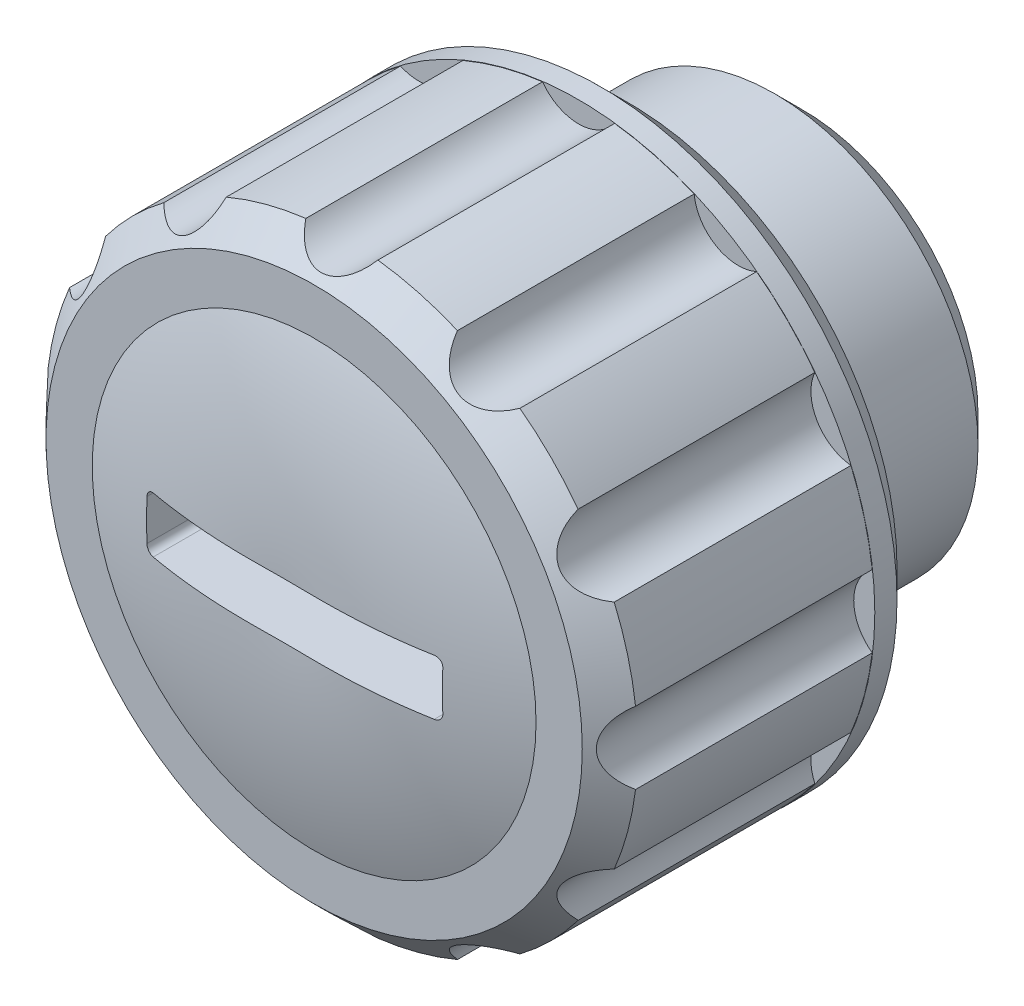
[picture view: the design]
ISO-10303-21;
HEADER;
FILE_DESCRIPTION(('STEP AP214'),'2;1');
FILE_NAME('part.step','',(''),(''),'','','');
FILE_SCHEMA(('AUTOMOTIVE_DESIGN { 1 0 10303 214 1 1 1 1 }'));
ENDSEC;
DATA;
#1=APPLICATION_CONTEXT('core data for automotive mechanical design processes');
#2=APPLICATION_PROTOCOL_DEFINITION('international standard','automotive_design',2000,#1);
#3=PRODUCT_CONTEXT('',#1,'mechanical');
#4=PRODUCT('Part','Part','',(#3));
#5=PRODUCT_RELATED_PRODUCT_CATEGORY('part','',(#4));
#6=PRODUCT_DEFINITION_FORMATION('','',#4);
#7=PRODUCT_DEFINITION_CONTEXT('part definition',#1,'design');
#8=PRODUCT_DEFINITION('design','',#6,#7);
#9=PRODUCT_DEFINITION_SHAPE('','',#8);
#10=(LENGTH_UNIT() NAMED_UNIT(*) SI_UNIT(.MILLI.,.METRE.));
#11=(NAMED_UNIT(*) PLANE_ANGLE_UNIT() SI_UNIT($,.RADIAN.));
#12=(NAMED_UNIT(*) SI_UNIT($,.STERADIAN.) SOLID_ANGLE_UNIT());
#13=UNCERTAINTY_MEASURE_WITH_UNIT(LENGTH_MEASURE(1.E-05),#10,'distance_accuracy_value','');
#14=(GEOMETRIC_REPRESENTATION_CONTEXT(3) GLOBAL_UNCERTAINTY_ASSIGNED_CONTEXT((#13)) GLOBAL_UNIT_ASSIGNED_CONTEXT((#10,
#11,#12)) REPRESENTATION_CONTEXT('',''));
#15=CARTESIAN_POINT('',(0.,0.,0.));
#16=DIRECTION('',(0.,0.,1.));
#17=DIRECTION('',(1.,0.,0.));
#18=AXIS2_PLACEMENT_3D('',#15,#16,#17);
#19=CARTESIAN_POINT('',(0.,0.,-0.703698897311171));
#20=DIRECTION('',(0.,0.,1.));
#21=DIRECTION('',(1.,0.,0.));
#22=AXIS2_PLACEMENT_3D('',#19,#20,#21);
#23=DEGENERATE_TOROIDAL_SURFACE('',#22,1.1776626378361,15.,.T.);
#24=CARTESIAN_POINT('',(0.,0.,13.5));
#25=DIRECTION('',(0.,0.,1.));
#26=DIRECTION('',(1.,0.,0.));
#27=AXIS2_PLACEMENT_3D('',#24,#25,#26);
#28=CIRCLE('',#27,6.);
#29=CARTESIAN_POINT('',(6.,0.,13.5));
#30=VERTEX_POINT('',#29);
#31=EDGE_CURVE('E425',#30,#30,#28,.T.);
#32=ORIENTED_EDGE('',*,*,#31,.T.);
#33=EDGE_LOOP('',(#32));
#34=FACE_BOUND('',#33,.T.);
#35=CARTESIAN_POINT('',(-3.7998,-0.749999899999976,14.0521326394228));
#36=CARTESIAN_POINT('',(-3.81114880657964,-0.750020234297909,14.0500982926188));
#37=CARTESIAN_POINT('',(-3.82250108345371,-0.749057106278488,14.0480843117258));
#38=CARTESIAN_POINT('',(-3.84489426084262,-0.745224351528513,14.0441543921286));
#39=CARTESIAN_POINT('',(-3.85593522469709,-0.742355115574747,14.0422384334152));
#40=CARTESIAN_POINT('',(-3.87740011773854,-0.734767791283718,14.0385596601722));
#41=CARTESIAN_POINT('',(-3.88782359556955,-0.730048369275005,14.0367969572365));
#42=CARTESIAN_POINT('',(-3.90773653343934,-0.718887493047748,14.0334807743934));
#43=CARTESIAN_POINT('',(-3.91722631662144,-0.712446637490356,14.0319272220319));
#44=CARTESIAN_POINT('',(-3.93490505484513,-0.698084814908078,14.0290917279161));
#45=CARTESIAN_POINT('',(-3.9431055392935,-0.690178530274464,14.027807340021));
#46=CARTESIAN_POINT('',(-3.95806529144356,-0.673063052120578,14.025533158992));
#47=CARTESIAN_POINT('',(-3.96482436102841,-0.663853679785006,14.0245434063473));
#48=CARTESIAN_POINT('',(-3.97659283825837,-0.644555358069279,14.0229052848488));
#49=CARTESIAN_POINT('',(-3.98162854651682,-0.634482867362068,14.0222516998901));
#50=CARTESIAN_POINT('',(-3.98994131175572,-0.613624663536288,14.0212843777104));
#51=CARTESIAN_POINT('',(-3.99321964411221,-0.602839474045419,14.0209703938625));
#52=CARTESIAN_POINT('',(-3.99704991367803,-0.584948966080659,14.0207435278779));
#53=CARTESIAN_POINT('',(-3.99816189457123,-0.577959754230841,14.0207251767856));
#54=CARTESIAN_POINT('',(-3.99964030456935,-0.563913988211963,14.0208265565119));
#55=CARTESIAN_POINT('',(-4.00000779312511,-0.556857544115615,14.0209460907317));
#56=CARTESIAN_POINT('',(-3.9999999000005,-0.549800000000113,14.0211342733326));
#57=B_SPLINE_CURVE_WITH_KNOTS('',3,(#35,#36,#37,#38,#39,#40,#41,#42,#43,#44,#45,#46,#47,#48,#49,
#50,#51,#52,#53,#54,#55,#56),.UNSPECIFIED.,.F.,.F.,(4,2,2,2,2,2,2,2,2,2,4),(0.,
0.0345466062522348,0.0690861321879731,0.103650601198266,0.138203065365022,0.172426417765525,
0.206654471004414,0.240334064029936,0.273989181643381,0.295182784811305,0.316346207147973),.UNSPECIFIED.);
#58=CARTESIAN_POINT('',(-3.8,-0.75,14.0520967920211));
#59=VERTEX_POINT('',#58);
#60=CARTESIAN_POINT('',(-4.,-0.55,14.02112896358));
#61=VERTEX_POINT('',#60);
#62=EDGE_CURVE('E27',#59,#61,#57,.T.);
#63=ORIENTED_EDGE('',*,*,#62,.T.);
#64=CARTESIAN_POINT('',(-4.,0.,14.028388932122));
#65=CARTESIAN_POINT('',(-4.,0.339153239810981,14.0283961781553));
#66=CARTESIAN_POINT('',(-4.,0.678323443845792,14.0201840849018));
#67=CARTESIAN_POINT('',(-4.,1.35574448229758,13.9866878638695));
#68=CARTESIAN_POINT('',(-4.,1.69399552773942,13.9614080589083));
#69=CARTESIAN_POINT('',(-4.,2.36814839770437,13.8923714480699));
#70=CARTESIAN_POINT('',(-4.,2.7040529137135,13.8486414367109));
#71=CARTESIAN_POINT('',(-4.,3.37274568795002,13.7413643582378));
#72=CARTESIAN_POINT('',(-4.,3.70553346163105,13.6778142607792));
#73=CARTESIAN_POINT('',(-4.,4.45788889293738,13.5095576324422));
#74=CARTESIAN_POINT('',(-4.,4.87602372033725,13.3983308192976));
#75=CARTESIAN_POINT('',(-4.,5.70161656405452,13.1413580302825));
#76=CARTESIAN_POINT('',(-4.,6.10907328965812,12.9956079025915));
#77=CARTESIAN_POINT('',(-4.,6.91043852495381,12.6696375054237));
#78=CARTESIAN_POINT('',(-4.,7.30433371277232,12.4893844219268));
#79=CARTESIAN_POINT('',(-4.,8.07498519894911,12.0953512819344));
#80=CARTESIAN_POINT('',(-4.,8.45174183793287,11.8815718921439));
#81=CARTESIAN_POINT('',(-4.,9.18281763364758,11.4232419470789));
#82=CARTESIAN_POINT('',(-4.,9.53726091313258,11.1788894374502));
#83=CARTESIAN_POINT('',(-4.,10.2233955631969,10.6600773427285));
#84=CARTESIAN_POINT('',(-4.,10.5550867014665,10.3856174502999));
#85=CARTESIAN_POINT('',(-4.,11.1930381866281,9.8086212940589));
#86=CARTESIAN_POINT('',(-4.,11.4993002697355,9.50608695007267));
#87=CARTESIAN_POINT('',(-4.,12.0839658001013,8.87520844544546));
#88=CARTESIAN_POINT('',(-4.,12.3623701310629,8.54686510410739));
#89=CARTESIAN_POINT('',(-4.,12.8784698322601,7.8806109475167));
#90=CARTESIAN_POINT('',(-4.,13.1173543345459,7.54362037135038));
#91=CARTESIAN_POINT('',(-4.,13.5656684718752,6.85059247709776));
#92=CARTESIAN_POINT('',(-4.,13.7750989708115,6.49455571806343));
#93=CARTESIAN_POINT('',(-4.,14.1629376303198,5.76604322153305));
#94=CARTESIAN_POINT('',(-4.,14.3413507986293,5.39357014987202));
#95=CARTESIAN_POINT('',(-4.,14.6658865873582,4.63480988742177));
#96=CARTESIAN_POINT('',(-4.,14.8120091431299,4.24852266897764));
#97=CARTESIAN_POINT('',(-4.,15.0699099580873,3.46788913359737));
#98=CARTESIAN_POINT('',(-4.,15.1819394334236,3.07362578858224));
#99=CARTESIAN_POINT('',(-4.,15.3723250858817,2.2770527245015));
#100=CARTESIAN_POINT('',(-4.,15.4506814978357,1.87474306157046));
#101=CARTESIAN_POINT('',(-4.,15.5731575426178,1.06492658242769));
#102=CARTESIAN_POINT('',(-4.,15.617275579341,0.657419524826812));
#103=CARTESIAN_POINT('',(-4.,15.6709496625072,-0.159864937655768));
#104=CARTESIAN_POINT('',(-4.,15.6805056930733,-0.569642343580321));
#105=CARTESIAN_POINT('',(-4.,15.665001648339,-1.38774900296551));
#106=CARTESIAN_POINT('',(-4.,15.6400084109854,-1.7960795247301));
#107=CARTESIAN_POINT('',(-4.,15.5557048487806,-2.60918184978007));
#108=CARTESIAN_POINT('',(-4.,15.4963945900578,-3.01395365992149));
#109=CARTESIAN_POINT('',(-4.,15.3438918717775,-3.8170229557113));
#110=CARTESIAN_POINT('',(-4.,15.2507026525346,-4.21532105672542));
#111=CARTESIAN_POINT('',(-4.,15.0311128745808,-5.00265431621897));
#112=CARTESIAN_POINT('',(-4.,14.9047123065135,-5.39168947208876));
#113=CARTESIAN_POINT('',(-4.,14.619619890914,-6.15771427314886));
#114=CARTESIAN_POINT('',(-4.,14.4609300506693,-6.53470466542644));
#115=CARTESIAN_POINT('',(-4.,14.112398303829,-7.27399825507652));
#116=CARTESIAN_POINT('',(-4.,13.9225564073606,-7.63630145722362));
#117=CARTESIAN_POINT('',(-4.,13.5130367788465,-8.34375702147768));
#118=CARTESIAN_POINT('',(-4.,13.2933514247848,-8.68890497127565));
#119=CARTESIAN_POINT('',(-4.,12.825767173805,-9.35952806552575));
#120=CARTESIAN_POINT('',(-4.,12.5778682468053,-9.68500318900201));
#121=CARTESIAN_POINT('',(-4.,12.0550681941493,-10.3147088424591));
#122=CARTESIAN_POINT('',(-4.,11.7801085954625,-10.6188908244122));
#123=CARTESIAN_POINT('',(-4.,11.2056412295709,-11.2031141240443));
#124=CARTESIAN_POINT('',(-4.,10.9061334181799,-11.4831553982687));
#125=CARTESIAN_POINT('',(-4.,10.2849635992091,-12.0170071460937));
#126=CARTESIAN_POINT('',(-4.,9.96331753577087,-12.2708361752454));
#127=CARTESIAN_POINT('',(-4.,9.30001359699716,-12.7508263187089));
#128=CARTESIAN_POINT('',(-4.,8.95835585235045,-12.9769876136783));
#129=CARTESIAN_POINT('',(-4.,8.25506085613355,-13.4017235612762));
#130=CARTESIAN_POINT('',(-4.,7.89330122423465,-13.6000955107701));
#131=CARTESIAN_POINT('',(-4.,7.1546361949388,-13.9662854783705));
#132=CARTESIAN_POINT('',(-4.,6.77773047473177,-14.1341028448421));
#133=CARTESIAN_POINT('',(-4.,6.01113338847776,-14.4386630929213));
#134=CARTESIAN_POINT('',(-4.,5.62142902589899,-14.5753731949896));
#135=CARTESIAN_POINT('',(-4.,4.83241304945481,-14.817363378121));
#136=CARTESIAN_POINT('',(-4.,4.4331021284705,-14.9226457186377));
#137=CARTESIAN_POINT('',(-4.,3.77164652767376,-15.0703302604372));
#138=CARTESIAN_POINT('',(-4.,3.51147362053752,-15.1217585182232));
#139=CARTESIAN_POINT('',(-4.,2.98899804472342,-15.2123395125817));
#140=CARTESIAN_POINT('',(-4.,2.7266952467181,-15.2514914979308));
#141=CARTESIAN_POINT('',(-4.,1.93724201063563,-15.3514509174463));
#142=CARTESIAN_POINT('',(-4.,1.40777675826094,-15.3947116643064));
#143=CARTESIAN_POINT('',(-4.,0.612198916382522,-15.4285188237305));
#144=CARTESIAN_POINT('',(-4.,0.346571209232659,-15.4345998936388));
#145=CARTESIAN_POINT('',(-4.,-0.184756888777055,-15.4366600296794));
#146=CARTESIAN_POINT('',(-4.,-0.450457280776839,-15.4326389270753));
#147=CARTESIAN_POINT('',(-4.,-0.981374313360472,-15.4142959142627));
#148=CARTESIAN_POINT('',(-4.,-1.24659112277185,-15.3999788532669));
#149=CARTESIAN_POINT('',(-4.,-1.7762314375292,-15.3604541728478));
#150=CARTESIAN_POINT('',(-4.,-2.04065492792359,-15.3352463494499));
#151=CARTESIAN_POINT('',(-4.,-2.52470132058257,-15.2783376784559));
#152=CARTESIAN_POINT('',(-4.,-2.74453002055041,-15.248390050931));
#153=CARTESIAN_POINT('',(-4.,-3.18285214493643,-15.1800456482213));
#154=CARTESIAN_POINT('',(-4.,-3.40134562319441,-15.1416492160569));
#155=CARTESIAN_POINT('',(-4.,-4.05419633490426,-15.0133381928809));
#156=CARTESIAN_POINT('',(-4.,-4.48606739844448,-14.9102854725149));
#157=CARTESIAN_POINT('',(-4.,-5.33835432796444,-14.6682914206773));
#158=CARTESIAN_POINT('',(-4.,-5.75879820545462,-14.5294486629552));
#159=CARTESIAN_POINT('',(-4.,-6.58609234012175,-14.2156839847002));
#160=CARTESIAN_POINT('',(-4.,-6.99294114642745,-14.0407582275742));
#161=CARTESIAN_POINT('',(-4.,-7.79138450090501,-13.6547019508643));
#162=CARTESIAN_POINT('',(-4.,-8.18290123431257,-13.4434103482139));
#163=CARTESIAN_POINT('',(-4.,-8.94537896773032,-12.9865110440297));
#164=CARTESIAN_POINT('',(-4.,-9.31634014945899,-12.7409036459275));
#165=CARTESIAN_POINT('',(-4.,-10.0350527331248,-12.2167860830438));
#166=CARTESIAN_POINT('',(-4.,-10.3827705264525,-11.9382298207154));
#167=CARTESIAN_POINT('',(-4.,-11.0514362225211,-11.350662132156));
#168=CARTESIAN_POINT('',(-4.,-11.3723853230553,-11.0416520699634));
#169=CARTESIAN_POINT('',(-4.,-11.9642331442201,-10.4173353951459));
#170=CARTESIAN_POINT('',(-4.,-12.2370447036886,-10.1038391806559));
#171=CARTESIAN_POINT('',(-4.,-12.7549508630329,-9.4547474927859));
#172=CARTESIAN_POINT('',(-4.,-13.0000469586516,-9.11915321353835));
#173=CARTESIAN_POINT('',(-4.,-13.4605522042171,-8.42850547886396));
#174=CARTESIAN_POINT('',(-4.,-13.67598107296,-8.07346517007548));
#175=CARTESIAN_POINT('',(-4.,-14.0757477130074,-7.34628666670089));
#176=CARTESIAN_POINT('',(-4.,-14.2600853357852,-6.97414839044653));
#177=CARTESIAN_POINT('',(-4.,-14.5943069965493,-6.21997693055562));
#178=CARTESIAN_POINT('',(-4.,-14.7445728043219,-5.83811287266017));
#179=CARTESIAN_POINT('',(-4.,-15.0123145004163,-5.06306047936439));
#180=CARTESIAN_POINT('',(-4.,-15.1297907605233,-4.669872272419));
#181=CARTESIAN_POINT('',(-4.,-15.3311166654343,-3.87492033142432));
#182=CARTESIAN_POINT('',(-4.,-15.4149615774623,-3.47315539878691));
#183=CARTESIAN_POINT('',(-4.,-15.5483930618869,-2.66397544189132));
#184=CARTESIAN_POINT('',(-4.,-15.5979796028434,-2.25656041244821));
#185=CARTESIAN_POINT('',(-4.,-15.6624394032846,-1.44020146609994));
#186=CARTESIAN_POINT('',(-4.,-15.6774144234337,-1.03126558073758));
#187=CARTESIAN_POINT('',(-4.,-15.6728420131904,-0.213587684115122));
#188=CARTESIAN_POINT('',(-4.,-15.653294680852,0.19515432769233));
#189=CARTESIAN_POINT('',(-4.,-15.5798200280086,1.00952109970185));
#190=CARTESIAN_POINT('',(-4.,-15.5258939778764,1.41514597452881));
#191=CARTESIAN_POINT('',(-4.,-15.3840519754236,2.22040863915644));
#192=CARTESIAN_POINT('',(-4.,-15.2961360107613,2.62004642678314));
#193=CARTESIAN_POINT('',(-4.,-15.0869932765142,3.41032437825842));
#194=CARTESIAN_POINT('',(-4.,-14.9657808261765,3.8009683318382));
#195=CARTESIAN_POINT('',(-4.,-14.6909025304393,4.57066557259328));
#196=CARTESIAN_POINT('',(-4.,-14.5372367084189,4.94971886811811));
#197=CARTESIAN_POINT('',(-4.,-14.198563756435,5.6935427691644));
#198=CARTESIAN_POINT('',(-4.,-14.0135574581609,6.05831375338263));
#199=CARTESIAN_POINT('',(-4.,-13.6135344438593,6.77101064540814));
#200=CARTESIAN_POINT('',(-4.,-13.3985177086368,7.11893654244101));
#201=CARTESIAN_POINT('',(-4.,-12.9397392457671,7.79592064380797));
#202=CARTESIAN_POINT('',(-4.,-12.695942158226,8.12495488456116));
#203=CARTESIAN_POINT('',(-4.,-12.1815798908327,8.76138756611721));
#204=CARTESIAN_POINT('',(-4.,-11.91101469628,9.068785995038));
#205=CARTESIAN_POINT('',(-4.,-11.3450384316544,9.65985804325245));
#206=CARTESIAN_POINT('',(-4.,-11.049624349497,9.94352877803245));
#207=CARTESIAN_POINT('',(-4.,-10.4361166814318,10.4851767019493));
#208=CARTESIAN_POINT('',(-4.,-10.1180230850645,10.7431538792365));
#209=CARTESIAN_POINT('',(-4.,-9.45975657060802,11.2329803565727));
#210=CARTESIAN_POINT('',(-4.,-9.11947790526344,11.4646875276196));
#211=CARTESIAN_POINT('',(-4.,-8.42081797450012,11.8989645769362));
#212=CARTESIAN_POINT('',(-4.,-8.06243669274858,12.1015344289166));
#213=CARTESIAN_POINT('',(-4.,-7.33043234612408,12.476268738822));
#214=CARTESIAN_POINT('',(-4.,-6.95681985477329,12.6484538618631));
#215=CARTESIAN_POINT('',(-4.,-6.19684574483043,12.961845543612));
#216=CARTESIAN_POINT('',(-4.,-5.81048403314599,13.1030518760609));
#217=CARTESIAN_POINT('',(-4.,-4.98307663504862,13.3686004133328));
#218=CARTESIAN_POINT('',(-4.,-4.54082134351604,13.4891802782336));
#219=CARTESIAN_POINT('',(-4.,-3.64769934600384,13.6923551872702));
#220=CARTESIAN_POINT('',(-4.,-3.19683149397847,13.774945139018));
#221=CARTESIAN_POINT('',(-4.,-2.28933102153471,13.9045907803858));
#222=CARTESIAN_POINT('',(-4.,-1.83269032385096,13.9515893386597));
#223=CARTESIAN_POINT('',(-4.,-1.14623014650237,13.9979727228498));
#224=CARTESIAN_POINT('',(-4.,-0.917138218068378,14.0094147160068));
#225=CARTESIAN_POINT('',(-4.,-0.458700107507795,14.0246202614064));
#226=CARTESIAN_POINT('',(-4.,-0.229353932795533,14.0283840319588));
#227=CARTESIAN_POINT('',(-4.,0.,14.028388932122));
#228=B_SPLINE_CURVE_WITH_KNOTS('',3,(#64,#65,#66,#67,#68,#69,#70,#71,#72,#73,#74,#75,#76,#77,
#78,#79,#80,#81,#82,#83,#84,#85,#86,#87,#88,#89,#90,#91,#92,#93,#94,#95,#96,#97,#98,#99,#100,
#101,#102,#103,#104,#105,#106,#107,#108,#109,#110,#111,#112,#113,#114,#115,#116,#117,#118,#119,
#120,#121,#122,#123,#124,#125,#126,#127,#128,#129,#130,#131,#132,#133,#134,#135,#136,#137,#138,
#139,#140,#141,#142,#143,#144,#145,#146,#147,#148,#149,#150,#151,#152,#153,#154,#155,#156,#157,
#158,#159,#160,#161,#162,#163,#164,#165,#166,#167,#168,#169,#170,#171,#172,#173,#174,#175,#176,
#177,#178,#179,#180,#181,#182,#183,#184,#185,#186,#187,#188,#189,#190,#191,#192,#193,#194,#195,
#196,#197,#198,#199,#200,#201,#202,#203,#204,#205,#206,#207,#208,#209,#210,#211,#212,#213,#214,
#215,#216,#217,#218,#219,#220,#221,#222,#223,#224,#225,#226,#227),.UNSPECIFIED.,.T.,.F.,(4,2,2,
2,2,2,2,2,2,2,2,2,2,2,2,2,2,2,2,2,2,2,2,2,2,2,2,2,2,2,2,2,2,2,2,2,2,2,2,2,2,2,2,2,2,2,2,2,2,2,2,
2,2,2,2,2,2,2,2,2,2,2,2,2,2,2,2,2,2,2,2,2,2,2,2,2,2,2,2,2,2,4),(0.,1.01738294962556,
2.03450831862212,3.05016161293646,4.06597026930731,5.36249424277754,6.6591742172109,
7.95709358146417,9.25498713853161,10.5448707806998,11.8347675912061,13.1245762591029,
14.4143439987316,15.6520836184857,16.8897869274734,18.1272902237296,19.3647959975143,
20.5929491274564,21.8210936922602,23.0492955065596,24.2774978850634,25.5033275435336,
26.7291548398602,27.9548649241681,29.1805753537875,30.4062096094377,31.6318434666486,
32.8577909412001,34.0837397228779,35.3123982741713,36.5410590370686,37.7688439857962,
38.9966209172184,40.2329329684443,41.4692713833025,42.7069066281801,43.9444528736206,
44.7397910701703,45.5351779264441,47.1266553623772,47.9236225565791,48.7206030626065,
49.5172084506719,50.3138287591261,50.9792441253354,51.6446324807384,52.9749769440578,
54.301695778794,55.6285557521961,56.9614518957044,58.2943362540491,59.6291079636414,
60.9638199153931,62.2090674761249,63.4542478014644,64.6985964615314,65.9429510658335,
67.1725857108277,68.4022064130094,69.6320000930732,70.8617949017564,72.0879693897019,
73.3141403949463,74.5402660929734,75.7663922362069,76.9919919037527,78.2175906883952,
79.4431569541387,80.6687240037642,81.8958127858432,83.1229022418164,84.3501406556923,
85.5773796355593,86.8109699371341,88.0445613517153,89.2773105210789,90.510068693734,
91.8834796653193,93.2570746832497,94.632869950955,95.3208993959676,96.0089092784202),.UNSPECIFIED.);
#229=CARTESIAN_POINT('',(-4.,0.55,14.02112896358));
#230=VERTEX_POINT('',#229);
#231=EDGE_CURVE('E9',#61,#230,#228,.T.);
#232=ORIENTED_EDGE('',*,*,#231,.T.);
#233=CARTESIAN_POINT('',(-3.99999989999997,0.5498,14.0211342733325));
#234=CARTESIAN_POINT('',(-4.00002120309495,0.560882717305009,14.0208370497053));
#235=CARTESIAN_POINT('',(-3.99910147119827,0.571967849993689,14.0207119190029));
#236=CARTESIAN_POINT('',(-3.99545102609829,0.59382219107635,14.0208010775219));
#237=CARTESIAN_POINT('',(-3.99272233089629,0.604591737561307,14.021014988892));
#238=CARTESIAN_POINT('',(-3.98552323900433,0.625524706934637,14.0217769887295));
#239=CARTESIAN_POINT('',(-3.98105209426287,0.635687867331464,14.0223252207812));
#240=CARTESIAN_POINT('',(-3.97050578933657,0.655118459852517,14.0237373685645));
#241=CARTESIAN_POINT('',(-3.96443078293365,0.664385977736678,14.0246012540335));
#242=CARTESIAN_POINT('',(-3.95082544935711,0.681812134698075,14.0266217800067));
#243=CARTESIAN_POINT('',(-3.94328885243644,0.689965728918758,14.0277796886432));
#244=CARTESIAN_POINT('',(-3.92699598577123,0.704900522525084,14.030350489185));
#245=CARTESIAN_POINT('',(-3.91823946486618,0.711681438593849,14.0317634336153));
#246=CARTESIAN_POINT('',(-3.89962640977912,0.723780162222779,14.0348229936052));
#247=CARTESIAN_POINT('',(-3.88975612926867,0.729076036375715,14.0364726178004));
#248=CARTESIAN_POINT('',(-3.86929754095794,0.737941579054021,14.0399411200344));
#249=CARTESIAN_POINT('',(-3.858709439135,0.741511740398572,14.0417599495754));
#250=CARTESIAN_POINT('',(-3.84003688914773,0.746119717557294,14.0450054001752));
#251=CARTESIAN_POINT('',(-3.83204943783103,0.747581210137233,14.046405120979));
#252=CARTESIAN_POINT('',(-3.8159747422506,0.749525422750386,14.0492439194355));
#253=CARTESIAN_POINT('',(-3.80788765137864,0.750009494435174,14.0506829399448));
#254=CARTESIAN_POINT('',(-3.79980000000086,0.749999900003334,14.052132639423));
#255=B_SPLINE_CURVE_WITH_KNOTS('',3,(#233,#234,#235,#236,#237,#238,#239,#240,#241,#242,#243,
#244,#245,#246,#247,#248,#249,#250,#251,#252,#253,#254),.UNSPECIFIED.,.F.,.F.,(4,2,2,2,2,2,2,2,
2,2,4),(0.,0.0332152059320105,0.0663934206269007,0.0995858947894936,0.132775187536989,
0.166110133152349,0.199451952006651,0.233262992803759,0.267064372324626,0.291727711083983,
0.316356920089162),.UNSPECIFIED.);
#256=CARTESIAN_POINT('',(-3.79999999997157,0.75,14.0520967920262));
#257=VERTEX_POINT('',#256);
#258=EDGE_CURVE('E488',#230,#257,#255,.T.);
#259=ORIENTED_EDGE('',*,*,#258,.T.);
#260=CARTESIAN_POINT('',(0.,0.75,14.2902033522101));
#261=CARTESIAN_POINT('',(0.062509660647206,0.75,14.2902036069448));
#262=CARTESIAN_POINT('',(0.125019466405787,0.75,14.2904360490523));
#263=CARTESIAN_POINT('',(0.250036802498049,0.75,14.291252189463));
#264=CARTESIAN_POINT('',(0.312544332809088,0.75,14.2918358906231));
#265=CARTESIAN_POINT('',(0.437565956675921,0.75,14.2930988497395));
#266=CARTESIAN_POINT('',(0.500080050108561,0.75,14.2937781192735));
#267=CARTESIAN_POINT('',(0.625113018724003,0.75,14.2949804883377));
#268=CARTESIAN_POINT('',(0.687631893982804,0.75,14.2955035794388));
#269=CARTESIAN_POINT('',(0.875766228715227,0.75,14.2965328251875));
#270=CARTESIAN_POINT('',(1.00138686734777,0.75,14.2964891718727));
#271=CARTESIAN_POINT('',(1.25260493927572,0.75,14.2940460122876));
#272=CARTESIAN_POINT('',(1.37820237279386,0.75,14.2916465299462));
#273=CARTESIAN_POINT('',(1.75485708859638,0.75,14.2803277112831));
#274=CARTESIAN_POINT('',(2.00580900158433,0.75,14.2672884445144));
#275=CARTESIAN_POINT('',(2.50689880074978,0.75,14.2291477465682));
#276=CARTESIAN_POINT('',(2.75703633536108,0.75,14.2040416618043));
#277=CARTESIAN_POINT('',(3.25583549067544,0.75,14.1415504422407));
#278=CARTESIAN_POINT('',(3.5044966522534,0.75,14.1041616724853));
#279=CARTESIAN_POINT('',(4.16871083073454,0.75,13.9873107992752));
#280=CARTESIAN_POINT('',(4.58233519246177,0.75,13.8965497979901));
#281=CARTESIAN_POINT('',(5.40052634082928,0.75,13.6805066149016));
#282=CARTESIAN_POINT('',(5.80509101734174,0.75,13.5552164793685));
#283=CARTESIAN_POINT('',(6.60293944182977,0.75,13.2706758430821));
#284=CARTESIAN_POINT('',(6.99620137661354,0.75,13.1113641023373));
#285=CARTESIAN_POINT('',(7.76780860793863,0.75,12.760031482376));
#286=CARTESIAN_POINT('',(8.14615456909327,0.75,12.5680120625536));
#287=CARTESIAN_POINT('',(8.88446706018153,0.75,12.1530468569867));
#288=CARTESIAN_POINT('',(9.2444697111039,0.75,11.9301653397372));
#289=CARTESIAN_POINT('',(9.9443450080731,0.75,11.4547620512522));
#290=CARTESIAN_POINT('',(10.2842175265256,0.75,11.2022400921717));
#291=CARTESIAN_POINT('',(10.9411846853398,0.75,10.6695279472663));
#292=CARTESIAN_POINT('',(11.2582935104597,0.75,10.3893552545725));
#293=CARTESIAN_POINT('',(11.867695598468,0.75,9.80321084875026));
#294=CARTESIAN_POINT('',(12.1599889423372,0.75,9.49723921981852));
#295=CARTESIAN_POINT('',(12.7167806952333,0.75,8.86269415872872));
#296=CARTESIAN_POINT('',(12.9813643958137,0.75,8.53419556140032));
#297=CARTESIAN_POINT('',(13.4819097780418,0.75,7.85607214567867));
#298=CARTESIAN_POINT('',(13.7178715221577,0.75,7.50644737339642));
#299=CARTESIAN_POINT('',(14.1595322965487,0.75,6.78849443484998));
#300=CARTESIAN_POINT('',(14.3652260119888,0.75,6.42016299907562));
#301=CARTESIAN_POINT('',(14.7448367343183,0.75,5.66747355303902));
#302=CARTESIAN_POINT('',(14.9187537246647,0.75,5.28311553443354));
#303=CARTESIAN_POINT('',(15.2335050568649,0.75,4.50127546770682));
#304=CARTESIAN_POINT('',(15.3743535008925,0.75,4.10379909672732));
#305=CARTESIAN_POINT('',(15.6220611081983,0.75,3.29839291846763));
#306=CARTESIAN_POINT('',(15.7289202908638,0.75,2.89046311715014));
#307=CARTESIAN_POINT('',(15.9078821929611,0.75,2.06708280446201));
#308=CARTESIAN_POINT('',(15.9799876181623,0.75,1.65163288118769));
#309=CARTESIAN_POINT('',(16.0889414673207,0.75,0.816135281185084));
#310=CARTESIAN_POINT('',(16.1257898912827,0.75,0.396087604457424));
#311=CARTESIAN_POINT('',(16.163965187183,0.75,-0.445565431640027));
#312=CARTESIAN_POINT('',(16.1652965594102,0.75,-0.867170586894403));
#313=CARTESIAN_POINT('',(16.1324397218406,0.75,-1.7089944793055));
#314=CARTESIAN_POINT('',(16.0982515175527,0.75,-2.12921321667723));
#315=CARTESIAN_POINT('',(15.994590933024,0.75,-2.96533956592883));
#316=CARTESIAN_POINT('',(15.9251132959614,0.75,-3.38124652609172));
#317=CARTESIAN_POINT('',(15.751365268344,0.75,-4.20572862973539));
#318=CARTESIAN_POINT('',(15.6470948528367,0.75,-4.61430376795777));
#319=CARTESIAN_POINT('',(15.4044819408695,0.75,-5.42128714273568));
#320=CARTESIAN_POINT('',(15.2661335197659,0.75,-5.8196935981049));
#321=CARTESIAN_POINT('',(14.9563586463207,0.75,-6.6034316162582));
#322=CARTESIAN_POINT('',(14.7849322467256,0.75,-6.9887631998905));
#323=CARTESIAN_POINT('',(14.410318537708,0.75,-7.74341593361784));
#324=CARTESIAN_POINT('',(14.2071477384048,0.75,-8.11274527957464));
#325=CARTESIAN_POINT('',(13.7704245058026,0.75,-8.83298393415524));
#326=CARTESIAN_POINT('',(13.5368719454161,0.75,-9.18389316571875));
#327=CARTESIAN_POINT('',(13.0411762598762,0.75,-9.86461934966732));
#328=CARTESIAN_POINT('',(12.7790481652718,0.75,-10.1944472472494));
#329=CARTESIAN_POINT('',(12.2279683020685,0.75,-10.8308662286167));
#330=CARTESIAN_POINT('',(11.9390170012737,0.75,-11.1374577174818));
#331=CARTESIAN_POINT('',(11.3358371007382,0.75,-11.7257264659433));
#332=CARTESIAN_POINT('',(11.0215672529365,0.75,-12.0073614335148));
#333=CARTESIAN_POINT('',(10.3703891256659,0.75,-12.5431585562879));
#334=CARTESIAN_POINT('',(10.0334794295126,0.75,-12.7973189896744));
#335=CARTESIAN_POINT('',(9.33882156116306,0.75,-13.2767706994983));
#336=CARTESIAN_POINT('',(8.98103735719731,0.75,-13.5020097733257));
#337=CARTESIAN_POINT('',(8.24780759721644,0.75,-13.9214489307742));
#338=CARTESIAN_POINT('',(7.87236542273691,0.75,-14.1156549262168));
#339=CARTESIAN_POINT('',(7.10830459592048,0.75,-14.4708441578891));
#340=CARTESIAN_POINT('',(6.71975907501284,0.75,-14.6319846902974));
#341=CARTESIAN_POINT('',(5.93032689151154,0.75,-14.9212008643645));
#342=CARTESIAN_POINT('',(5.52943355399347,0.75,-15.049258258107));
#343=CARTESIAN_POINT('',(4.71037120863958,0.75,-15.2735305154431));
#344=CARTESIAN_POINT('',(4.29201779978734,0.75,-15.3690765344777));
#345=CARTESIAN_POINT('',(3.65997311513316,0.75,-15.485449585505));
#346=CARTESIAN_POINT('',(3.44867138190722,0.75,-15.5197366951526));
#347=CARTESIAN_POINT('',(3.02478880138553,0.75,-15.5793924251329));
#348=CARTESIAN_POINT('',(2.81220789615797,0.75,-15.6047606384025));
#349=CARTESIAN_POINT('',(2.38452719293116,0.75,-15.6468286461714));
#350=CARTESIAN_POINT('',(2.16942066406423,0.75,-15.6634594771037));
#351=CARTESIAN_POINT('',(1.73875062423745,0.75,-15.6880212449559));
#352=CARTESIAN_POINT('',(1.5231871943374,0.75,-15.6959536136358));
#353=CARTESIAN_POINT('',(1.19954465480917,0.75,-15.7021388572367));
#354=CARTESIAN_POINT('',(1.09150789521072,0.75,-15.7032466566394));
#355=CARTESIAN_POINT('',(0.875426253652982,0.75,-15.7039178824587));
#356=CARTESIAN_POINT('',(0.767381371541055,0.75,-15.7034812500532));
#357=CARTESIAN_POINT('',(0.551281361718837,0.75,-15.7017790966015));
#358=CARTESIAN_POINT('',(0.443226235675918,0.75,-15.7005134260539));
#359=CARTESIAN_POINT('',(0.281143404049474,0.75,-15.6989476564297));
#360=CARTESIAN_POINT('',(0.227117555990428,0.75,-15.698481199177));
#361=CARTESIAN_POINT('',(0.119064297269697,0.75,-15.6978197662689));
#362=CARTESIAN_POINT('',(0.0650368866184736,0.75,-15.6976247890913));
#363=CARTESIAN_POINT('',(-0.05800398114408,0.75,-15.6975761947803));
#364=CARTESIAN_POINT('',(-0.127017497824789,0.75,-15.6978322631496));
#365=CARTESIAN_POINT('',(-0.265042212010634,0.75,-15.6987649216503));
#366=CARTESIAN_POINT('',(-0.334053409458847,0.75,-15.6994415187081));
#367=CARTESIAN_POINT('',(-0.47207998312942,0.75,-15.7008610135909));
#368=CARTESIAN_POINT('',(-0.541095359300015,0.75,-15.7016039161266));
#369=CARTESIAN_POINT('',(-0.679127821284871,0.75,-15.7028300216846));
#370=CARTESIAN_POINT('',(-0.748144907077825,0.75,-15.7033132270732));
#371=CARTESIAN_POINT('',(-0.955164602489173,0.75,-15.7040009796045));
#372=CARTESIAN_POINT('',(-1.0931724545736,0.75,-15.7034443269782));
#373=CARTESIAN_POINT('',(-1.36914222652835,0.75,-15.6993084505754));
#374=CARTESIAN_POINT('',(-1.50710414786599,0.75,-15.6957293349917));
#375=CARTESIAN_POINT('',(-1.78256534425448,0.75,-15.685188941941));
#376=CARTESIAN_POINT('',(-1.92006492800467,0.75,-15.6782359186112));
#377=CARTESIAN_POINT('',(-2.19483905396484,0.75,-15.6607772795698));
#378=CARTESIAN_POINT('',(-2.33211359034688,0.75,-15.6502715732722));
#379=CARTESIAN_POINT('',(-2.743559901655,0.75,-15.6132836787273));
#380=CARTESIAN_POINT('',(-3.01726339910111,0.75,-15.581334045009));
#381=CARTESIAN_POINT('',(-3.55992465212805,0.75,-15.5030144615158));
#382=CARTESIAN_POINT('',(-3.82890277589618,0.75,-15.4567848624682));
#383=CARTESIAN_POINT('',(-4.36392755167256,0.75,-15.3498484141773));
#384=CARTESIAN_POINT('',(-4.62997463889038,0.75,-15.2891437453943));
#385=CARTESIAN_POINT('',(-5.15895710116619,0.75,-15.1532282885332));
#386=CARTESIAN_POINT('',(-5.42188447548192,0.75,-15.0779863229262));
#387=CARTESIAN_POINT('',(-5.94322863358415,0.75,-14.9132881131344));
#388=CARTESIAN_POINT('',(-6.20164546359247,0.75,-14.8238320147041));
#389=CARTESIAN_POINT('',(-6.85115229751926,0.75,-14.5789290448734));
#390=CARTESIAN_POINT('',(-7.23867684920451,0.75,-14.4139021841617));
#391=CARTESIAN_POINT('',(-7.99805018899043,0.75,-14.0520702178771));
#392=CARTESIAN_POINT('',(-8.36991500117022,0.75,-13.8552986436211));
#393=CARTESIAN_POINT('',(-9.09777056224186,0.75,-13.4300705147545));
#394=CARTESIAN_POINT('',(-9.45366504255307,0.75,-13.2014490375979));
#395=CARTESIAN_POINT('',(-10.1449857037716,0.75,-12.714880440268));
#396=CARTESIAN_POINT('',(-10.4804049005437,0.75,-12.4569233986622));
#397=CARTESIAN_POINT('',(-11.1277254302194,0.75,-11.9140206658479));
#398=CARTESIAN_POINT('',(-11.4396635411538,0.75,-11.6291188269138));
#399=CARTESIAN_POINT('',(-12.0383542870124,0.75,-11.0340393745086));
#400=CARTESIAN_POINT('',(-12.3251095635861,0.75,-10.7238644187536));
#401=CARTESIAN_POINT('',(-12.870898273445,0.75,-10.0810426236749));
#402=CARTESIAN_POINT('',(-13.1299839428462,0.75,-9.74844013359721));
#403=CARTESIAN_POINT('',(-13.619228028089,0.75,-9.06258526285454));
#404=CARTESIAN_POINT('',(-13.8493856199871,0.75,-8.70933229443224));
#405=CARTESIAN_POINT('',(-14.2791137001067,0.75,-7.98471878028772));
#406=CARTESIAN_POINT('',(-14.4786861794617,0.75,-7.61335941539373));
#407=CARTESIAN_POINT('',(-14.8458413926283,0.75,-6.85515348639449));
#408=CARTESIAN_POINT('',(-15.0134243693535,0.75,-6.46830703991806));
#409=CARTESIAN_POINT('',(-15.3155070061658,0.75,-5.6816225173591));
#410=CARTESIAN_POINT('',(-15.4499855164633,0.75,-5.2817763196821));
#411=CARTESIAN_POINT('',(-15.6847633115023,0.75,-4.47217121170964));
#412=CARTESIAN_POINT('',(-15.7850625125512,0.75,-4.06241227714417));
#413=CARTESIAN_POINT('',(-15.9507352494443,0.75,-3.23605764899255));
#414=CARTESIAN_POINT('',(-16.0161221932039,0.75,-2.81946464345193));
#415=CARTESIAN_POINT('',(-16.1115638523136,0.75,-1.98225120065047));
#416=CARTESIAN_POINT('',(-16.1416186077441,0.75,-1.56163076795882));
#417=CARTESIAN_POINT('',(-16.1661796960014,0.75,-0.719438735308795));
#418=CARTESIAN_POINT('',(-16.1606932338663,0.75,-0.297867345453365));
#419=CARTESIAN_POINT('',(-16.114227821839,0.75,0.543314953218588));
#420=CARTESIAN_POINT('',(-16.0732488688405,0.75,0.962925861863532));
#421=CARTESIAN_POINT('',(-15.9560905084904,0.75,1.79720001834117));
#422=CARTESIAN_POINT('',(-15.8799114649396,0.75,2.21186331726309));
#423=CARTESIAN_POINT('',(-15.6928948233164,0.75,3.03329916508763));
#424=CARTESIAN_POINT('',(-15.582057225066,0.75,3.44007171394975));
#425=CARTESIAN_POINT('',(-15.3264932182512,0.75,4.24289288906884));
#426=CARTESIAN_POINT('',(-15.181761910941,0.75,4.63893995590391));
#427=CARTESIAN_POINT('',(-14.8594487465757,0.75,5.41743335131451));
#428=CARTESIAN_POINT('',(-14.68186687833,0.75,5.79987967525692));
#429=CARTESIAN_POINT('',(-14.2950896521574,0.75,6.54850360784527));
#430=CARTESIAN_POINT('',(-14.0858900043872,0.75,6.91467900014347));
#431=CARTESIAN_POINT('',(-13.6373836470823,0.75,7.62810226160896));
#432=CARTESIAN_POINT('',(-13.3980769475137,0.75,7.97535013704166));
#433=CARTESIAN_POINT('',(-12.8911539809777,0.75,8.64832469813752));
#434=CARTESIAN_POINT('',(-12.6235482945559,0.75,8.97405935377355));
#435=CARTESIAN_POINT('',(-12.0618570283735,0.75,9.60183607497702));
#436=CARTESIAN_POINT('',(-11.767771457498,0.75,9.9038781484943));
#437=CARTESIAN_POINT('',(-11.1552973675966,0.75,10.4820455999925));
#438=CARTESIAN_POINT('',(-10.8369156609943,0.75,10.758178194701));
#439=CARTESIAN_POINT('',(-10.1780402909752,0.75,11.2826657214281));
#440=CARTESIAN_POINT('',(-9.83754661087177,0.75,11.5310206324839));
#441=CARTESIAN_POINT('',(-9.13645925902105,0.75,11.9984683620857));
#442=CARTESIAN_POINT('',(-8.775842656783,0.75,12.2175267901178));
#443=CARTESIAN_POINT('',(-8.03744530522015,0.75,12.6244922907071));
#444=CARTESIAN_POINT('',(-7.65966465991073,0.75,12.8123995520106));
#445=CARTESIAN_POINT('',(-6.88907462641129,0.75,13.1559939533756));
#446=CARTESIAN_POINT('',(-6.49624456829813,0.75,13.3116347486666));
#447=CARTESIAN_POINT('',(-5.69887180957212,0.75,13.589295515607));
#448=CARTESIAN_POINT('',(-5.29432853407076,0.75,13.7113138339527));
#449=CARTESIAN_POINT('',(-4.47763909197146,0.75,13.9206164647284));
#450=CARTESIAN_POINT('',(-4.06552036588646,0.75,14.0080072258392));
#451=CARTESIAN_POINT('',(-3.44313498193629,0.75,14.1131515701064));
#452=CARTESIAN_POINT('',(-3.2349769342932,0.75,14.1438756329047));
#453=CARTESIAN_POINT('',(-2.81757605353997,0.75,14.1967187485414));
#454=CARTESIAN_POINT('',(-2.60833331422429,0.75,14.2188385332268));
#455=CARTESIAN_POINT('',(-2.19967651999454,0.75,14.2537079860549));
#456=CARTESIAN_POINT('',(-2.00029743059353,0.75,14.2668729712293));
#457=CARTESIAN_POINT('',(-1.60124974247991,0.75,14.2858621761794));
#458=CARTESIAN_POINT('',(-1.40158124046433,0.75,14.291688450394));
#459=CARTESIAN_POINT('',(-1.10202038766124,0.75,14.2957506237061));
#460=CARTESIAN_POINT('',(-1.00214989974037,0.75,14.2963250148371));
#461=CARTESIAN_POINT('',(-0.80240752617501,0.75,14.296275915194));
#462=CARTESIAN_POINT('',(-0.702535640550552,0.75,14.2956523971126));
#463=CARTESIAN_POINT('',(-0.502793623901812,0.75,14.2938528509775));
#464=CARTESIAN_POINT('',(-0.402923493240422,0.75,14.2926767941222));
#465=CARTESIAN_POINT('',(-0.2031790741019,0.75,14.290858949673));
#466=CARTESIAN_POINT('',(-0.103304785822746,0.75,14.2902171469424));
#467=CARTESIAN_POINT('',(-0.00228680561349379,0.75,14.2902034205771));
#468=CARTESIAN_POINT('',(-0.0011434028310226,0.75,14.2902033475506));
#469=CARTESIAN_POINT('',(0.,0.75,14.2902033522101));
#470=B_SPLINE_CURVE_WITH_KNOTS('',3,(#260,#261,#262,#263,#264,#265,#266,#267,#268,#269,#270,
#271,#272,#273,#274,#275,#276,#277,#278,#279,#280,#281,#282,#283,#284,#285,#286,#287,#288,#289,
#290,#291,#292,#293,#294,#295,#296,#297,#298,#299,#300,#301,#302,#303,#304,#305,#306,#307,#308,
#309,#310,#311,#312,#313,#314,#315,#316,#317,#318,#319,#320,#321,#322,#323,#324,#325,#326,#327,
#328,#329,#330,#331,#332,#333,#334,#335,#336,#337,#338,#339,#340,#341,#342,#343,#344,#345,#346,
#347,#348,#349,#350,#351,#352,#353,#354,#355,#356,#357,#358,#359,#360,#361,#362,#363,#364,#365,
#366,#367,#368,#369,#370,#371,#372,#373,#374,#375,#376,#377,#378,#379,#380,#381,#382,#383,#384,
#385,#386,#387,#388,#389,#390,#391,#392,#393,#394,#395,#396,#397,#398,#399,#400,#401,#402,#403,
#404,#405,#406,#407,#408,#409,#410,#411,#412,#413,#414,#415,#416,#417,#418,#419,#420,#421,#422,
#423,#424,#425,#426,#427,#428,#429,#430,#431,#432,#433,#434,#435,#436,#437,#438,#439,#440,#441,
#442,#443,#444,#445,#446,#447,#448,#449,#450,#451,#452,#453,#454,#455,#456,#457,#458,#459,#460,
#461,#462,#463,#464,#465,#466,#467,#468,#469),.UNSPECIFIED.,.T.,.F.,(4,2,2,2,2,2,2,2,2,2,2,2,2,
2,2,2,2,2,2,2,2,2,2,2,2,2,2,2,2,2,2,2,2,2,2,2,2,2,2,2,2,2,2,2,2,2,2,2,2,2,2,2,2,2,2,2,2,2,2,2,2,
2,2,2,2,2,2,2,2,2,2,2,2,2,2,2,2,2,2,2,2,2,2,2,2,2,2,2,2,2,2,2,2,2,2,2,2,2,2,2,2,2,2,2,4),(0.,
0.187528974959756,0.375059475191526,0.562612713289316,0.750176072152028,1.12702058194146,
1.50386126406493,2.25744605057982,3.0113216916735,3.76542063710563,5.034211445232,
6.30329476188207,7.57468202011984,8.84601256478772,10.1147343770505,11.3834642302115,
12.651396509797,13.9193246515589,15.1832276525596,16.4471278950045,17.7112498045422,
18.9753723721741,20.2389548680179,21.5025366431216,22.7660200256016,24.029503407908,
25.292826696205,26.556149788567,27.8196611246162,29.0831733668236,30.3469054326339,
31.6106354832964,32.873710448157,34.1367906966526,35.3992097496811,36.6616067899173,
37.9261037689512,39.1906799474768,40.4575075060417,41.7240934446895,42.9845067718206,
44.2456138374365,45.5312858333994,46.1733270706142,46.8153976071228,47.4624625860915,
48.109421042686,48.4335381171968,48.7576675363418,49.081855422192,49.2439386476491,
49.4060209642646,49.613060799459,49.8201040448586,50.0271620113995,50.2342180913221,
50.6482198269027,51.0622067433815,51.4751859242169,51.8881756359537,52.7144278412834,
53.5328045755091,54.3510581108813,55.1710864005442,55.9911062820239,57.2531212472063,
58.5138117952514,59.7812913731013,61.0492009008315,62.3150813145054,63.580828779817,
64.8441428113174,66.1074928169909,67.3707605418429,68.6340186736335,69.8980817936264,
71.1621480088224,72.425728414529,73.6893073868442,74.9526302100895,76.2159531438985,
77.4792630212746,78.7425729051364,80.0060654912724,81.2695585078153,82.5332231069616,
83.7968872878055,85.060080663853,86.3232736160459,87.5861136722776,88.8489546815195,
90.1132653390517,91.3775683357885,92.6436748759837,93.909843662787,95.1720893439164,
95.8031823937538,96.4342217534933,97.0335229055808,97.632656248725,97.932266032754,
98.2318826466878,98.5315148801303,98.831138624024,98.8345688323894),.UNSPECIFIED.);
#471=CARTESIAN_POINT('',(3.8,0.75,14.0520967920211));
#472=VERTEX_POINT('',#471);
#473=EDGE_CURVE('E498',#257,#472,#470,.T.);
#474=ORIENTED_EDGE('',*,*,#473,.T.);
#475=CARTESIAN_POINT('',(3.7998,0.749999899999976,14.0521326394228));
#476=CARTESIAN_POINT('',(3.81114880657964,0.750020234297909,14.0500982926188));
#477=CARTESIAN_POINT('',(3.82250108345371,0.749057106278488,14.0480843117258));
#478=CARTESIAN_POINT('',(3.84489426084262,0.745224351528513,14.0441543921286));
#479=CARTESIAN_POINT('',(3.85593522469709,0.742355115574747,14.0422384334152));
#480=CARTESIAN_POINT('',(3.87740011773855,0.734767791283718,14.0385596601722));
#481=CARTESIAN_POINT('',(3.88782359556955,0.730048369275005,14.0367969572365));
#482=CARTESIAN_POINT('',(3.90773653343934,0.718887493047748,14.0334807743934));
#483=CARTESIAN_POINT('',(3.91722631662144,0.712446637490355,14.0319272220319));
#484=CARTESIAN_POINT('',(3.93490505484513,0.698084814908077,14.0290917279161));
#485=CARTESIAN_POINT('',(3.9431055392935,0.690178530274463,14.027807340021));
#486=CARTESIAN_POINT('',(3.95806529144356,0.673063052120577,14.025533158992));
#487=CARTESIAN_POINT('',(3.96482436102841,0.663853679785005,14.0245434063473));
#488=CARTESIAN_POINT('',(3.97659283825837,0.644555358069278,14.0229052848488));
#489=CARTESIAN_POINT('',(3.98162854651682,0.634482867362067,14.0222516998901));
#490=CARTESIAN_POINT('',(3.98994131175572,0.613624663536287,14.0212843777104));
#491=CARTESIAN_POINT('',(3.99321964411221,0.602839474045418,14.0209703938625));
#492=CARTESIAN_POINT('',(3.99704991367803,0.584948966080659,14.0207435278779));
#493=CARTESIAN_POINT('',(3.99816189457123,0.577959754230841,14.0207251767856));
#494=CARTESIAN_POINT('',(3.99964030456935,0.563913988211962,14.0208265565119));
#495=CARTESIAN_POINT('',(4.00000779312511,0.556857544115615,14.0209460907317));
#496=CARTESIAN_POINT('',(3.9999999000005,0.549800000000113,14.0211342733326));
#497=B_SPLINE_CURVE_WITH_KNOTS('',3,(#475,#476,#477,#478,#479,#480,#481,#482,#483,#484,#485,
#486,#487,#488,#489,#490,#491,#492,#493,#494,#495,#496),.UNSPECIFIED.,.F.,.F.,(4,2,2,2,2,2,2,2,
2,2,4),(0.,0.0345466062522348,0.0690861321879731,0.103650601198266,0.138203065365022,
0.172426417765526,0.206654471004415,0.240334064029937,0.273989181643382,0.295182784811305,
0.316346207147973),.UNSPECIFIED.);
#498=CARTESIAN_POINT('',(4.,0.55,14.02112896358));
#499=VERTEX_POINT('',#498);
#500=EDGE_CURVE('E505',#472,#499,#497,.T.);
#501=ORIENTED_EDGE('',*,*,#500,.T.);
#502=CARTESIAN_POINT('',(4.,0.,14.028388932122));
#503=CARTESIAN_POINT('',(4.,-0.339153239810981,14.0283961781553));
#504=CARTESIAN_POINT('',(4.,-0.678323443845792,14.0201840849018));
#505=CARTESIAN_POINT('',(4.,-1.35574448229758,13.9866878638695));
#506=CARTESIAN_POINT('',(4.,-1.69399552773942,13.9614080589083));
#507=CARTESIAN_POINT('',(4.,-2.36814839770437,13.8923714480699));
#508=CARTESIAN_POINT('',(4.,-2.7040529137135,13.8486414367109));
#509=CARTESIAN_POINT('',(4.,-3.37274568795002,13.7413643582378));
#510=CARTESIAN_POINT('',(4.,-3.70553346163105,13.6778142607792));
#511=CARTESIAN_POINT('',(4.,-4.45788889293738,13.5095576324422));
#512=CARTESIAN_POINT('',(4.,-4.87602372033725,13.3983308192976));
#513=CARTESIAN_POINT('',(4.,-5.70161656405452,13.1413580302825));
#514=CARTESIAN_POINT('',(4.,-6.10907328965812,12.9956079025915));
#515=CARTESIAN_POINT('',(4.,-6.91043852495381,12.6696375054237));
#516=CARTESIAN_POINT('',(4.,-7.30433371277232,12.4893844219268));
#517=CARTESIAN_POINT('',(4.,-8.07498519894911,12.0953512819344));
#518=CARTESIAN_POINT('',(4.,-8.45174183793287,11.8815718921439));
#519=CARTESIAN_POINT('',(4.,-9.18281763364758,11.4232419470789));
#520=CARTESIAN_POINT('',(4.,-9.53726091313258,11.1788894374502));
#521=CARTESIAN_POINT('',(4.,-10.2233955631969,10.6600773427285));
#522=CARTESIAN_POINT('',(4.,-10.5550867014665,10.3856174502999));
#523=CARTESIAN_POINT('',(4.,-11.1930381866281,9.8086212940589));
#524=CARTESIAN_POINT('',(4.,-11.4993002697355,9.50608695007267));
#525=CARTESIAN_POINT('',(4.,-12.0839658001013,8.87520844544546));
#526=CARTESIAN_POINT('',(4.,-12.3623701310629,8.54686510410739));
#527=CARTESIAN_POINT('',(4.,-12.8784698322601,7.8806109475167));
#528=CARTESIAN_POINT('',(4.,-13.1173543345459,7.54362037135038));
#529=CARTESIAN_POINT('',(4.,-13.5656684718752,6.85059247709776));
#530=CARTESIAN_POINT('',(4.,-13.7750989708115,6.49455571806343));
#531=CARTESIAN_POINT('',(4.,-14.1629376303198,5.76604322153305));
#532=CARTESIAN_POINT('',(4.,-14.3413507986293,5.39357014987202));
#533=CARTESIAN_POINT('',(4.,-14.6658865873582,4.63480988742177));
#534=CARTESIAN_POINT('',(4.,-14.8120091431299,4.24852266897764));
#535=CARTESIAN_POINT('',(4.,-15.0699099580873,3.46788913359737));
#536=CARTESIAN_POINT('',(4.,-15.1819394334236,3.07362578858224));
#537=CARTESIAN_POINT('',(4.,-15.3723250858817,2.2770527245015));
#538=CARTESIAN_POINT('',(4.,-15.4506814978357,1.87474306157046));
#539=CARTESIAN_POINT('',(4.,-15.5731575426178,1.06492658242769));
#540=CARTESIAN_POINT('',(4.,-15.617275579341,0.657419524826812));
#541=CARTESIAN_POINT('',(4.,-15.6709496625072,-0.159864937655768));
#542=CARTESIAN_POINT('',(4.,-15.6805056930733,-0.569642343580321));
#543=CARTESIAN_POINT('',(4.,-15.665001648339,-1.38774900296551));
#544=CARTESIAN_POINT('',(4.,-15.6400084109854,-1.7960795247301));
#545=CARTESIAN_POINT('',(4.,-15.5557048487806,-2.60918184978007));
#546=CARTESIAN_POINT('',(4.,-15.4963945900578,-3.01395365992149));
#547=CARTESIAN_POINT('',(4.,-15.3438918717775,-3.8170229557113));
#548=CARTESIAN_POINT('',(4.,-15.2507026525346,-4.21532105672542));
#549=CARTESIAN_POINT('',(4.,-15.0311128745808,-5.00265431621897));
#550=CARTESIAN_POINT('',(4.,-14.9047123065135,-5.39168947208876));
#551=CARTESIAN_POINT('',(4.,-14.619619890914,-6.15771427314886));
#552=CARTESIAN_POINT('',(4.,-14.4609300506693,-6.53470466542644));
#553=CARTESIAN_POINT('',(4.,-14.112398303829,-7.27399825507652));
#554=CARTESIAN_POINT('',(4.,-13.9225564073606,-7.63630145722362));
#555=CARTESIAN_POINT('',(4.,-13.5130367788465,-8.34375702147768));
#556=CARTESIAN_POINT('',(4.,-13.2933514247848,-8.68890497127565));
#557=CARTESIAN_POINT('',(4.,-12.825767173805,-9.35952806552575));
#558=CARTESIAN_POINT('',(4.,-12.5778682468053,-9.68500318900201));
#559=CARTESIAN_POINT('',(4.,-12.0550681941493,-10.3147088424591));
#560=CARTESIAN_POINT('',(4.,-11.7801085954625,-10.6188908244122));
#561=CARTESIAN_POINT('',(4.,-11.2056412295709,-11.2031141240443));
#562=CARTESIAN_POINT('',(4.,-10.9061334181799,-11.4831553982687));
#563=CARTESIAN_POINT('',(4.,-10.2849635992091,-12.0170071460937));
#564=CARTESIAN_POINT('',(4.,-9.96331753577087,-12.2708361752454));
#565=CARTESIAN_POINT('',(4.,-9.30001359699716,-12.7508263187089));
#566=CARTESIAN_POINT('',(4.,-8.95835585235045,-12.9769876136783));
#567=CARTESIAN_POINT('',(4.,-8.25506085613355,-13.4017235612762));
#568=CARTESIAN_POINT('',(4.,-7.89330122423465,-13.6000955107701));
#569=CARTESIAN_POINT('',(4.,-7.1546361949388,-13.9662854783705));
#570=CARTESIAN_POINT('',(4.,-6.77773047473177,-14.1341028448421));
#571=CARTESIAN_POINT('',(4.,-6.01113338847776,-14.4386630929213));
#572=CARTESIAN_POINT('',(4.,-5.62142902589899,-14.5753731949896));
#573=CARTESIAN_POINT('',(4.,-4.83241304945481,-14.817363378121));
#574=CARTESIAN_POINT('',(4.,-4.4331021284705,-14.9226457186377));
#575=CARTESIAN_POINT('',(4.,-3.77164652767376,-15.0703302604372));
#576=CARTESIAN_POINT('',(4.,-3.51147362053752,-15.1217585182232));
#577=CARTESIAN_POINT('',(4.,-2.98899804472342,-15.2123395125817));
#578=CARTESIAN_POINT('',(4.,-2.7266952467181,-15.2514914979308));
#579=CARTESIAN_POINT('',(4.,-1.93724201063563,-15.3514509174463));
#580=CARTESIAN_POINT('',(4.,-1.40777675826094,-15.3947116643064));
#581=CARTESIAN_POINT('',(4.,-0.612198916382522,-15.4285188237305));
#582=CARTESIAN_POINT('',(4.,-0.346571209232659,-15.4345998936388));
#583=CARTESIAN_POINT('',(4.,0.184756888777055,-15.4366600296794));
#584=CARTESIAN_POINT('',(4.,0.450457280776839,-15.4326389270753));
#585=CARTESIAN_POINT('',(4.,0.981374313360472,-15.4142959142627));
#586=CARTESIAN_POINT('',(4.,1.24659112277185,-15.3999788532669));
#587=CARTESIAN_POINT('',(4.,1.7762314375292,-15.3604541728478));
#588=CARTESIAN_POINT('',(4.,2.04065492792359,-15.3352463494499));
#589=CARTESIAN_POINT('',(4.,2.52470132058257,-15.2783376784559));
#590=CARTESIAN_POINT('',(4.,2.74453002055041,-15.248390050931));
#591=CARTESIAN_POINT('',(4.,3.18285214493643,-15.1800456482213));
#592=CARTESIAN_POINT('',(4.,3.40134562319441,-15.1416492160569));
#593=CARTESIAN_POINT('',(4.,4.05419633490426,-15.0133381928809));
#594=CARTESIAN_POINT('',(4.,4.48606739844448,-14.9102854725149));
#595=CARTESIAN_POINT('',(4.,5.33835432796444,-14.6682914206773));
#596=CARTESIAN_POINT('',(4.,5.75879820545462,-14.5294486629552));
#597=CARTESIAN_POINT('',(4.,6.58609234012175,-14.2156839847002));
#598=CARTESIAN_POINT('',(4.,6.99294114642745,-14.0407582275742));
#599=CARTESIAN_POINT('',(4.,7.79138450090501,-13.6547019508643));
#600=CARTESIAN_POINT('',(4.,8.18290123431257,-13.4434103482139));
#601=CARTESIAN_POINT('',(4.,8.94537896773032,-12.9865110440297));
#602=CARTESIAN_POINT('',(4.,9.31634014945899,-12.7409036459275));
#603=CARTESIAN_POINT('',(4.,10.0350527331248,-12.2167860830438));
#604=CARTESIAN_POINT('',(4.,10.3827705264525,-11.9382298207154));
#605=CARTESIAN_POINT('',(4.,11.0514362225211,-11.350662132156));
#606=CARTESIAN_POINT('',(4.,11.3723853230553,-11.0416520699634));
#607=CARTESIAN_POINT('',(4.,11.9642331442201,-10.4173353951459));
#608=CARTESIAN_POINT('',(4.,12.2370447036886,-10.1038391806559));
#609=CARTESIAN_POINT('',(4.,12.7549508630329,-9.4547474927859));
#610=CARTESIAN_POINT('',(4.,13.0000469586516,-9.11915321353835));
#611=CARTESIAN_POINT('',(4.,13.4605522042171,-8.42850547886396));
#612=CARTESIAN_POINT('',(4.,13.67598107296,-8.07346517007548));
#613=CARTESIAN_POINT('',(4.,14.0757477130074,-7.34628666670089));
#614=CARTESIAN_POINT('',(4.,14.2600853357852,-6.97414839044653));
#615=CARTESIAN_POINT('',(4.,14.5943069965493,-6.21997693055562));
#616=CARTESIAN_POINT('',(4.,14.7445728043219,-5.83811287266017));
#617=CARTESIAN_POINT('',(4.,15.0123145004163,-5.06306047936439));
#618=CARTESIAN_POINT('',(4.,15.1297907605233,-4.669872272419));
#619=CARTESIAN_POINT('',(4.,15.3311166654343,-3.87492033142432));
#620=CARTESIAN_POINT('',(4.,15.4149615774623,-3.47315539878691));
#621=CARTESIAN_POINT('',(4.,15.5483930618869,-2.66397544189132));
#622=CARTESIAN_POINT('',(4.,15.5979796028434,-2.25656041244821));
#623=CARTESIAN_POINT('',(4.,15.6624394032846,-1.44020146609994));
#624=CARTESIAN_POINT('',(4.,15.6774144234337,-1.03126558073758));
#625=CARTESIAN_POINT('',(4.,15.6728420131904,-0.213587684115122));
#626=CARTESIAN_POINT('',(4.,15.653294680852,0.19515432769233));
#627=CARTESIAN_POINT('',(4.,15.5798200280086,1.00952109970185));
#628=CARTESIAN_POINT('',(4.,15.5258939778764,1.41514597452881));
#629=CARTESIAN_POINT('',(4.,15.3840519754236,2.22040863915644));
#630=CARTESIAN_POINT('',(4.,15.2961360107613,2.62004642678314));
#631=CARTESIAN_POINT('',(4.,15.0869932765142,3.41032437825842));
#632=CARTESIAN_POINT('',(4.,14.9657808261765,3.8009683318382));
#633=CARTESIAN_POINT('',(4.,14.6909025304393,4.57066557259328));
#634=CARTESIAN_POINT('',(4.,14.5372367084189,4.94971886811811));
#635=CARTESIAN_POINT('',(4.,14.198563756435,5.6935427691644));
#636=CARTESIAN_POINT('',(4.,14.0135574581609,6.05831375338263));
#637=CARTESIAN_POINT('',(4.,13.6135344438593,6.77101064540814));
#638=CARTESIAN_POINT('',(4.,13.3985177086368,7.11893654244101));
#639=CARTESIAN_POINT('',(4.,12.9397392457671,7.79592064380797));
#640=CARTESIAN_POINT('',(4.,12.695942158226,8.12495488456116));
#641=CARTESIAN_POINT('',(4.,12.1815798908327,8.76138756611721));
#642=CARTESIAN_POINT('',(4.,11.91101469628,9.068785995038));
#643=CARTESIAN_POINT('',(4.,11.3450384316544,9.65985804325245));
#644=CARTESIAN_POINT('',(4.,11.049624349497,9.94352877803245));
#645=CARTESIAN_POINT('',(4.,10.4361166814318,10.4851767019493));
#646=CARTESIAN_POINT('',(4.,10.1180230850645,10.7431538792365));
#647=CARTESIAN_POINT('',(4.,9.45975657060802,11.2329803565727));
#648=CARTESIAN_POINT('',(4.,9.11947790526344,11.4646875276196));
#649=CARTESIAN_POINT('',(4.,8.42081797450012,11.8989645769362));
#650=CARTESIAN_POINT('',(4.,8.06243669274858,12.1015344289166));
#651=CARTESIAN_POINT('',(4.,7.33043234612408,12.476268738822));
#652=CARTESIAN_POINT('',(4.,6.95681985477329,12.6484538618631));
#653=CARTESIAN_POINT('',(4.,6.19684574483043,12.961845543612));
#654=CARTESIAN_POINT('',(4.,5.81048403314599,13.1030518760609));
#655=CARTESIAN_POINT('',(4.,4.98307663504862,13.3686004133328));
#656=CARTESIAN_POINT('',(4.,4.54082134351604,13.4891802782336));
#657=CARTESIAN_POINT('',(4.,3.64769934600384,13.6923551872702));
#658=CARTESIAN_POINT('',(4.,3.19683149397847,13.774945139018));
#659=CARTESIAN_POINT('',(4.,2.28933102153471,13.9045907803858));
#660=CARTESIAN_POINT('',(4.,1.83269032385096,13.9515893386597));
#661=CARTESIAN_POINT('',(4.,1.14623014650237,13.9979727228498));
#662=CARTESIAN_POINT('',(4.,0.917138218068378,14.0094147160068));
#663=CARTESIAN_POINT('',(4.,0.458700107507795,14.0246202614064));
#664=CARTESIAN_POINT('',(4.,0.229353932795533,14.0283840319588));
#665=CARTESIAN_POINT('',(4.,0.,14.028388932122));
#666=B_SPLINE_CURVE_WITH_KNOTS('',3,(#502,#503,#504,#505,#506,#507,#508,#509,#510,#511,#512,
#513,#514,#515,#516,#517,#518,#519,#520,#521,#522,#523,#524,#525,#526,#527,#528,#529,#530,#531,
#532,#533,#534,#535,#536,#537,#538,#539,#540,#541,#542,#543,#544,#545,#546,#547,#548,#549,#550,
#551,#552,#553,#554,#555,#556,#557,#558,#559,#560,#561,#562,#563,#564,#565,#566,#567,#568,#569,
#570,#571,#572,#573,#574,#575,#576,#577,#578,#579,#580,#581,#582,#583,#584,#585,#586,#587,#588,
#589,#590,#591,#592,#593,#594,#595,#596,#597,#598,#599,#600,#601,#602,#603,#604,#605,#606,#607,
#608,#609,#610,#611,#612,#613,#614,#615,#616,#617,#618,#619,#620,#621,#622,#623,#624,#625,#626,
#627,#628,#629,#630,#631,#632,#633,#634,#635,#636,#637,#638,#639,#640,#641,#642,#643,#644,#645,
#646,#647,#648,#649,#650,#651,#652,#653,#654,#655,#656,#657,#658,#659,#660,#661,#662,#663,#664,
#665),.UNSPECIFIED.,.T.,.F.,(4,2,2,2,2,2,2,2,2,2,2,2,2,2,2,2,2,2,2,2,2,2,2,2,2,2,2,2,2,2,2,2,2,
2,2,2,2,2,2,2,2,2,2,2,2,2,2,2,2,2,2,2,2,2,2,2,2,2,2,2,2,2,2,2,2,2,2,2,2,2,2,2,2,2,2,2,2,2,2,2,2,
4),(0.,1.01738294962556,2.03450831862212,3.05016161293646,4.06597026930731,5.36249424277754,
6.6591742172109,7.95709358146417,9.25498713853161,10.5448707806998,11.8347675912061,
13.1245762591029,14.4143439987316,15.6520836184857,16.8897869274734,18.1272902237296,
19.3647959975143,20.5929491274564,21.8210936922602,23.0492955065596,24.2774978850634,
25.5033275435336,26.7291548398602,27.9548649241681,29.1805753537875,30.4062096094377,
31.6318434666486,32.8577909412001,34.0837397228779,35.3123982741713,36.5410590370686,
37.7688439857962,38.9966209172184,40.2329329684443,41.4692713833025,42.7069066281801,
43.9444528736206,44.7397910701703,45.5351779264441,47.1266553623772,47.9236225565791,
48.7206030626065,49.5172084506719,50.3138287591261,50.9792441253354,51.6446324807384,
52.9749769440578,54.301695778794,55.6285557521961,56.9614518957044,58.2943362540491,
59.6291079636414,60.9638199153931,62.2090674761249,63.4542478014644,64.6985964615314,
65.9429510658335,67.1725857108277,68.4022064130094,69.6320000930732,70.8617949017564,
72.0879693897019,73.3141403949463,74.5402660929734,75.7663922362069,76.9919919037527,
78.2175906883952,79.4431569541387,80.6687240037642,81.8958127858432,83.1229022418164,
84.3501406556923,85.5773796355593,86.8109699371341,88.0445613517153,89.2773105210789,
90.510068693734,91.8834796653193,93.2570746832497,94.632869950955,95.3208993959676,
96.0089092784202),.UNSPECIFIED.);
#667=CARTESIAN_POINT('',(4.,-0.55,14.0211289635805));
#668=VERTEX_POINT('',#667);
#669=EDGE_CURVE('E513',#499,#668,#666,.T.);
#670=ORIENTED_EDGE('',*,*,#669,.T.);
#671=CARTESIAN_POINT('',(3.99999989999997,-0.5498,14.0211342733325));
#672=CARTESIAN_POINT('',(4.00002120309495,-0.560882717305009,14.0208370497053));
#673=CARTESIAN_POINT('',(3.99910147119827,-0.571967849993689,14.0207119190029));
#674=CARTESIAN_POINT('',(3.99545102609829,-0.59382219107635,14.0208010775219));
#675=CARTESIAN_POINT('',(3.99272233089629,-0.604591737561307,14.021014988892));
#676=CARTESIAN_POINT('',(3.98552323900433,-0.625524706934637,14.0217769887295));
#677=CARTESIAN_POINT('',(3.98105209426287,-0.635687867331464,14.0223252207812));
#678=CARTESIAN_POINT('',(3.97050578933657,-0.655118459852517,14.0237373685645));
#679=CARTESIAN_POINT('',(3.96443078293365,-0.664385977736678,14.0246012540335));
#680=CARTESIAN_POINT('',(3.95082544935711,-0.681812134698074,14.0266217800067));
#681=CARTESIAN_POINT('',(3.94328885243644,-0.689965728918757,14.0277796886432));
#682=CARTESIAN_POINT('',(3.92699598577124,-0.704900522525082,14.030350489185));
#683=CARTESIAN_POINT('',(3.91823946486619,-0.711681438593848,14.0317634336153));
#684=CARTESIAN_POINT('',(3.89962640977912,-0.723780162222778,14.0348229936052));
#685=CARTESIAN_POINT('',(3.88975612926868,-0.729076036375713,14.0364726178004));
#686=CARTESIAN_POINT('',(3.86929754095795,-0.73794157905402,14.0399411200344));
#687=CARTESIAN_POINT('',(3.858709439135,-0.741511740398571,14.0417599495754));
#688=CARTESIAN_POINT('',(3.84003688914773,-0.746119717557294,14.0450054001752));
#689=CARTESIAN_POINT('',(3.83204943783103,-0.747581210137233,14.046405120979));
#690=CARTESIAN_POINT('',(3.81597474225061,-0.749525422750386,14.0492439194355));
#691=CARTESIAN_POINT('',(3.80788765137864,-0.750009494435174,14.0506829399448));
#692=CARTESIAN_POINT('',(3.79980000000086,-0.749999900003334,14.052132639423));
#693=B_SPLINE_CURVE_WITH_KNOTS('',3,(#671,#672,#673,#674,#675,#676,#677,#678,#679,#680,#681,
#682,#683,#684,#685,#686,#687,#688,#689,#690,#691,#692),.UNSPECIFIED.,.F.,.F.,(4,2,2,2,2,2,2,2,
2,2,4),(0.,0.0332152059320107,0.0663934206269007,0.0995858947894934,0.132775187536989,
0.166110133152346,0.199451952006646,0.233262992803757,0.267064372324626,0.291727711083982,
0.316356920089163),.UNSPECIFIED.);
#694=CARTESIAN_POINT('',(3.8,-0.75,14.0520967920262));
#695=VERTEX_POINT('',#694);
#696=EDGE_CURVE('E520',#668,#695,#693,.T.);
#697=ORIENTED_EDGE('',*,*,#696,.T.);
#698=CARTESIAN_POINT('',(0.,-0.75,14.2902033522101));
#699=CARTESIAN_POINT('',(-0.062509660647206,-0.75,14.2902036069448));
#700=CARTESIAN_POINT('',(-0.125019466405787,-0.75,14.2904360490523));
#701=CARTESIAN_POINT('',(-0.250036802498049,-0.75,14.291252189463));
#702=CARTESIAN_POINT('',(-0.312544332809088,-0.75,14.2918358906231));
#703=CARTESIAN_POINT('',(-0.437565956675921,-0.75,14.2930988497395));
#704=CARTESIAN_POINT('',(-0.500080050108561,-0.75,14.2937781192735));
#705=CARTESIAN_POINT('',(-0.625113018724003,-0.75,14.2949804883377));
#706=CARTESIAN_POINT('',(-0.687631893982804,-0.75,14.2955035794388));
#707=CARTESIAN_POINT('',(-0.875766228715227,-0.75,14.2965328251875));
#708=CARTESIAN_POINT('',(-1.00138686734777,-0.75,14.2964891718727));
#709=CARTESIAN_POINT('',(-1.25260493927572,-0.75,14.2940460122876));
#710=CARTESIAN_POINT('',(-1.37820237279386,-0.75,14.2916465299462));
#711=CARTESIAN_POINT('',(-1.75485708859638,-0.75,14.2803277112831));
#712=CARTESIAN_POINT('',(-2.00580900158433,-0.75,14.2672884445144));
#713=CARTESIAN_POINT('',(-2.50689880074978,-0.75,14.2291477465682));
#714=CARTESIAN_POINT('',(-2.75703633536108,-0.75,14.2040416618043));
#715=CARTESIAN_POINT('',(-3.25583549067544,-0.75,14.1415504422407));
#716=CARTESIAN_POINT('',(-3.5044966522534,-0.75,14.1041616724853));
#717=CARTESIAN_POINT('',(-4.16871083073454,-0.75,13.9873107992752));
#718=CARTESIAN_POINT('',(-4.58233519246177,-0.75,13.8965497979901));
#719=CARTESIAN_POINT('',(-5.40052634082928,-0.75,13.6805066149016));
#720=CARTESIAN_POINT('',(-5.80509101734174,-0.75,13.5552164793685));
#721=CARTESIAN_POINT('',(-6.60293944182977,-0.75,13.2706758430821));
#722=CARTESIAN_POINT('',(-6.99620137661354,-0.75,13.1113641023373));
#723=CARTESIAN_POINT('',(-7.76780860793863,-0.75,12.760031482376));
#724=CARTESIAN_POINT('',(-8.14615456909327,-0.75,12.5680120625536));
#725=CARTESIAN_POINT('',(-8.88446706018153,-0.75,12.1530468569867));
#726=CARTESIAN_POINT('',(-9.2444697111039,-0.75,11.9301653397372));
#727=CARTESIAN_POINT('',(-9.9443450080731,-0.75,11.4547620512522));
#728=CARTESIAN_POINT('',(-10.2842175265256,-0.75,11.2022400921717));
#729=CARTESIAN_POINT('',(-10.9411846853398,-0.75,10.6695279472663));
#730=CARTESIAN_POINT('',(-11.2582935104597,-0.75,10.3893552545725));
#731=CARTESIAN_POINT('',(-11.867695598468,-0.75,9.80321084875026));
#732=CARTESIAN_POINT('',(-12.1599889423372,-0.75,9.49723921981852));
#733=CARTESIAN_POINT('',(-12.7167806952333,-0.75,8.86269415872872));
#734=CARTESIAN_POINT('',(-12.9813643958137,-0.75,8.53419556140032));
#735=CARTESIAN_POINT('',(-13.4819097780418,-0.75,7.85607214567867));
#736=CARTESIAN_POINT('',(-13.7178715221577,-0.75,7.50644737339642));
#737=CARTESIAN_POINT('',(-14.1595322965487,-0.75,6.78849443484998));
#738=CARTESIAN_POINT('',(-14.3652260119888,-0.75,6.42016299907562));
#739=CARTESIAN_POINT('',(-14.7448367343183,-0.75,5.66747355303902));
#740=CARTESIAN_POINT('',(-14.9187537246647,-0.75,5.28311553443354));
#741=CARTESIAN_POINT('',(-15.2335050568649,-0.75,4.50127546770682));
#742=CARTESIAN_POINT('',(-15.3743535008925,-0.75,4.10379909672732));
#743=CARTESIAN_POINT('',(-15.6220611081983,-0.75,3.29839291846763));
#744=CARTESIAN_POINT('',(-15.7289202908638,-0.75,2.89046311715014));
#745=CARTESIAN_POINT('',(-15.9078821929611,-0.75,2.06708280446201));
#746=CARTESIAN_POINT('',(-15.9799876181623,-0.75,1.65163288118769));
#747=CARTESIAN_POINT('',(-16.0889414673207,-0.75,0.816135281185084));
#748=CARTESIAN_POINT('',(-16.1257898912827,-0.75,0.396087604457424));
#749=CARTESIAN_POINT('',(-16.163965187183,-0.75,-0.445565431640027));
#750=CARTESIAN_POINT('',(-16.1652965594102,-0.75,-0.867170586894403));
#751=CARTESIAN_POINT('',(-16.1324397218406,-0.75,-1.7089944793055));
#752=CARTESIAN_POINT('',(-16.0982515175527,-0.75,-2.12921321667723));
#753=CARTESIAN_POINT('',(-15.994590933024,-0.75,-2.96533956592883));
#754=CARTESIAN_POINT('',(-15.9251132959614,-0.75,-3.38124652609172));
#755=CARTESIAN_POINT('',(-15.751365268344,-0.75,-4.20572862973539));
#756=CARTESIAN_POINT('',(-15.6470948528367,-0.75,-4.61430376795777));
#757=CARTESIAN_POINT('',(-15.4044819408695,-0.75,-5.42128714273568));
#758=CARTESIAN_POINT('',(-15.2661335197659,-0.75,-5.8196935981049));
#759=CARTESIAN_POINT('',(-14.9563586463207,-0.75,-6.6034316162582));
#760=CARTESIAN_POINT('',(-14.7849322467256,-0.75,-6.9887631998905));
#761=CARTESIAN_POINT('',(-14.410318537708,-0.75,-7.74341593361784));
#762=CARTESIAN_POINT('',(-14.2071477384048,-0.75,-8.11274527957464));
#763=CARTESIAN_POINT('',(-13.7704245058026,-0.75,-8.83298393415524));
#764=CARTESIAN_POINT('',(-13.5368719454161,-0.75,-9.18389316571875));
#765=CARTESIAN_POINT('',(-13.0411762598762,-0.75,-9.86461934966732));
#766=CARTESIAN_POINT('',(-12.7790481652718,-0.75,-10.1944472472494));
#767=CARTESIAN_POINT('',(-12.2279683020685,-0.75,-10.8308662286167));
#768=CARTESIAN_POINT('',(-11.9390170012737,-0.75,-11.1374577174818));
#769=CARTESIAN_POINT('',(-11.3358371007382,-0.75,-11.7257264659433));
#770=CARTESIAN_POINT('',(-11.0215672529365,-0.75,-12.0073614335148));
#771=CARTESIAN_POINT('',(-10.3703891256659,-0.75,-12.5431585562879));
#772=CARTESIAN_POINT('',(-10.0334794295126,-0.75,-12.7973189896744));
#773=CARTESIAN_POINT('',(-9.33882156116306,-0.75,-13.2767706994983));
#774=CARTESIAN_POINT('',(-8.98103735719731,-0.75,-13.5020097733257));
#775=CARTESIAN_POINT('',(-8.24780759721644,-0.75,-13.9214489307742));
#776=CARTESIAN_POINT('',(-7.87236542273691,-0.75,-14.1156549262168));
#777=CARTESIAN_POINT('',(-7.10830459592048,-0.75,-14.4708441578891));
#778=CARTESIAN_POINT('',(-6.71975907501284,-0.75,-14.6319846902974));
#779=CARTESIAN_POINT('',(-5.93032689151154,-0.75,-14.9212008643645));
#780=CARTESIAN_POINT('',(-5.52943355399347,-0.75,-15.049258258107));
#781=CARTESIAN_POINT('',(-4.71037120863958,-0.75,-15.2735305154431));
#782=CARTESIAN_POINT('',(-4.29201779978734,-0.75,-15.3690765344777));
#783=CARTESIAN_POINT('',(-3.65997311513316,-0.75,-15.485449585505));
#784=CARTESIAN_POINT('',(-3.44867138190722,-0.75,-15.5197366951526));
#785=CARTESIAN_POINT('',(-3.02478880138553,-0.75,-15.5793924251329));
#786=CARTESIAN_POINT('',(-2.81220789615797,-0.75,-15.6047606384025));
#787=CARTESIAN_POINT('',(-2.38452719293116,-0.75,-15.6468286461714));
#788=CARTESIAN_POINT('',(-2.16942066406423,-0.75,-15.6634594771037));
#789=CARTESIAN_POINT('',(-1.73875062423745,-0.75,-15.6880212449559));
#790=CARTESIAN_POINT('',(-1.5231871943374,-0.75,-15.6959536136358));
#791=CARTESIAN_POINT('',(-1.19954465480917,-0.75,-15.7021388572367));
#792=CARTESIAN_POINT('',(-1.09150789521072,-0.75,-15.7032466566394));
#793=CARTESIAN_POINT('',(-0.875426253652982,-0.75,-15.7039178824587));
#794=CARTESIAN_POINT('',(-0.767381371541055,-0.75,-15.7034812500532));
#795=CARTESIAN_POINT('',(-0.551281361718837,-0.75,-15.7017790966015));
#796=CARTESIAN_POINT('',(-0.443226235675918,-0.75,-15.7005134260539));
#797=CARTESIAN_POINT('',(-0.281143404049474,-0.75,-15.6989476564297));
#798=CARTESIAN_POINT('',(-0.227117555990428,-0.75,-15.698481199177));
#799=CARTESIAN_POINT('',(-0.119064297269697,-0.75,-15.6978197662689));
#800=CARTESIAN_POINT('',(-0.0650368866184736,-0.75,-15.6976247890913));
#801=CARTESIAN_POINT('',(0.05800398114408,-0.75,-15.6975761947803));
#802=CARTESIAN_POINT('',(0.127017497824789,-0.75,-15.6978322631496));
#803=CARTESIAN_POINT('',(0.265042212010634,-0.75,-15.6987649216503));
#804=CARTESIAN_POINT('',(0.334053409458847,-0.75,-15.6994415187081));
#805=CARTESIAN_POINT('',(0.47207998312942,-0.75,-15.7008610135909));
#806=CARTESIAN_POINT('',(0.541095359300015,-0.75,-15.7016039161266));
#807=CARTESIAN_POINT('',(0.679127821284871,-0.75,-15.7028300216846));
#808=CARTESIAN_POINT('',(0.748144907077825,-0.75,-15.7033132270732));
#809=CARTESIAN_POINT('',(0.955164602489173,-0.75,-15.7040009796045));
#810=CARTESIAN_POINT('',(1.0931724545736,-0.75,-15.7034443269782));
#811=CARTESIAN_POINT('',(1.36914222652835,-0.75,-15.6993084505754));
#812=CARTESIAN_POINT('',(1.50710414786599,-0.75,-15.6957293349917));
#813=CARTESIAN_POINT('',(1.78256534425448,-0.75,-15.685188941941));
#814=CARTESIAN_POINT('',(1.92006492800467,-0.75,-15.6782359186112));
#815=CARTESIAN_POINT('',(2.19483905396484,-0.75,-15.6607772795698));
#816=CARTESIAN_POINT('',(2.33211359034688,-0.75,-15.6502715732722));
#817=CARTESIAN_POINT('',(2.743559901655,-0.75,-15.6132836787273));
#818=CARTESIAN_POINT('',(3.01726339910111,-0.75,-15.581334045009));
#819=CARTESIAN_POINT('',(3.55992465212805,-0.75,-15.5030144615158));
#820=CARTESIAN_POINT('',(3.82890277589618,-0.75,-15.4567848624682));
#821=CARTESIAN_POINT('',(4.36392755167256,-0.75,-15.3498484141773));
#822=CARTESIAN_POINT('',(4.62997463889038,-0.75,-15.2891437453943));
#823=CARTESIAN_POINT('',(5.15895710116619,-0.75,-15.1532282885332));
#824=CARTESIAN_POINT('',(5.42188447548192,-0.75,-15.0779863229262));
#825=CARTESIAN_POINT('',(5.94322863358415,-0.75,-14.9132881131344));
#826=CARTESIAN_POINT('',(6.20164546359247,-0.75,-14.8238320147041));
#827=CARTESIAN_POINT('',(6.85115229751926,-0.75,-14.5789290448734));
#828=CARTESIAN_POINT('',(7.23867684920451,-0.75,-14.4139021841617));
#829=CARTESIAN_POINT('',(7.99805018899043,-0.75,-14.0520702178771));
#830=CARTESIAN_POINT('',(8.36991500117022,-0.75,-13.8552986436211));
#831=CARTESIAN_POINT('',(9.09777056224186,-0.75,-13.4300705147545));
#832=CARTESIAN_POINT('',(9.45366504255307,-0.75,-13.2014490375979));
#833=CARTESIAN_POINT('',(10.1449857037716,-0.75,-12.714880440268));
#834=CARTESIAN_POINT('',(10.4804049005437,-0.75,-12.4569233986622));
#835=CARTESIAN_POINT('',(11.1277254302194,-0.75,-11.9140206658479));
#836=CARTESIAN_POINT('',(11.4396635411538,-0.75,-11.6291188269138));
#837=CARTESIAN_POINT('',(12.0383542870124,-0.75,-11.0340393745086));
#838=CARTESIAN_POINT('',(12.3251095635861,-0.75,-10.7238644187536));
#839=CARTESIAN_POINT('',(12.870898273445,-0.75,-10.0810426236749));
#840=CARTESIAN_POINT('',(13.1299839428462,-0.75,-9.74844013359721));
#841=CARTESIAN_POINT('',(13.619228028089,-0.75,-9.06258526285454));
#842=CARTESIAN_POINT('',(13.8493856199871,-0.75,-8.70933229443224));
#843=CARTESIAN_POINT('',(14.2791137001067,-0.75,-7.98471878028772));
#844=CARTESIAN_POINT('',(14.4786861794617,-0.75,-7.61335941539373));
#845=CARTESIAN_POINT('',(14.8458413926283,-0.75,-6.85515348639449));
#846=CARTESIAN_POINT('',(15.0134243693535,-0.75,-6.46830703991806));
#847=CARTESIAN_POINT('',(15.3155070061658,-0.75,-5.6816225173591));
#848=CARTESIAN_POINT('',(15.4499855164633,-0.75,-5.2817763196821));
#849=CARTESIAN_POINT('',(15.6847633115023,-0.75,-4.47217121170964));
#850=CARTESIAN_POINT('',(15.7850625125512,-0.75,-4.06241227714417));
#851=CARTESIAN_POINT('',(15.9507352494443,-0.75,-3.23605764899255));
#852=CARTESIAN_POINT('',(16.0161221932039,-0.75,-2.81946464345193));
#853=CARTESIAN_POINT('',(16.1115638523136,-0.75,-1.98225120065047));
#854=CARTESIAN_POINT('',(16.1416186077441,-0.75,-1.56163076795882));
#855=CARTESIAN_POINT('',(16.1661796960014,-0.75,-0.719438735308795));
#856=CARTESIAN_POINT('',(16.1606932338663,-0.75,-0.297867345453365));
#857=CARTESIAN_POINT('',(16.114227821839,-0.75,0.543314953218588));
#858=CARTESIAN_POINT('',(16.0732488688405,-0.75,0.962925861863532));
#859=CARTESIAN_POINT('',(15.9560905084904,-0.75,1.79720001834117));
#860=CARTESIAN_POINT('',(15.8799114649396,-0.75,2.21186331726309));
#861=CARTESIAN_POINT('',(15.6928948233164,-0.75,3.03329916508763));
#862=CARTESIAN_POINT('',(15.582057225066,-0.75,3.44007171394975));
#863=CARTESIAN_POINT('',(15.3264932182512,-0.75,4.24289288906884));
#864=CARTESIAN_POINT('',(15.181761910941,-0.75,4.63893995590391));
#865=CARTESIAN_POINT('',(14.8594487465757,-0.75,5.41743335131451));
#866=CARTESIAN_POINT('',(14.68186687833,-0.75,5.79987967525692));
#867=CARTESIAN_POINT('',(14.2950896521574,-0.75,6.54850360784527));
#868=CARTESIAN_POINT('',(14.0858900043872,-0.75,6.91467900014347));
#869=CARTESIAN_POINT('',(13.6373836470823,-0.75,7.62810226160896));
#870=CARTESIAN_POINT('',(13.3980769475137,-0.75,7.97535013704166));
#871=CARTESIAN_POINT('',(12.8911539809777,-0.75,8.64832469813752));
#872=CARTESIAN_POINT('',(12.6235482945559,-0.75,8.97405935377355));
#873=CARTESIAN_POINT('',(12.0618570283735,-0.75,9.60183607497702));
#874=CARTESIAN_POINT('',(11.767771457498,-0.75,9.9038781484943));
#875=CARTESIAN_POINT('',(11.1552973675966,-0.75,10.4820455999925));
#876=CARTESIAN_POINT('',(10.8369156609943,-0.75,10.758178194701));
#877=CARTESIAN_POINT('',(10.1780402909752,-0.75,11.2826657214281));
#878=CARTESIAN_POINT('',(9.83754661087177,-0.75,11.5310206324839));
#879=CARTESIAN_POINT('',(9.13645925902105,-0.75,11.9984683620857));
#880=CARTESIAN_POINT('',(8.775842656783,-0.75,12.2175267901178));
#881=CARTESIAN_POINT('',(8.03744530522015,-0.75,12.6244922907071));
#882=CARTESIAN_POINT('',(7.65966465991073,-0.75,12.8123995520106));
#883=CARTESIAN_POINT('',(6.88907462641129,-0.75,13.1559939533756));
#884=CARTESIAN_POINT('',(6.49624456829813,-0.75,13.3116347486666));
#885=CARTESIAN_POINT('',(5.69887180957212,-0.75,13.589295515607));
#886=CARTESIAN_POINT('',(5.29432853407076,-0.75,13.7113138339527));
#887=CARTESIAN_POINT('',(4.47763909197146,-0.75,13.9206164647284));
#888=CARTESIAN_POINT('',(4.06552036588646,-0.75,14.0080072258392));
#889=CARTESIAN_POINT('',(3.44313498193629,-0.75,14.1131515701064));
#890=CARTESIAN_POINT('',(3.2349769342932,-0.75,14.1438756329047));
#891=CARTESIAN_POINT('',(2.81757605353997,-0.75,14.1967187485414));
#892=CARTESIAN_POINT('',(2.60833331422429,-0.75,14.2188385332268));
#893=CARTESIAN_POINT('',(2.19967651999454,-0.75,14.2537079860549));
#894=CARTESIAN_POINT('',(2.00029743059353,-0.75,14.2668729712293));
#895=CARTESIAN_POINT('',(1.60124974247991,-0.75,14.2858621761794));
#896=CARTESIAN_POINT('',(1.40158124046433,-0.75,14.291688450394));
#897=CARTESIAN_POINT('',(1.10202038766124,-0.75,14.2957506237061));
#898=CARTESIAN_POINT('',(1.00214989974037,-0.75,14.2963250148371));
#899=CARTESIAN_POINT('',(0.80240752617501,-0.75,14.296275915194));
#900=CARTESIAN_POINT('',(0.702535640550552,-0.75,14.2956523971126));
#901=CARTESIAN_POINT('',(0.502793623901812,-0.75,14.2938528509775));
#902=CARTESIAN_POINT('',(0.402923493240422,-0.75,14.2926767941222));
#903=CARTESIAN_POINT('',(0.2031790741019,-0.75,14.290858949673));
#904=CARTESIAN_POINT('',(0.103304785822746,-0.75,14.2902171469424));
#905=CARTESIAN_POINT('',(0.00228680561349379,-0.75,14.2902034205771));
#906=CARTESIAN_POINT('',(0.0011434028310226,-0.75,14.2902033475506));
#907=CARTESIAN_POINT('',(0.,-0.75,14.2902033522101));
#908=B_SPLINE_CURVE_WITH_KNOTS('',3,(#698,#699,#700,#701,#702,#703,#704,#705,#706,#707,#708,
#709,#710,#711,#712,#713,#714,#715,#716,#717,#718,#719,#720,#721,#722,#723,#724,#725,#726,#727,
#728,#729,#730,#731,#732,#733,#734,#735,#736,#737,#738,#739,#740,#741,#742,#743,#744,#745,#746,
#747,#748,#749,#750,#751,#752,#753,#754,#755,#756,#757,#758,#759,#760,#761,#762,#763,#764,#765,
#766,#767,#768,#769,#770,#771,#772,#773,#774,#775,#776,#777,#778,#779,#780,#781,#782,#783,#784,
#785,#786,#787,#788,#789,#790,#791,#792,#793,#794,#795,#796,#797,#798,#799,#800,#801,#802,#803,
#804,#805,#806,#807,#808,#809,#810,#811,#812,#813,#814,#815,#816,#817,#818,#819,#820,#821,#822,
#823,#824,#825,#826,#827,#828,#829,#830,#831,#832,#833,#834,#835,#836,#837,#838,#839,#840,#841,
#842,#843,#844,#845,#846,#847,#848,#849,#850,#851,#852,#853,#854,#855,#856,#857,#858,#859,#860,
#861,#862,#863,#864,#865,#866,#867,#868,#869,#870,#871,#872,#873,#874,#875,#876,#877,#878,#879,
#880,#881,#882,#883,#884,#885,#886,#887,#888,#889,#890,#891,#892,#893,#894,#895,#896,#897,#898,
#899,#900,#901,#902,#903,#904,#905,#906,#907),.UNSPECIFIED.,.T.,.F.,(4,2,2,2,2,2,2,2,2,2,2,2,2,
2,2,2,2,2,2,2,2,2,2,2,2,2,2,2,2,2,2,2,2,2,2,2,2,2,2,2,2,2,2,2,2,2,2,2,2,2,2,2,2,2,2,2,2,2,2,2,2,
2,2,2,2,2,2,2,2,2,2,2,2,2,2,2,2,2,2,2,2,2,2,2,2,2,2,2,2,2,2,2,2,2,2,2,2,2,2,2,2,2,2,2,4),(0.,
0.187528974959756,0.375059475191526,0.562612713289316,0.750176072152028,1.12702058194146,
1.50386126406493,2.25744605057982,3.0113216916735,3.76542063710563,5.034211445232,
6.30329476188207,7.57468202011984,8.84601256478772,10.1147343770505,11.3834642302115,
12.651396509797,13.9193246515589,15.1832276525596,16.4471278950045,17.7112498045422,
18.9753723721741,20.2389548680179,21.5025366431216,22.7660200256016,24.029503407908,
25.292826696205,26.556149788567,27.8196611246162,29.0831733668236,30.3469054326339,
31.6106354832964,32.873710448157,34.1367906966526,35.3992097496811,36.6616067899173,
37.9261037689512,39.1906799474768,40.4575075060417,41.7240934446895,42.9845067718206,
44.2456138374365,45.5312858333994,46.1733270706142,46.8153976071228,47.4624625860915,
48.109421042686,48.4335381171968,48.7576675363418,49.081855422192,49.2439386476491,
49.4060209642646,49.613060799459,49.8201040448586,50.0271620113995,50.2342180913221,
50.6482198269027,51.0622067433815,51.4751859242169,51.8881756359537,52.7144278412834,
53.5328045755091,54.3510581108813,55.1710864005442,55.9911062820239,57.2531212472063,
58.5138117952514,59.7812913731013,61.0492009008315,62.3150813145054,63.580828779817,
64.8441428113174,66.1074928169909,67.3707605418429,68.6340186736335,69.8980817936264,
71.1621480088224,72.425728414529,73.6893073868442,74.9526302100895,76.2159531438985,
77.4792630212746,78.7425729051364,80.0060654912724,81.2695585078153,82.5332231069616,
83.7968872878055,85.060080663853,86.3232736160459,87.5861136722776,88.8489546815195,
90.1132653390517,91.3775683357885,92.6436748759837,93.909843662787,95.1720893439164,
95.8031823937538,96.4342217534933,97.0335229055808,97.632656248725,97.932266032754,
98.2318826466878,98.5315148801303,98.831138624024,98.8345688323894),.UNSPECIFIED.);
#909=EDGE_CURVE('E527',#695,#59,#908,.T.);
#910=ORIENTED_EDGE('',*,*,#909,.T.);
#911=EDGE_LOOP('',(#63,#232,#259,#474,#501,#670,#697,#910));
#912=FACE_BOUND('',#911,.T.);
#913=ADVANCED_FACE('F14',(#34,#912),#23,.T.);
#914=CARTESIAN_POINT('',(0.,0.,0.));
#915=DIRECTION('',(0.,0.,1.));
#916=DIRECTION('',(1.,0.,0.));
#917=AXIS2_PLACEMENT_3D('',#914,#915,#916);
#918=PLANE('',#917);
#919=CARTESIAN_POINT('',(0.,0.,0.));
#920=DIRECTION('',(0.,0.,1.));
#921=DIRECTION('',(1.,0.,0.));
#922=AXIS2_PLACEMENT_3D('',#919,#920,#921);
#923=CIRCLE('',#922,2.);
#924=CARTESIAN_POINT('',(2.,0.,0.));
#925=VERTEX_POINT('',#924);
#926=EDGE_CURVE('E452',#925,#925,#923,.T.);
#927=ORIENTED_EDGE('',*,*,#926,.F.);
#928=EDGE_LOOP('',(#927));
#929=FACE_BOUND('',#928,.T.);
#930=CARTESIAN_POINT('',(0.,0.,0.));
#931=DIRECTION('',(0.,0.,-1.));
#932=DIRECTION('',(-1.,0.,0.));
#933=AXIS2_PLACEMENT_3D('',#930,#931,#932);
#934=CIRCLE('',#933,1.5);
#935=CARTESIAN_POINT('',(-1.5,0.,0.));
#936=VERTEX_POINT('',#935);
#937=EDGE_CURVE('E255',#936,#936,#934,.T.);
#938=ORIENTED_EDGE('',*,*,#937,.F.);
#939=EDGE_LOOP('',(#938));
#940=FACE_BOUND('',#939,.T.);
#941=ADVANCED_FACE('F16',(#929,#940),#918,.F.);
#942=CARTESIAN_POINT('',(0.,0.,14.25));
#943=DIRECTION('',(0.,0.,1.));
#944=DIRECTION('',(1.,0.,0.));
#945=AXIS2_PLACEMENT_3D('',#942,#943,#944);
#946=CYLINDRICAL_SURFACE('',#945,2.);
#947=CARTESIAN_POINT('',(0.,0.,0.3));
#948=DIRECTION('',(0.,0.,1.));
#949=DIRECTION('',(1.,0.,0.));
#950=AXIS2_PLACEMENT_3D('',#947,#948,#949);
#951=CIRCLE('',#950,2.);
#952=CARTESIAN_POINT('',(2.,0.,0.3));
#953=VERTEX_POINT('',#952);
#954=EDGE_CURVE('E449',#953,#953,#951,.T.);
#955=ORIENTED_EDGE('',*,*,#954,.F.);
#956=EDGE_LOOP('',(#955));
#957=FACE_BOUND('',#956,.T.);
#958=ORIENTED_EDGE('',*,*,#926,.T.);
#959=EDGE_LOOP('',(#958));
#960=FACE_BOUND('',#959,.T.);
#961=ADVANCED_FACE('F1118',(#957,#960),#946,.T.);
#962=CARTESIAN_POINT('',(0.,2.,0.3));
#963=DIRECTION('',(0.,0.,1.));
#964=DIRECTION('',(1.,0.,0.));
#965=AXIS2_PLACEMENT_3D('',#962,#963,#964);
#966=PLANE('',#965);
#967=CARTESIAN_POINT('',(0.,0.,0.3));
#968=DIRECTION('',(0.,0.,1.));
#969=DIRECTION('',(1.,0.,0.));
#970=AXIS2_PLACEMENT_3D('',#967,#968,#969);
#971=CIRCLE('',#970,4.75);
#972=CARTESIAN_POINT('',(4.75,0.,0.3));
#973=VERTEX_POINT('',#972);
#974=EDGE_CURVE('E446',#973,#973,#971,.T.);
#975=ORIENTED_EDGE('',*,*,#974,.F.);
#976=EDGE_LOOP('',(#975));
#977=FACE_BOUND('',#976,.T.);
#978=ORIENTED_EDGE('',*,*,#954,.T.);
#979=EDGE_LOOP('',(#978));
#980=FACE_BOUND('',#979,.T.);
#981=ADVANCED_FACE('F1109',(#977,#980),#966,.F.);
#982=CARTESIAN_POINT('',(0.,0.,0.3));
#983=DIRECTION('',(0.,0.,1.));
#984=DIRECTION('',(1.,0.,0.));
#985=AXIS2_PLACEMENT_3D('',#982,#983,#984);
#986=CONICAL_SURFACE('',#985,4.75,0.785398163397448);
#987=CARTESIAN_POINT('',(0.,0.,1.05));
#988=DIRECTION('',(0.,0.,1.));
#989=DIRECTION('',(1.,0.,0.));
#990=AXIS2_PLACEMENT_3D('',#987,#988,#989);
#991=CIRCLE('',#990,5.5);
#992=CARTESIAN_POINT('',(5.5,0.,1.05));
#993=VERTEX_POINT('',#992);
#994=EDGE_CURVE('E443',#993,#993,#991,.T.);
#995=ORIENTED_EDGE('',*,*,#994,.F.);
#996=EDGE_LOOP('',(#995));
#997=FACE_BOUND('',#996,.T.);
#998=ORIENTED_EDGE('',*,*,#974,.T.);
#999=EDGE_LOOP('',(#998));
#1000=FACE_BOUND('',#999,.T.);
#1001=ADVANCED_FACE('F1100',(#997,#1000),#986,.T.);
#1002=CARTESIAN_POINT('',(0.,0.,14.25));
#1003=DIRECTION('',(0.,0.,1.));
#1004=DIRECTION('',(1.,0.,0.));
#1005=AXIS2_PLACEMENT_3D('',#1002,#1003,#1004);
#1006=CYLINDRICAL_SURFACE('',#1005,5.5);
#1007=CARTESIAN_POINT('',(0.,0.,5.));
#1008=DIRECTION('',(0.,0.,1.));
#1009=DIRECTION('',(1.,0.,0.));
#1010=AXIS2_PLACEMENT_3D('',#1007,#1008,#1009);
#1011=CIRCLE('',#1010,5.5);
#1012=CARTESIAN_POINT('',(5.5,0.,5.));
#1013=VERTEX_POINT('',#1012);
#1014=EDGE_CURVE('E440',#1013,#1013,#1011,.T.);
#1015=ORIENTED_EDGE('',*,*,#1014,.F.);
#1016=EDGE_LOOP('',(#1015));
#1017=FACE_BOUND('',#1016,.T.);
#1018=ORIENTED_EDGE('',*,*,#994,.T.);
#1019=EDGE_LOOP('',(#1018));
#1020=FACE_BOUND('',#1019,.T.);
#1021=ADVANCED_FACE('F1091',(#1017,#1020),#1006,.T.);
#1022=CARTESIAN_POINT('',(0.,5.5,5.));
#1023=DIRECTION('',(0.,0.,1.));
#1024=DIRECTION('',(1.,0.,0.));
#1025=AXIS2_PLACEMENT_3D('',#1022,#1023,#1024);
#1026=PLANE('',#1025);
#1027=CARTESIAN_POINT('',(0.,0.,5.));
#1028=DIRECTION('',(0.,0.,1.));
#1029=DIRECTION('',(1.,0.,0.));
#1030=AXIS2_PLACEMENT_3D('',#1027,#1028,#1029);
#1031=CIRCLE('',#1030,5.78947368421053);
#1032=CARTESIAN_POINT('',(5.78947368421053,0.,5.));
#1033=VERTEX_POINT('',#1032);
#1034=EDGE_CURVE('E437',#1033,#1033,#1031,.T.);
#1035=ORIENTED_EDGE('',*,*,#1034,.F.);
#1036=EDGE_LOOP('',(#1035));
#1037=FACE_BOUND('',#1036,.T.);
#1038=ORIENTED_EDGE('',*,*,#1014,.T.);
#1039=EDGE_LOOP('',(#1038));
#1040=FACE_BOUND('',#1039,.T.);
#1041=ADVANCED_FACE('F1082',(#1037,#1040),#1026,.F.);
#1042=CARTESIAN_POINT('',(0.,0.,14.25));
#1043=DIRECTION('',(0.,0.,1.));
#1044=DIRECTION('',(1.,0.,0.));
#1045=AXIS2_PLACEMENT_3D('',#1042,#1043,#1044);
#1046=CYLINDRICAL_SURFACE('',#1045,5.78947368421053);
#1047=CARTESIAN_POINT('',(0.,0.,8.75));
#1048=DIRECTION('',(0.,0.,1.));
#1049=DIRECTION('',(1.,0.,0.));
#1050=AXIS2_PLACEMENT_3D('',#1047,#1048,#1049);
#1051=CIRCLE('',#1050,5.78947368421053);
#1052=CARTESIAN_POINT('',(5.78947368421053,0.,8.75));
#1053=VERTEX_POINT('',#1052);
#1054=EDGE_CURVE('E434',#1053,#1053,#1051,.T.);
#1055=ORIENTED_EDGE('',*,*,#1054,.F.);
#1056=EDGE_LOOP('',(#1055));
#1057=FACE_BOUND('',#1056,.T.);
#1058=ORIENTED_EDGE('',*,*,#1034,.T.);
#1059=EDGE_LOOP('',(#1058));
#1060=FACE_BOUND('',#1059,.T.);
#1061=ADVANCED_FACE('F1073',(#1057,#1060),#1046,.T.);
#1062=CARTESIAN_POINT('',(0.,5.78947368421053,8.75));
#1063=DIRECTION('',(0.,0.,1.));
#1064=DIRECTION('',(1.,0.,0.));
#1065=AXIS2_PLACEMENT_3D('',#1062,#1063,#1064);
#1066=PLANE('',#1065);
#1067=CARTESIAN_POINT('',(0.,0.,8.75));
#1068=DIRECTION('',(0.,0.,1.));
#1069=DIRECTION('',(1.,0.,0.));
#1070=AXIS2_PLACEMENT_3D('',#1067,#1068,#1069);
#1071=CIRCLE('',#1070,6.95652173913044);
#1072=CARTESIAN_POINT('',(6.95652173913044,0.,8.75));
#1073=VERTEX_POINT('',#1072);
#1074=EDGE_CURVE('E431',#1073,#1073,#1071,.T.);
#1075=ORIENTED_EDGE('',*,*,#1074,.F.);
#1076=EDGE_LOOP('',(#1075));
#1077=FACE_BOUND('',#1076,.T.);
#1078=ORIENTED_EDGE('',*,*,#1054,.T.);
#1079=EDGE_LOOP('',(#1078));
#1080=FACE_BOUND('',#1079,.T.);
#1081=ADVANCED_FACE('F1065',(#1077,#1080),#1066,.F.);
#1082=CARTESIAN_POINT('',(0.,0.,14.25));
#1083=DIRECTION('',(0.,0.,1.));
#1084=DIRECTION('',(1.,0.,0.));
#1085=AXIS2_PLACEMENT_3D('',#1082,#1083,#1084);
#1086=CYLINDRICAL_SURFACE('',#1085,6.95652173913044);
#1087=CARTESIAN_POINT('',(0.,0.,5.));
#1088=DIRECTION('',(0.,0.,1.));
#1089=DIRECTION('',(1.,0.,0.));
#1090=AXIS2_PLACEMENT_3D('',#1087,#1088,#1089);
#1091=CIRCLE('',#1090,6.95652173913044);
#1092=CARTESIAN_POINT('',(6.95652173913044,0.,5.));
#1093=VERTEX_POINT('',#1092);
#1094=EDGE_CURVE('E292',#1093,#1093,#1091,.T.);
#1095=ORIENTED_EDGE('',*,*,#1094,.F.);
#1096=EDGE_LOOP('',(#1095));
#1097=FACE_BOUND('',#1096,.T.);
#1098=ORIENTED_EDGE('',*,*,#1074,.T.);
#1099=EDGE_LOOP('',(#1098));
#1100=FACE_BOUND('',#1099,.T.);
#1101=ADVANCED_FACE('F556',(#1097,#1100),#1086,.F.);
#1102=CARTESIAN_POINT('',(0.,6.95652173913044,6.35));
#1103=DIRECTION('',(0.,0.,1.));
#1104=DIRECTION('',(1.,0.,0.));
#1105=AXIS2_PLACEMENT_3D('',#1102,#1103,#1104);
#1106=PLANE('',#1105);
#1107=CARTESIAN_POINT('',(0.,0.,6.35));
#1108=DIRECTION('',(0.,0.,1.));
#1109=DIRECTION('',(1.,0.,0.));
#1110=AXIS2_PLACEMENT_3D('',#1107,#1108,#1109);
#1111=CIRCLE('',#1110,8.01);
#1112=CARTESIAN_POINT('',(8.01,0.,6.35));
#1113=VERTEX_POINT('',#1112);
#1114=EDGE_CURVE('E289',#1113,#1113,#1111,.T.);
#1115=ORIENTED_EDGE('',*,*,#1114,.T.);
#1116=EDGE_LOOP('',(#1115));
#1117=FACE_BOUND('',#1116,.T.);
#1118=CARTESIAN_POINT('',(-8.64,0.,6.35));
#1119=DIRECTION('',(0.,0.,1.));
#1120=DIRECTION('',(1.,0.,0.));
#1121=AXIS2_PLACEMENT_3D('',#1118,#1119,#1120);
#1122=CIRCLE('',#1121,1.2);
#1123=CARTESIAN_POINT('',(-7.94037037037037,-0.974945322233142,6.35));
#1124=VERTEX_POINT('',#1123);
#1125=CARTESIAN_POINT('',(-7.94037037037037,0.974945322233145,6.35));
#1126=VERTEX_POINT('',#1125);
#1127=EDGE_CURVE('E420',#1124,#1126,#1122,.T.);
#1128=ORIENTED_EDGE('',*,*,#1127,.T.);
#1129=CARTESIAN_POINT('',(0.,0.,6.35));
#1130=DIRECTION('',(0.,0.,1.));
#1131=DIRECTION('',(1.,0.,0.));
#1132=AXIS2_PLACEMENT_3D('',#1129,#1130,#1131);
#1133=CIRCLE('',#1132,8.);
#1134=CARTESIAN_POINT('',(-7.36403511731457,3.12585776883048,6.35));
#1135=VERTEX_POINT('',#1134);
#1136=EDGE_CURVE('E418',#1135,#1126,#1133,.T.);
#1137=ORIENTED_EDGE('',*,*,#1136,.F.);
#1138=CARTESIAN_POINT('',(-7.48245948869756,4.32,6.35));
#1139=DIRECTION('',(0.,0.,1.));
#1140=DIRECTION('',(1.,0.,0.));
#1141=AXIS2_PLACEMENT_3D('',#1138,#1139,#1140);
#1142=CIRCLE('',#1141,1.2);
#1143=CARTESIAN_POINT('',(-6.38908979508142,4.8145126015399,6.35));
#1144=VERTEX_POINT('',#1143);
#1145=EDGE_CURVE('E415',#1135,#1144,#1142,.T.);
#1146=ORIENTED_EDGE('',*,*,#1145,.T.);
#1147=CARTESIAN_POINT('',(0.,0.,6.35));
#1148=DIRECTION('',(0.,0.,1.));
#1149=DIRECTION('',(1.,0.,0.));
#1150=AXIS2_PLACEMENT_3D('',#1147,#1148,#1149);
#1151=CIRCLE('',#1150,8.);
#1152=CARTESIAN_POINT('',(-4.8145126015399,6.38908979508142,6.35));
#1153=VERTEX_POINT('',#1152);
#1154=EDGE_CURVE('E413',#1153,#1144,#1151,.T.);
#1155=ORIENTED_EDGE('',*,*,#1154,.F.);
#1156=CARTESIAN_POINT('',(-4.32,7.48245948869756,6.35));
#1157=DIRECTION('',(0.,0.,1.));
#1158=DIRECTION('',(1.,0.,0.));
#1159=AXIS2_PLACEMENT_3D('',#1156,#1157,#1158);
#1160=CIRCLE('',#1159,1.2);
#1161=CARTESIAN_POINT('',(-3.12585776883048,7.36403511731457,6.35));
#1162=VERTEX_POINT('',#1161);
#1163=EDGE_CURVE('E410',#1153,#1162,#1160,.T.);
#1164=ORIENTED_EDGE('',*,*,#1163,.T.);
#1165=CARTESIAN_POINT('',(0.,1.26634813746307E-13,6.35));
#1166=DIRECTION('',(0.,0.,1.));
#1167=DIRECTION('',(1.,0.,0.));
#1168=AXIS2_PLACEMENT_3D('',#1165,#1166,#1167);
#1169=CIRCLE('',#1168,7.99999999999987);
#1170=CARTESIAN_POINT('',(-0.974945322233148,7.94037037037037,6.35));
#1171=VERTEX_POINT('',#1170);
#1172=EDGE_CURVE('E408',#1171,#1162,#1169,.T.);
#1173=ORIENTED_EDGE('',*,*,#1172,.F.);
#1174=CARTESIAN_POINT('',(0.,8.64,6.35));
#1175=DIRECTION('',(0.,0.,1.));
#1176=DIRECTION('',(1.,0.,0.));
#1177=AXIS2_PLACEMENT_3D('',#1174,#1175,#1176);
#1178=CIRCLE('',#1177,1.2);
#1179=CARTESIAN_POINT('',(0.974945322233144,7.94037037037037,6.35));
#1180=VERTEX_POINT('',#1179);
#1181=EDGE_CURVE('E406',#1171,#1180,#1178,.T.);
#1182=ORIENTED_EDGE('',*,*,#1181,.T.);
#1183=CARTESIAN_POINT('',(0.,0.,6.35));
#1184=DIRECTION('',(0.,0.,1.));
#1185=DIRECTION('',(1.,0.,0.));
#1186=AXIS2_PLACEMENT_3D('',#1183,#1184,#1185);
#1187=CIRCLE('',#1186,8.);
#1188=CARTESIAN_POINT('',(3.12585776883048,7.36403511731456,6.35));
#1189=VERTEX_POINT('',#1188);
#1190=EDGE_CURVE('E403',#1189,#1180,#1187,.T.);
#1191=ORIENTED_EDGE('',*,*,#1190,.F.);
#1192=CARTESIAN_POINT('',(4.32,7.48245948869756,6.35));
#1193=DIRECTION('',(0.,0.,1.));
#1194=DIRECTION('',(1.,0.,0.));
#1195=AXIS2_PLACEMENT_3D('',#1192,#1193,#1194);
#1196=CIRCLE('',#1195,1.2);
#1197=CARTESIAN_POINT('',(4.8145126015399,6.38908979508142,6.35));
#1198=VERTEX_POINT('',#1197);
#1199=EDGE_CURVE('E400',#1189,#1198,#1196,.T.);
#1200=ORIENTED_EDGE('',*,*,#1199,.T.);
#1201=CARTESIAN_POINT('',(0.,0.,6.35));
#1202=DIRECTION('',(0.,0.,1.));
#1203=DIRECTION('',(1.,0.,0.));
#1204=AXIS2_PLACEMENT_3D('',#1201,#1202,#1203);
#1205=CIRCLE('',#1204,7.9999999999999);
#1206=CARTESIAN_POINT('',(6.38908979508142,4.81451260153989,6.35));
#1207=VERTEX_POINT('',#1206);
#1208=EDGE_CURVE('E398',#1207,#1198,#1205,.T.);
#1209=ORIENTED_EDGE('',*,*,#1208,.F.);
#1210=CARTESIAN_POINT('',(7.48245948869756,4.32,6.35));
#1211=DIRECTION('',(0.,0.,1.));
#1212=DIRECTION('',(1.,0.,0.));
#1213=AXIS2_PLACEMENT_3D('',#1210,#1211,#1212);
#1214=CIRCLE('',#1213,1.2);
#1215=CARTESIAN_POINT('',(7.36403511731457,3.12585776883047,6.35));
#1216=VERTEX_POINT('',#1215);
#1217=EDGE_CURVE('E395',#1207,#1216,#1214,.T.);
#1218=ORIENTED_EDGE('',*,*,#1217,.T.);
#1219=CARTESIAN_POINT('',(1.12757025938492E-13,0.,6.35));
#1220=DIRECTION('',(0.,0.,1.));
#1221=DIRECTION('',(1.,0.,0.));
#1222=AXIS2_PLACEMENT_3D('',#1219,#1220,#1221);
#1223=CIRCLE('',#1222,7.99999999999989);
#1224=CARTESIAN_POINT('',(7.94037037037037,0.97494532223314,6.35));
#1225=VERTEX_POINT('',#1224);
#1226=EDGE_CURVE('E393',#1225,#1216,#1223,.T.);
#1227=ORIENTED_EDGE('',*,*,#1226,.F.);
#1228=CARTESIAN_POINT('',(8.64,0.,6.35));
#1229=DIRECTION('',(0.,0.,1.));
#1230=DIRECTION('',(1.,0.,0.));
#1231=AXIS2_PLACEMENT_3D('',#1228,#1229,#1230);
#1232=CIRCLE('',#1231,1.2);
#1233=CARTESIAN_POINT('',(7.94037037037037,-0.974945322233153,6.35));
#1234=VERTEX_POINT('',#1233);
#1235=EDGE_CURVE('E390',#1225,#1234,#1232,.T.);
#1236=ORIENTED_EDGE('',*,*,#1235,.T.);
#1237=CARTESIAN_POINT('',(1.17093834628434E-13,0.,6.35));
#1238=DIRECTION('',(0.,0.,1.));
#1239=DIRECTION('',(1.,0.,0.));
#1240=AXIS2_PLACEMENT_3D('',#1237,#1238,#1239);
#1241=CIRCLE('',#1240,7.99999999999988);
#1242=CARTESIAN_POINT('',(7.36403511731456,-3.12585776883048,6.35));
#1243=VERTEX_POINT('',#1242);
#1244=EDGE_CURVE('E388',#1243,#1234,#1241,.T.);
#1245=ORIENTED_EDGE('',*,*,#1244,.F.);
#1246=CARTESIAN_POINT('',(7.48245948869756,-4.32,6.35));
#1247=DIRECTION('',(0.,0.,1.));
#1248=DIRECTION('',(1.,0.,0.));
#1249=AXIS2_PLACEMENT_3D('',#1246,#1247,#1248);
#1250=CIRCLE('',#1249,1.2);
#1251=CARTESIAN_POINT('',(6.38908979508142,-4.8145126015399,6.35));
#1252=VERTEX_POINT('',#1251);
#1253=EDGE_CURVE('E385',#1243,#1252,#1250,.T.);
#1254=ORIENTED_EDGE('',*,*,#1253,.T.);
#1255=CARTESIAN_POINT('',(0.,0.,6.35));
#1256=DIRECTION('',(0.,0.,1.));
#1257=DIRECTION('',(1.,0.,0.));
#1258=AXIS2_PLACEMENT_3D('',#1255,#1256,#1257);
#1259=CIRCLE('',#1258,8.);
#1260=CARTESIAN_POINT('',(4.81451260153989,-6.38908979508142,6.35));
#1261=VERTEX_POINT('',#1260);
#1262=EDGE_CURVE('E383',#1261,#1252,#1259,.T.);
#1263=ORIENTED_EDGE('',*,*,#1262,.F.);
#1264=CARTESIAN_POINT('',(4.32,-7.48245948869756,6.35));
#1265=DIRECTION('',(0.,0.,1.));
#1266=DIRECTION('',(1.,0.,0.));
#1267=AXIS2_PLACEMENT_3D('',#1264,#1265,#1266);
#1268=CIRCLE('',#1267,1.2);
#1269=CARTESIAN_POINT('',(3.12585776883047,-7.36403511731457,6.35));
#1270=VERTEX_POINT('',#1269);
#1271=EDGE_CURVE('E380',#1261,#1270,#1268,.T.);
#1272=ORIENTED_EDGE('',*,*,#1271,.T.);
#1273=CARTESIAN_POINT('',(0.,-1.54390389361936E-13,6.35));
#1274=DIRECTION('',(0.,0.,1.));
#1275=DIRECTION('',(1.,0.,0.));
#1276=AXIS2_PLACEMENT_3D('',#1273,#1274,#1275);
#1277=CIRCLE('',#1276,7.99999999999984);
#1278=CARTESIAN_POINT('',(0.974945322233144,-7.94037037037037,6.35));
#1279=VERTEX_POINT('',#1278);
#1280=EDGE_CURVE('E378',#1279,#1270,#1277,.T.);
#1281=ORIENTED_EDGE('',*,*,#1280,.F.);
#1282=CARTESIAN_POINT('',(0.,-8.64,6.35));
#1283=DIRECTION('',(0.,0.,1.));
#1284=DIRECTION('',(1.,0.,0.));
#1285=AXIS2_PLACEMENT_3D('',#1282,#1283,#1284);
#1286=CIRCLE('',#1285,1.2);
#1287=CARTESIAN_POINT('',(-0.974945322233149,-7.94037037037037,6.35));
#1288=VERTEX_POINT('',#1287);
#1289=EDGE_CURVE('E375',#1279,#1288,#1286,.T.);
#1290=ORIENTED_EDGE('',*,*,#1289,.T.);
#1291=CARTESIAN_POINT('',(0.,0.,6.35));
#1292=DIRECTION('',(0.,0.,1.));
#1293=DIRECTION('',(1.,0.,0.));
#1294=AXIS2_PLACEMENT_3D('',#1291,#1292,#1293);
#1295=CIRCLE('',#1294,8.);
#1296=CARTESIAN_POINT('',(-3.12585776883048,-7.36403511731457,6.35));
#1297=VERTEX_POINT('',#1296);
#1298=EDGE_CURVE('E373',#1297,#1288,#1295,.T.);
#1299=ORIENTED_EDGE('',*,*,#1298,.F.);
#1300=CARTESIAN_POINT('',(-4.32,-7.48245948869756,6.35));
#1301=DIRECTION('',(0.,0.,1.));
#1302=DIRECTION('',(1.,0.,0.));
#1303=AXIS2_PLACEMENT_3D('',#1300,#1301,#1302);
#1304=CIRCLE('',#1303,1.2);
#1305=CARTESIAN_POINT('',(-4.8145126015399,-6.38908979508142,6.35));
#1306=VERTEX_POINT('',#1305);
#1307=EDGE_CURVE('E370',#1297,#1306,#1304,.T.);
#1308=ORIENTED_EDGE('',*,*,#1307,.T.);
#1309=CARTESIAN_POINT('',(0.,0.,6.35));
#1310=DIRECTION('',(0.,0.,1.));
#1311=DIRECTION('',(1.,0.,0.));
#1312=AXIS2_PLACEMENT_3D('',#1309,#1310,#1311);
#1313=CIRCLE('',#1312,8.);
#1314=CARTESIAN_POINT('',(-6.38908979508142,-4.81451260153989,6.35));
#1315=VERTEX_POINT('',#1314);
#1316=EDGE_CURVE('E368',#1315,#1306,#1313,.T.);
#1317=ORIENTED_EDGE('',*,*,#1316,.F.);
#1318=CARTESIAN_POINT('',(-7.48245948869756,-4.32,6.35));
#1319=DIRECTION('',(0.,0.,1.));
#1320=DIRECTION('',(1.,0.,0.));
#1321=AXIS2_PLACEMENT_3D('',#1318,#1319,#1320);
#1322=CIRCLE('',#1321,1.2);
#1323=CARTESIAN_POINT('',(-7.36403511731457,-3.12585776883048,6.35));
#1324=VERTEX_POINT('',#1323);
#1325=EDGE_CURVE('E365',#1315,#1324,#1322,.T.);
#1326=ORIENTED_EDGE('',*,*,#1325,.T.);
#1327=CARTESIAN_POINT('',(-1.52655665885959E-13,0.,6.35));
#1328=DIRECTION('',(0.,0.,1.));
#1329=DIRECTION('',(1.,0.,0.));
#1330=AXIS2_PLACEMENT_3D('',#1327,#1328,#1329);
#1331=CIRCLE('',#1330,7.99999999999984);
#1332=EDGE_CURVE('E423',#1124,#1324,#1331,.T.);
#1333=ORIENTED_EDGE('',*,*,#1332,.F.);
#1334=EDGE_LOOP('',(#1128,#1137,#1146,#1155,#1164,#1173,#1182,#1191,#1200,#1209,#1218,#1227,
#1236,#1245,#1254,#1263,#1272,#1281,#1290,#1299,#1308,#1317,#1326,#1333));
#1335=FACE_BOUND('',#1334,.T.);
#1336=ADVANCED_FACE('F553',(#1117,#1335),#1106,.T.);
#1337=CARTESIAN_POINT('',(0.,7.26,5.));
#1338=DIRECTION('',(0.,0.,-1.));
#1339=DIRECTION('',(-1.,0.,0.));
#1340=AXIS2_PLACEMENT_3D('',#1337,#1338,#1339);
#1341=PLANE('',#1340);
#1342=ORIENTED_EDGE('',*,*,#1094,.T.);
#1343=EDGE_LOOP('',(#1342));
#1344=FACE_BOUND('',#1343,.T.);
#1345=CARTESIAN_POINT('',(0.,0.,5.));
#1346=DIRECTION('',(0.,0.,1.));
#1347=DIRECTION('',(1.,0.,0.));
#1348=AXIS2_PLACEMENT_3D('',#1345,#1346,#1347);
#1349=CIRCLE('',#1348,7.26);
#1350=CARTESIAN_POINT('',(7.26,0.,5.));
#1351=VERTEX_POINT('',#1350);
#1352=EDGE_CURVE('E236',#1351,#1351,#1349,.T.);
#1353=ORIENTED_EDGE('',*,*,#1352,.F.);
#1354=EDGE_LOOP('',(#1353));
#1355=FACE_BOUND('',#1354,.T.);
#1356=ADVANCED_FACE('F551',(#1344,#1355),#1341,.T.);
#1357=CARTESIAN_POINT('',(0.,0.,13.5));
#1358=DIRECTION('',(0.,0.,1.));
#1359=DIRECTION('',(1.,0.,0.));
#1360=AXIS2_PLACEMENT_3D('',#1357,#1358,#1359);
#1361=CYLINDRICAL_SURFACE('',#1360,8.01);
#1362=CARTESIAN_POINT('',(0.,0.,5.75));
#1363=DIRECTION('',(0.,0.,1.));
#1364=DIRECTION('',(1.,0.,0.));
#1365=AXIS2_PLACEMENT_3D('',#1362,#1363,#1364);
#1366=CIRCLE('',#1365,8.01);
#1367=CARTESIAN_POINT('',(8.01,0.,5.75));
#1368=VERTEX_POINT('',#1367);
#1369=EDGE_CURVE('E286',#1368,#1368,#1366,.T.);
#1370=ORIENTED_EDGE('',*,*,#1369,.T.);
#1371=EDGE_LOOP('',(#1370));
#1372=FACE_BOUND('',#1371,.T.);
#1373=ORIENTED_EDGE('',*,*,#1114,.F.);
#1374=EDGE_LOOP('',(#1373));
#1375=FACE_BOUND('',#1374,.T.);
#1376=ADVANCED_FACE('F547',(#1372,#1375),#1361,.T.);
#1377=CARTESIAN_POINT('',(0.,0.,5.75));
#1378=DIRECTION('',(0.,0.,1.));
#1379=DIRECTION('',(1.,0.,0.));
#1380=AXIS2_PLACEMENT_3D('',#1377,#1378,#1379);
#1381=CONICAL_SURFACE('',#1380,8.01,0.785398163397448);
#1382=ORIENTED_EDGE('',*,*,#1352,.T.);
#1383=EDGE_LOOP('',(#1382));
#1384=FACE_BOUND('',#1383,.T.);
#1385=ORIENTED_EDGE('',*,*,#1369,.F.);
#1386=EDGE_LOOP('',(#1385));
#1387=FACE_BOUND('',#1386,.T.);
#1388=ADVANCED_FACE('F544',(#1384,#1387),#1381,.T.);
#1389=CARTESIAN_POINT('',(0.,7.25,13.5));
#1390=DIRECTION('',(0.,0.,-1.));
#1391=DIRECTION('',(-1.,0.,0.));
#1392=AXIS2_PLACEMENT_3D('',#1389,#1390,#1391);
#1393=PLANE('',#1392);
#1394=ORIENTED_EDGE('',*,*,#31,.F.);
#1395=EDGE_LOOP('',(#1394));
#1396=FACE_BOUND('',#1395,.T.);
#1397=CARTESIAN_POINT('',(0.,0.,13.5));
#1398=DIRECTION('',(0.,0.,1.));
#1399=DIRECTION('',(1.,0.,0.));
#1400=AXIS2_PLACEMENT_3D('',#1397,#1398,#1399);
#1401=CIRCLE('',#1400,7.25);
#1402=CARTESIAN_POINT('',(7.25,0.,13.5));
#1403=VERTEX_POINT('',#1402);
#1404=EDGE_CURVE('E428',#1403,#1403,#1401,.T.);
#1405=ORIENTED_EDGE('',*,*,#1404,.T.);
#1406=EDGE_LOOP('',(#1405));
#1407=FACE_BOUND('',#1406,.T.);
#1408=ADVANCED_FACE('F484',(#1396,#1407),#1393,.F.);
#1409=CARTESIAN_POINT('',(0.,0.,11.75));
#1410=DIRECTION('',(0.,0.,-1.));
#1411=DIRECTION('',(-1.,0.,0.));
#1412=AXIS2_PLACEMENT_3D('',#1409,#1410,#1411);
#1413=CONICAL_SURFACE('',#1412,9.,0.785398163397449);
#1414=ORIENTED_EDGE('',*,*,#1404,.F.);
#1415=EDGE_LOOP('',(#1414));
#1416=FACE_BOUND('',#1415,.T.);
#1417=CARTESIAN_POINT('',(0.,0.,12.75));
#1418=DIRECTION('',(0.,0.,-1.));
#1419=DIRECTION('',(-1.,0.,0.));
#1420=AXIS2_PLACEMENT_3D('',#1417,#1418,#1419);
#1421=CIRCLE('',#1420,8.);
#1422=CARTESIAN_POINT('',(-7.94037037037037,0.974945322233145,12.75));
#1423=VERTEX_POINT('',#1422);
#1424=CARTESIAN_POINT('',(-7.36403511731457,3.12585776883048,12.75));
#1425=VERTEX_POINT('',#1424);
#1426=EDGE_CURVE('E574',#1423,#1425,#1421,.T.);
#1427=ORIENTED_EDGE('',*,*,#1426,.F.);
#1428=CARTESIAN_POINT('',(-7.94057037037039,0.975088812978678,12.7497840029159));
#1429=CARTESIAN_POINT('',(-7.90968957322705,0.952923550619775,12.7831310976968));
#1430=CARTESIAN_POINT('',(-7.87946053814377,0.929030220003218,12.815989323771));
#1431=CARTESIAN_POINT('',(-7.82052659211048,0.877502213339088,12.880430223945));
#1432=CARTESIAN_POINT('',(-7.79182855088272,0.849852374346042,12.9120070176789));
#1433=CARTESIAN_POINT('',(-7.73603175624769,0.790271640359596,12.9737542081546));
#1434=CARTESIAN_POINT('',(-7.70896282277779,0.758283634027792,13.0038970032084));
#1435=CARTESIAN_POINT('',(-7.657447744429,0.690224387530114,13.0615719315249));
#1436=CARTESIAN_POINT('',(-7.63299674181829,0.654160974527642,13.0891088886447));
#1437=CARTESIAN_POINT('',(-7.58587103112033,0.575368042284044,13.14243759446));
#1438=CARTESIAN_POINT('',(-7.56340444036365,0.532362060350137,13.1680109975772));
#1439=CARTESIAN_POINT('',(-7.52319538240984,0.441802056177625,13.2139702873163));
#1440=CARTESIAN_POINT('',(-7.50543466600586,0.39426660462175,13.234376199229));
#1441=CARTESIAN_POINT('',(-7.4755126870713,0.294469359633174,13.2688527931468));
#1442=CARTESIAN_POINT('',(-7.46342608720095,0.242154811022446,13.2828389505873));
#1443=CARTESIAN_POINT('',(-7.4463699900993,0.134851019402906,13.3025992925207));
#1444=CARTESIAN_POINT('',(-7.44139401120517,0.0798642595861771,13.3083809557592));
#1445=CARTESIAN_POINT('',(-7.43928370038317,-0.0222726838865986,13.3108320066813));
#1446=CARTESIAN_POINT('',(-7.44109699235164,-0.0693771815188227,13.3087243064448));
#1447=CARTESIAN_POINT('',(-7.45011649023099,-0.162353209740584,13.298259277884));
#1448=CARTESIAN_POINT('',(-7.45732376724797,-0.208224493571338,13.2899007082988));
#1449=CARTESIAN_POINT('',(-7.47617158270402,-0.295679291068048,13.2681047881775));
#1450=CARTESIAN_POINT('',(-7.48761944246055,-0.33736136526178,13.254888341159));
#1451=CARTESIAN_POINT('',(-7.5142876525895,-0.41781591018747,13.2242092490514));
#1452=CARTESIAN_POINT('',(-7.52950854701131,-0.456587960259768,13.2067459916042));
#1453=CARTESIAN_POINT('',(-7.57250068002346,-0.551817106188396,13.1576288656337));
#1454=CARTESIAN_POINT('',(-7.60252148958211,-0.60598836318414,13.1235111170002));
#1455=CARTESIAN_POINT('',(-7.66819773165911,-0.706562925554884,13.0494651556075));
#1456=CARTESIAN_POINT('',(-7.70387590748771,-0.752933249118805,13.0095135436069));
#1457=CARTESIAN_POINT('',(-7.77253186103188,-0.830468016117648,12.9332916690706));
#1458=CARTESIAN_POINT('',(-7.80484143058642,-0.862867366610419,12.8976514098));
#1459=CARTESIAN_POINT('',(-7.87136090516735,-0.922583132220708,12.824796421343));
#1460=CARTESIAN_POINT('',(-7.90554979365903,-0.949944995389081,12.7875999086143));
#1461=CARTESIAN_POINT('',(-7.94057037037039,-0.975088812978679,12.7497840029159));
#1462=B_SPLINE_CURVE_WITH_KNOTS('',3,(#1428,#1429,#1430,#1431,#1432,#1433,#1434,#1435,#1436,
#1437,#1438,#1439,#1440,#1441,#1442,#1443,#1444,#1445,#1446,#1447,#1448,#1449,#1450,#1451,#1452,
#1453,#1454,#1455,#1456,#1457,#1458,#1459,#1460,#1461),.UNSPECIFIED.,.F.,.F.,(4,2,2,2,2,2,2,2,2,
2,2,2,2,2,2,2,4),(0.,0.151717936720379,0.304067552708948,0.458663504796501,0.612967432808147,
0.77696595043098,0.940318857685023,1.10576483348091,1.27105990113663,1.41187037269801,
1.55270881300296,1.68780653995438,1.82292375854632,2.03386670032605,2.24568022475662,
2.41940268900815,2.59147151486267),.UNSPECIFIED.);
#1463=CARTESIAN_POINT('',(-7.94037037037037,-0.974945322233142,12.75));
#1464=VERTEX_POINT('',#1463);
#1465=EDGE_CURVE('E567',#1423,#1464,#1462,.T.);
#1466=ORIENTED_EDGE('',*,*,#1465,.T.);
#1467=CARTESIAN_POINT('',(0.,0.,12.7500000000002));
#1468=DIRECTION('',(0.,0.,-1.));
#1469=DIRECTION('',(-1.,0.,0.));
#1470=AXIS2_PLACEMENT_3D('',#1467,#1468,#1469);
#1471=CIRCLE('',#1470,7.99999999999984);
#1472=CARTESIAN_POINT('',(-7.36403511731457,-3.12585776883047,12.75));
#1473=VERTEX_POINT('',#1472);
#1474=EDGE_CURVE('E611',#1473,#1464,#1471,.T.);
#1475=ORIENTED_EDGE('',*,*,#1474,.F.);
#1476=CARTESIAN_POINT('',(-7.36423511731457,-3.1258379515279,12.7498236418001));
#1477=CARTESIAN_POINT('',(-7.32640866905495,-3.1295946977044,12.783170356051));
#1478=CARTESIAN_POINT('',(-7.28828265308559,-3.13517392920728,12.8160281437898));
#1479=CARTESIAN_POINT('',(-7.2114799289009,-3.15033469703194,12.8804680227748));
#1480=CARTESIAN_POINT('',(-7.17280158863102,-3.15993280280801,12.91204423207));
#1481=CARTESIAN_POINT('',(-7.0946894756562,-3.18363635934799,12.9737900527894));
#1482=CARTESIAN_POINT('',(-7.05525297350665,-3.19780618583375,13.0039320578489));
#1483=CARTESIAN_POINT('',(-6.97660992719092,-3.23099360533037,13.0616051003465));
#1484=CARTESIAN_POINT('',(-6.9374030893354,-3.25000198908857,13.0891409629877));
#1485=CARTESIAN_POINT('',(-6.85719662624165,-3.29467930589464,13.142465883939));
#1486=CARTESIAN_POINT('',(-6.81623899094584,-3.32069148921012,13.1680367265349));
#1487=CARTESIAN_POINT('',(-6.73614117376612,-3.37901622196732,13.2139908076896));
#1488=CARTESIAN_POINT('',(-6.69699447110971,-3.4113035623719,13.2343940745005));
#1489=CARTESIAN_POINT('',(-6.62118746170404,-3.48277049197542,13.2688653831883));
#1490=CARTESIAN_POINT('',(-6.584565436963,-3.52203308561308,13.2828489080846));
#1491=CARTESIAN_POINT('',(-6.51614768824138,-3.60643240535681,13.3026043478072));
#1492=CARTESIAN_POINT('',(-6.48434759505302,-3.65156374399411,13.3083837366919));
#1493=CARTESIAN_POINT('',(-6.43145576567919,-3.7389606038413,13.310831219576));
#1494=CARTESIAN_POINT('',(-6.40947559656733,-3.780660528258,13.3087220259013));
#1495=CARTESIAN_POINT('',(-6.37080198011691,-3.8656886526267,13.2982544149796));
#1496=CARTESIAN_POINT('',(-6.35410958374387,-3.90901717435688,13.2898947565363));
#1497=CARTESIAN_POINT('',(-6.32670722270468,-3.99417866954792,13.2680967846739));
#1498=CARTESIAN_POINT('',(-6.31578128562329,-4.03600067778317,13.2548791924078));
#1499=CARTESIAN_POINT('',(-6.29865129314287,-4.11901098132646,13.2241979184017));
#1500=CARTESIAN_POINT('',(-6.29244792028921,-4.16019918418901,13.2067336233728));
#1501=CARTESIAN_POINT('',(-6.28206793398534,-4.26416787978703,13.1576132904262));
#1502=CARTESIAN_POINT('',(-6.28098265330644,-4.32609340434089,13.1234932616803));
#1503=CARTESIAN_POINT('',(-6.28757607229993,-4.44603409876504,13.0494427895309));
#1504=CARTESIAN_POINT('',(-6.29529095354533,-4.50403207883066,13.0094889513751));
#1505=CARTESIAN_POINT('',(-6.3159824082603,-4.6054964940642,12.9332722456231));
#1506=CARTESIAN_POINT('',(-6.32776150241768,-4.64969914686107,12.8976400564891));
#1507=CARTESIAN_POINT('',(-6.35550491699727,-4.73465428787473,12.8248019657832));
#1508=CARTESIAN_POINT('',(-6.37142834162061,-4.77543560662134,12.7876142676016));
#1509=CARTESIAN_POINT('',(-6.38918027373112,-4.81471260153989,12.7498073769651));
#1510=B_SPLINE_CURVE_WITH_KNOTS('',3,(#1476,#1477,#1478,#1479,#1480,#1481,#1482,#1483,#1484,
#1485,#1486,#1487,#1488,#1489,#1490,#1491,#1492,#1493,#1494,#1495,#1496,#1497,#1498,#1499,#1500,
#1501,#1502,#1503,#1504,#1505,#1506,#1507,#1508,#1509),.UNSPECIFIED.,.F.,.F.,(4,2,2,2,2,2,2,2,2,
2,2,2,2,2,2,2,4),(0.,0.151718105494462,0.304067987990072,0.458664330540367,0.612968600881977,
0.776960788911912,0.940307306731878,1.10574664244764,1.27103516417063,1.41184239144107,
1.55267758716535,1.68777657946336,1.82289509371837,2.03384499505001,2.24566534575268,
2.41934716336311,2.59137612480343),.UNSPECIFIED.);
#1511=CARTESIAN_POINT('',(-6.38908979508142,-4.81451260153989,12.75));
#1512=VERTEX_POINT('',#1511);
#1513=EDGE_CURVE('E455',#1473,#1512,#1510,.T.);
#1514=ORIENTED_EDGE('',*,*,#1513,.T.);
#1515=CARTESIAN_POINT('',(0.,0.,12.75));
#1516=DIRECTION('',(0.,0.,-1.));
#1517=DIRECTION('',(-1.,0.,0.));
#1518=AXIS2_PLACEMENT_3D('',#1515,#1516,#1517);
#1519=CIRCLE('',#1518,8.);
#1520=CARTESIAN_POINT('',(-4.8145126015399,-6.38908979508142,12.75));
#1521=VERTEX_POINT('',#1520);
#1522=EDGE_CURVE('E464',#1521,#1512,#1519,.T.);
#1523=ORIENTED_EDGE('',*,*,#1522,.F.);
#1524=CARTESIAN_POINT('',(-4.8147126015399,-6.38918027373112,12.7498073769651));
#1525=CARTESIAN_POINT('',(-4.78007595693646,-6.37352002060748,12.7831542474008));
#1526=CARTESIAN_POINT('',(-4.74426863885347,-6.35928827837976,12.8160122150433));
#1527=CARTESIAN_POINT('',(-4.67017594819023,-6.33401548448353,12.8804525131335));
#1528=CARTESIAN_POINT('',(-4.63188087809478,-6.32298796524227,12.9120289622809));
#1529=CARTESIAN_POINT('',(-4.55238285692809,-6.30445860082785,12.973775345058));
#1530=CARTESIAN_POINT('',(-4.51114535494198,-6.29701113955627,13.0039176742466));
#1531=CARTESIAN_POINT('',(-4.42644559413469,-6.28642938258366,13.0615914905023));
#1532=CARTESIAN_POINT('',(-4.38298768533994,-6.28328696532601,13.0891278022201));
#1533=CARTESIAN_POINT('',(-4.29118817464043,-6.28187376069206,13.1424542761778));
#1534=CARTESIAN_POINT('',(-4.24271126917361,-6.28392131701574,13.1680261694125));
#1535=CARTESIAN_POINT('',(-4.14418105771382,-6.29438152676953,13.2139823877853));
#1536=CARTESIAN_POINT('',(-4.09413470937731,-6.30276908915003,13.234386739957));
#1537=CARTESIAN_POINT('',(-3.99274893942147,-6.32675643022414,13.2688602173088));
#1538=CARTESIAN_POINT('',(-3.94140116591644,-6.34244723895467,13.2828448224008));
#1539=CARTESIAN_POINT('',(-3.83994807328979,-6.38132941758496,13.3026022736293));
#1540=CARTESIAN_POINT('',(-3.78984166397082,-6.40451393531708,13.3083825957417));
#1541=CARTESIAN_POINT('',(-3.70033582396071,-6.45375547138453,13.3108315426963));
#1542=CARTESIAN_POINT('',(-3.66044977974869,-6.47887837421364,13.3087229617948));
#1543=CARTESIAN_POINT('',(-3.58444196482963,-6.53317784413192,13.2982564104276));
#1544=CARTESIAN_POINT('',(-3.54832094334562,-6.56235521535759,13.2898971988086));
#1545=CARTESIAN_POINT('',(-3.48200812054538,-6.62240574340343,13.2681000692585));
#1546=CARTESIAN_POINT('',(-3.45163470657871,-6.65316137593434,13.2548829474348));
#1547=CARTESIAN_POINT('',(-3.39529396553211,-6.71648483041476,13.2242025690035));
#1548=CARTESIAN_POINT('',(-3.36932727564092,-6.74905291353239,13.2067386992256));
#1549=CARTESIAN_POINT('',(-3.30835313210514,-6.83390135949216,13.1576196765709));
#1550=CARTESIAN_POINT('',(-3.27645022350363,-6.88698697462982,13.1235005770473));
#1551=CARTESIAN_POINT('',(-3.22218923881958,-6.99415380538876,13.0494519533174));
#1552=CARTESIAN_POINT('',(-3.19987109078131,-7.04823822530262,13.0094990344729));
#1553=CARTESIAN_POINT('',(-3.16705734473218,-7.14645323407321,12.9332841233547));
#1554=CARTESIAN_POINT('',(-3.15515658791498,-7.19062265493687,12.8976528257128));
#1555=CARTESIAN_POINT('',(-3.13670454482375,-7.2780662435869,12.824816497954));
#1556=CARTESIAN_POINT('',(-3.13010342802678,-7.32134493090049,12.7876296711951));
#1557=CARTESIAN_POINT('',(-3.1258379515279,-7.36423511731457,12.7498236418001));
#1558=B_SPLINE_CURVE_WITH_KNOTS('',3,(#1524,#1525,#1526,#1527,#1528,#1529,#1530,#1531,#1532,
#1533,#1534,#1535,#1536,#1537,#1538,#1539,#1540,#1541,#1542,#1543,#1544,#1545,#1546,#1547,#1548,
#1549,#1550,#1551,#1552,#1553,#1554,#1555,#1556,#1557),.UNSPECIFIED.,.F.,.F.,(4,2,2,2,2,2,2,2,2,
2,2,2,2,2,2,2,4),(0.,0.15171803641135,0.304067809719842,0.458663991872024,0.612968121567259,
0.7769629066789,0.940312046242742,1.10575410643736,1.27104531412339,1.4118538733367,
1.55269039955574,1.68778886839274,1.8229068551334,2.03385393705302,2.24567145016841,
2.41935018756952,2.59137610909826),.UNSPECIFIED.);
#1559=CARTESIAN_POINT('',(-3.12585776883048,-7.36403511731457,12.75));
#1560=VERTEX_POINT('',#1559);
#1561=EDGE_CURVE('E734',#1521,#1560,#1558,.T.);
#1562=ORIENTED_EDGE('',*,*,#1561,.T.);
#1563=CARTESIAN_POINT('',(0.,0.,12.75));
#1564=DIRECTION('',(0.,0.,-1.));
#1565=DIRECTION('',(-1.,0.,0.));
#1566=AXIS2_PLACEMENT_3D('',#1563,#1564,#1565);
#1567=CIRCLE('',#1566,8.);
#1568=CARTESIAN_POINT('',(-0.974945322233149,-7.94037037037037,12.75));
#1569=VERTEX_POINT('',#1568);
#1570=EDGE_CURVE('E721',#1569,#1560,#1567,.T.);
#1571=ORIENTED_EDGE('',*,*,#1570,.F.);
#1572=CARTESIAN_POINT('',(-0.975088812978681,-7.94057037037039,12.7497840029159));
#1573=CARTESIAN_POINT('',(-0.952923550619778,-7.90968957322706,12.7831310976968));
#1574=CARTESIAN_POINT('',(-0.929030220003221,-7.87946053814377,12.815989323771));
#1575=CARTESIAN_POINT('',(-0.877502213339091,-7.82052659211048,12.880430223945));
#1576=CARTESIAN_POINT('',(-0.849852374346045,-7.79182855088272,12.9120070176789));
#1577=CARTESIAN_POINT('',(-0.7902716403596,-7.73603175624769,12.9737542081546));
#1578=CARTESIAN_POINT('',(-0.758283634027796,-7.70896282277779,13.0038970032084));
#1579=CARTESIAN_POINT('',(-0.690224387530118,-7.657447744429,13.0615719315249));
#1580=CARTESIAN_POINT('',(-0.654160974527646,-7.63299674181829,13.0891088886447));
#1581=CARTESIAN_POINT('',(-0.575368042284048,-7.58587103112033,13.14243759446));
#1582=CARTESIAN_POINT('',(-0.532362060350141,-7.56340444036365,13.1680109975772));
#1583=CARTESIAN_POINT('',(-0.441802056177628,-7.52319538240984,13.2139702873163));
#1584=CARTESIAN_POINT('',(-0.394266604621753,-7.50543466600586,13.234376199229));
#1585=CARTESIAN_POINT('',(-0.294469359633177,-7.4755126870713,13.2688527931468));
#1586=CARTESIAN_POINT('',(-0.242154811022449,-7.46342608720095,13.2828389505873));
#1587=CARTESIAN_POINT('',(-0.134851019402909,-7.4463699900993,13.3025992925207));
#1588=CARTESIAN_POINT('',(-0.0798642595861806,-7.44139401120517,13.3083809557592));
#1589=CARTESIAN_POINT('',(0.0222726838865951,-7.43928370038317,13.3108320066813));
#1590=CARTESIAN_POINT('',(0.0693771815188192,-7.44109699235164,13.3087243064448));
#1591=CARTESIAN_POINT('',(0.162353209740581,-7.45011649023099,13.298259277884));
#1592=CARTESIAN_POINT('',(0.208224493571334,-7.45732376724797,13.2899007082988));
#1593=CARTESIAN_POINT('',(0.295679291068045,-7.47617158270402,13.2681047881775));
#1594=CARTESIAN_POINT('',(0.337361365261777,-7.48761944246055,13.254888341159));
#1595=CARTESIAN_POINT('',(0.417815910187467,-7.5142876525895,13.2242092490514));
#1596=CARTESIAN_POINT('',(0.456587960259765,-7.52950854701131,13.2067459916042));
#1597=CARTESIAN_POINT('',(0.551817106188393,-7.57250068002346,13.1576288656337));
#1598=CARTESIAN_POINT('',(0.605988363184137,-7.60252148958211,13.1235111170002));
#1599=CARTESIAN_POINT('',(0.70656292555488,-7.66819773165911,13.0494651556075));
#1600=CARTESIAN_POINT('',(0.752933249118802,-7.70387590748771,13.0095135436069));
#1601=CARTESIAN_POINT('',(0.830468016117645,-7.77253186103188,12.9332916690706));
#1602=CARTESIAN_POINT('',(0.862867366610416,-7.80484143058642,12.8976514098));
#1603=CARTESIAN_POINT('',(0.922583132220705,-7.87136090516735,12.824796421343));
#1604=CARTESIAN_POINT('',(0.949944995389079,-7.90554979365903,12.7875999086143));
#1605=CARTESIAN_POINT('',(0.975088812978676,-7.94057037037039,12.7497840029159));
#1606=B_SPLINE_CURVE_WITH_KNOTS('',3,(#1572,#1573,#1574,#1575,#1576,#1577,#1578,#1579,#1580,
#1581,#1582,#1583,#1584,#1585,#1586,#1587,#1588,#1589,#1590,#1591,#1592,#1593,#1594,#1595,#1596,
#1597,#1598,#1599,#1600,#1601,#1602,#1603,#1604,#1605),.UNSPECIFIED.,.F.,.F.,(4,2,2,2,2,2,2,2,2,
2,2,2,2,2,2,2,4),(0.,0.151717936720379,0.304067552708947,0.4586635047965,0.612967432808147,
0.77696595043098,0.940318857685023,1.10576483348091,1.27105990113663,1.41187037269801,
1.55270881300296,1.68780653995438,1.82292375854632,2.03386670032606,2.24568022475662,
2.41940268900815,2.59147151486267),.UNSPECIFIED.);
#1607=CARTESIAN_POINT('',(0.974945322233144,-7.94037037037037,12.75));
#1608=VERTEX_POINT('',#1607);
#1609=EDGE_CURVE('E714',#1569,#1608,#1606,.T.);
#1610=ORIENTED_EDGE('',*,*,#1609,.T.);
#1611=CARTESIAN_POINT('',(0.,0.,12.7500000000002));
#1612=DIRECTION('',(0.,0.,-1.));
#1613=DIRECTION('',(-1.,0.,0.));
#1614=AXIS2_PLACEMENT_3D('',#1611,#1612,#1613);
#1615=CIRCLE('',#1614,7.99999999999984);
#1616=CARTESIAN_POINT('',(3.12585776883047,-7.36403511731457,12.7500000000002));
#1617=VERTEX_POINT('',#1616);
#1618=EDGE_CURVE('E712',#1617,#1608,#1615,.T.);
#1619=ORIENTED_EDGE('',*,*,#1618,.F.);
#1620=CARTESIAN_POINT('',(3.12583795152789,-7.36423511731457,12.7498236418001));
#1621=CARTESIAN_POINT('',(3.1295946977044,-7.32640866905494,12.7831703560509));
#1622=CARTESIAN_POINT('',(3.13517392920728,-7.28828265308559,12.8160281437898));
#1623=CARTESIAN_POINT('',(3.15033469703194,-7.2114799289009,12.8804680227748));
#1624=CARTESIAN_POINT('',(3.15993280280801,-7.17280158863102,12.91204423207));
#1625=CARTESIAN_POINT('',(3.18363635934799,-7.0946894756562,12.9737900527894));
#1626=CARTESIAN_POINT('',(3.19780618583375,-7.05525297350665,13.0039320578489));
#1627=CARTESIAN_POINT('',(3.23099360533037,-6.97660992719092,13.0616051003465));
#1628=CARTESIAN_POINT('',(3.25000198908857,-6.9374030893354,13.0891409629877));
#1629=CARTESIAN_POINT('',(3.29467930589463,-6.85719662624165,13.142465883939));
#1630=CARTESIAN_POINT('',(3.32069148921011,-6.81623899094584,13.1680367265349));
#1631=CARTESIAN_POINT('',(3.37901622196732,-6.73614117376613,13.2139908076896));
#1632=CARTESIAN_POINT('',(3.4113035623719,-6.69699447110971,13.2343940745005));
#1633=CARTESIAN_POINT('',(3.48277049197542,-6.62118746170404,13.2688653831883));
#1634=CARTESIAN_POINT('',(3.52203308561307,-6.584565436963,13.2828489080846));
#1635=CARTESIAN_POINT('',(3.6064324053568,-6.51614768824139,13.3026043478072));
#1636=CARTESIAN_POINT('',(3.6515637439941,-6.48434759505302,13.3083837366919));
#1637=CARTESIAN_POINT('',(3.7389606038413,-6.43145576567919,13.310831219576));
#1638=CARTESIAN_POINT('',(3.78066052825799,-6.40947559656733,13.3087220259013));
#1639=CARTESIAN_POINT('',(3.8656886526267,-6.37080198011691,13.2982544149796));
#1640=CARTESIAN_POINT('',(3.90901717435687,-6.35410958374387,13.2898947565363));
#1641=CARTESIAN_POINT('',(3.99417866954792,-6.32670722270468,13.2680967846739));
#1642=CARTESIAN_POINT('',(4.03600067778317,-6.31578128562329,13.2548791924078));
#1643=CARTESIAN_POINT('',(4.11901098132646,-6.29865129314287,13.2241979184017));
#1644=CARTESIAN_POINT('',(4.16019918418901,-6.29244792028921,13.2067336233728));
#1645=CARTESIAN_POINT('',(4.26416787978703,-6.28206793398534,13.1576132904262));
#1646=CARTESIAN_POINT('',(4.32609340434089,-6.28098265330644,13.1234932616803));
#1647=CARTESIAN_POINT('',(4.44603409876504,-6.28757607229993,13.0494427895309));
#1648=CARTESIAN_POINT('',(4.50403207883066,-6.29529095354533,13.0094889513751));
#1649=CARTESIAN_POINT('',(4.6054964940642,-6.3159824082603,12.9332722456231));
#1650=CARTESIAN_POINT('',(4.64969914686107,-6.32776150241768,12.8976400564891));
#1651=CARTESIAN_POINT('',(4.73465428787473,-6.35550491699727,12.8248019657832));
#1652=CARTESIAN_POINT('',(4.77543560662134,-6.37142834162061,12.7876142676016));
#1653=CARTESIAN_POINT('',(4.81471260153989,-6.38918027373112,12.7498073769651));
#1654=B_SPLINE_CURVE_WITH_KNOTS('',3,(#1620,#1621,#1622,#1623,#1624,#1625,#1626,#1627,#1628,
#1629,#1630,#1631,#1632,#1633,#1634,#1635,#1636,#1637,#1638,#1639,#1640,#1641,#1642,#1643,#1644,
#1645,#1646,#1647,#1648,#1649,#1650,#1651,#1652,#1653),.UNSPECIFIED.,.F.,.F.,(4,2,2,2,2,2,2,2,2,
2,2,2,2,2,2,2,4),(0.,0.151718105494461,0.304067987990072,0.458664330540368,0.612968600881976,
0.776960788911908,0.940307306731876,1.10574664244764,1.27103516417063,1.41184239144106,
1.55267758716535,1.68777657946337,1.82289509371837,2.03384499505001,2.24566534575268,
2.41934716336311,2.59137612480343),.UNSPECIFIED.);
#1655=CARTESIAN_POINT('',(4.81451260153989,-6.38908979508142,12.75));
#1656=VERTEX_POINT('',#1655);
#1657=EDGE_CURVE('E705',#1617,#1656,#1654,.T.);
#1658=ORIENTED_EDGE('',*,*,#1657,.T.);
#1659=CARTESIAN_POINT('',(0.,0.,12.75));
#1660=DIRECTION('',(0.,0.,-1.));
#1661=DIRECTION('',(-1.,0.,0.));
#1662=AXIS2_PLACEMENT_3D('',#1659,#1660,#1661);
#1663=CIRCLE('',#1662,8.);
#1664=CARTESIAN_POINT('',(6.38908979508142,-4.8145126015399,12.75));
#1665=VERTEX_POINT('',#1664);
#1666=EDGE_CURVE('E687',#1665,#1656,#1663,.T.);
#1667=ORIENTED_EDGE('',*,*,#1666,.F.);
#1668=CARTESIAN_POINT('',(6.38918027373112,-4.8147126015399,12.7498073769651));
#1669=CARTESIAN_POINT('',(6.37352002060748,-4.78007595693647,12.7831542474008));
#1670=CARTESIAN_POINT('',(6.35928827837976,-4.74426863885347,12.8160122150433));
#1671=CARTESIAN_POINT('',(6.33401548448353,-4.67017594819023,12.8804525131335));
#1672=CARTESIAN_POINT('',(6.32298796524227,-4.63188087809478,12.9120289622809));
#1673=CARTESIAN_POINT('',(6.30445860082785,-4.55238285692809,12.973775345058));
#1674=CARTESIAN_POINT('',(6.29701113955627,-4.51114535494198,13.0039176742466));
#1675=CARTESIAN_POINT('',(6.28642938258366,-4.4264455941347,13.0615914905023));
#1676=CARTESIAN_POINT('',(6.283286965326,-4.38298768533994,13.0891278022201));
#1677=CARTESIAN_POINT('',(6.28187376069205,-4.29118817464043,13.1424542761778));
#1678=CARTESIAN_POINT('',(6.28392131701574,-4.24271126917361,13.1680261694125));
#1679=CARTESIAN_POINT('',(6.29438152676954,-4.14418105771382,13.2139823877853));
#1680=CARTESIAN_POINT('',(6.30276908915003,-4.09413470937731,13.234386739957));
#1681=CARTESIAN_POINT('',(6.32675643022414,-3.99274893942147,13.2688602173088));
#1682=CARTESIAN_POINT('',(6.34244723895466,-3.94140116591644,13.2828448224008));
#1683=CARTESIAN_POINT('',(6.38132941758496,-3.8399480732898,13.3026022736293));
#1684=CARTESIAN_POINT('',(6.40451393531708,-3.78984166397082,13.3083825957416));
#1685=CARTESIAN_POINT('',(6.45375547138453,-3.70033582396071,13.3108315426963));
#1686=CARTESIAN_POINT('',(6.47887837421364,-3.66044977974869,13.3087229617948));
#1687=CARTESIAN_POINT('',(6.53317784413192,-3.58444196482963,13.2982564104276));
#1688=CARTESIAN_POINT('',(6.56235521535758,-3.54832094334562,13.2898971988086));
#1689=CARTESIAN_POINT('',(6.62240574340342,-3.48200812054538,13.2681000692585));
#1690=CARTESIAN_POINT('',(6.65316137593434,-3.45163470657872,13.2548829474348));
#1691=CARTESIAN_POINT('',(6.71648483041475,-3.39529396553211,13.2242025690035));
#1692=CARTESIAN_POINT('',(6.74905291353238,-3.36932727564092,13.2067386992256));
#1693=CARTESIAN_POINT('',(6.83390135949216,-3.30835313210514,13.1576196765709));
#1694=CARTESIAN_POINT('',(6.88698697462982,-3.27645022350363,13.1235005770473));
#1695=CARTESIAN_POINT('',(6.99415380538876,-3.22218923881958,13.0494519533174));
#1696=CARTESIAN_POINT('',(7.04823822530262,-3.19987109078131,13.0094990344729));
#1697=CARTESIAN_POINT('',(7.14645323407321,-3.16705734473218,12.9332841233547));
#1698=CARTESIAN_POINT('',(7.19062265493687,-3.15515658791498,12.8976528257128));
#1699=CARTESIAN_POINT('',(7.2780662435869,-3.13670454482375,12.824816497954));
#1700=CARTESIAN_POINT('',(7.32134493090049,-3.13010342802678,12.7876296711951));
#1701=CARTESIAN_POINT('',(7.36423511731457,-3.1258379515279,12.7498236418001));
#1702=B_SPLINE_CURVE_WITH_KNOTS('',3,(#1668,#1669,#1670,#1671,#1672,#1673,#1674,#1675,#1676,
#1677,#1678,#1679,#1680,#1681,#1682,#1683,#1684,#1685,#1686,#1687,#1688,#1689,#1690,#1691,#1692,
#1693,#1694,#1695,#1696,#1697,#1698,#1699,#1700,#1701),.UNSPECIFIED.,.F.,.F.,(4,2,2,2,2,2,2,2,2,
2,2,2,2,2,2,2,4),(0.,0.151718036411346,0.304067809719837,0.458663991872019,0.612968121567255,
0.7769629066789,0.940312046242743,1.10575410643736,1.27104531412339,1.4118538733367,
1.55269039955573,1.68778886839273,1.82290685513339,2.03385393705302,2.24567145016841,
2.41935018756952,2.59137610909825),.UNSPECIFIED.);
#1703=CARTESIAN_POINT('',(7.36403511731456,-3.12585776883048,12.75));
#1704=VERTEX_POINT('',#1703);
#1705=EDGE_CURVE('E680',#1665,#1704,#1702,.T.);
#1706=ORIENTED_EDGE('',*,*,#1705,.T.);
#1707=CARTESIAN_POINT('',(0.,0.,12.7500000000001));
#1708=DIRECTION('',(0.,0.,-1.));
#1709=DIRECTION('',(-1.,0.,0.));
#1710=AXIS2_PLACEMENT_3D('',#1707,#1708,#1709);
#1711=CIRCLE('',#1710,7.99999999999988);
#1712=CARTESIAN_POINT('',(7.94037037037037,-0.974945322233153,12.7500000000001));
#1713=VERTEX_POINT('',#1712);
#1714=EDGE_CURVE('E678',#1713,#1704,#1711,.T.);
#1715=ORIENTED_EDGE('',*,*,#1714,.F.);
#1716=CARTESIAN_POINT('',(7.94057037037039,-0.975088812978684,12.7497840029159));
#1717=CARTESIAN_POINT('',(7.90968957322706,-0.952923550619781,12.7831310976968));
#1718=CARTESIAN_POINT('',(7.87946053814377,-0.929030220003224,12.815989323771));
#1719=CARTESIAN_POINT('',(7.82052659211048,-0.877502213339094,12.880430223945));
#1720=CARTESIAN_POINT('',(7.79182855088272,-0.849852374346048,12.9120070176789));
#1721=CARTESIAN_POINT('',(7.73603175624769,-0.790271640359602,12.9737542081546));
#1722=CARTESIAN_POINT('',(7.70896282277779,-0.758283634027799,13.0038970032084));
#1723=CARTESIAN_POINT('',(7.657447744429,-0.690224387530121,13.0615719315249));
#1724=CARTESIAN_POINT('',(7.63299674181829,-0.65416097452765,13.0891088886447));
#1725=CARTESIAN_POINT('',(7.58587103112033,-0.575368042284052,13.14243759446));
#1726=CARTESIAN_POINT('',(7.56340444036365,-0.532362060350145,13.1680109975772));
#1727=CARTESIAN_POINT('',(7.52319538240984,-0.441802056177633,13.2139702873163));
#1728=CARTESIAN_POINT('',(7.50543466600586,-0.394266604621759,13.234376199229));
#1729=CARTESIAN_POINT('',(7.4755126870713,-0.294469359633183,13.2688527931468));
#1730=CARTESIAN_POINT('',(7.46342608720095,-0.242154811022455,13.2828389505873));
#1731=CARTESIAN_POINT('',(7.4463699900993,-0.134851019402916,13.3025992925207));
#1732=CARTESIAN_POINT('',(7.44139401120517,-0.0798642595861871,13.3083809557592));
#1733=CARTESIAN_POINT('',(7.43928370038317,0.0222726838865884,13.3108320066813));
#1734=CARTESIAN_POINT('',(7.44109699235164,0.0693771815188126,13.3087243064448));
#1735=CARTESIAN_POINT('',(7.45011649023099,0.162353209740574,13.298259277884));
#1736=CARTESIAN_POINT('',(7.45732376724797,0.208224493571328,13.2899007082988));
#1737=CARTESIAN_POINT('',(7.47617158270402,0.295679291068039,13.2681047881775));
#1738=CARTESIAN_POINT('',(7.48761944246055,0.337361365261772,13.254888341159));
#1739=CARTESIAN_POINT('',(7.5142876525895,0.417815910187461,13.2242092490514));
#1740=CARTESIAN_POINT('',(7.52950854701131,0.456587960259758,13.2067459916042));
#1741=CARTESIAN_POINT('',(7.57250068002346,0.551817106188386,13.1576288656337));
#1742=CARTESIAN_POINT('',(7.60252148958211,0.605988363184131,13.1235111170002));
#1743=CARTESIAN_POINT('',(7.6681977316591,0.706562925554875,13.0494651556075));
#1744=CARTESIAN_POINT('',(7.70387590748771,0.752933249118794,13.0095135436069));
#1745=CARTESIAN_POINT('',(7.77253186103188,0.830468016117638,12.9332916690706));
#1746=CARTESIAN_POINT('',(7.80484143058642,0.862867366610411,12.8976514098));
#1747=CARTESIAN_POINT('',(7.87136090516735,0.922583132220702,12.824796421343));
#1748=CARTESIAN_POINT('',(7.90554979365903,0.949944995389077,12.7875999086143));
#1749=CARTESIAN_POINT('',(7.94057037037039,0.975088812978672,12.7497840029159));
#1750=B_SPLINE_CURVE_WITH_KNOTS('',3,(#1716,#1717,#1718,#1719,#1720,#1721,#1722,#1723,#1724,
#1725,#1726,#1727,#1728,#1729,#1730,#1731,#1732,#1733,#1734,#1735,#1736,#1737,#1738,#1739,#1740,
#1741,#1742,#1743,#1744,#1745,#1746,#1747,#1748,#1749),.UNSPECIFIED.,.F.,.F.,(4,2,2,2,2,2,2,2,2,
2,2,2,2,2,2,2,4),(0.,0.151717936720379,0.304067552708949,0.4586635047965,0.612967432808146,
0.776965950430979,0.940318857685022,1.1057648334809,1.27105990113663,1.41187037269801,
1.55270881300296,1.68780653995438,1.82292375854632,2.03386670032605,2.24568022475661,
2.41940268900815,2.59147151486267),.UNSPECIFIED.);
#1751=CARTESIAN_POINT('',(7.94037037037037,0.97494532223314,12.75));
#1752=VERTEX_POINT('',#1751);
#1753=EDGE_CURVE('E671',#1713,#1752,#1750,.T.);
#1754=ORIENTED_EDGE('',*,*,#1753,.T.);
#1755=CARTESIAN_POINT('',(0.,0.,12.7500000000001));
#1756=DIRECTION('',(0.,0.,-1.));
#1757=DIRECTION('',(-1.,0.,0.));
#1758=AXIS2_PLACEMENT_3D('',#1755,#1756,#1757);
#1759=CIRCLE('',#1758,7.99999999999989);
#1760=CARTESIAN_POINT('',(7.36403511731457,3.12585776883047,12.7500000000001));
#1761=VERTEX_POINT('',#1760);
#1762=EDGE_CURVE('E653',#1761,#1752,#1759,.T.);
#1763=ORIENTED_EDGE('',*,*,#1762,.F.);
#1764=CARTESIAN_POINT('',(7.36423511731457,3.12583795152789,12.7498236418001));
#1765=CARTESIAN_POINT('',(7.32640866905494,3.1295946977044,12.7831703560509));
#1766=CARTESIAN_POINT('',(7.28828265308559,3.13517392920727,12.8160281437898));
#1767=CARTESIAN_POINT('',(7.2114799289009,3.15033469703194,12.8804680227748));
#1768=CARTESIAN_POINT('',(7.17280158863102,3.15993280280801,12.91204423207));
#1769=CARTESIAN_POINT('',(7.0946894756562,3.18363635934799,12.9737900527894));
#1770=CARTESIAN_POINT('',(7.05525297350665,3.19780618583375,13.0039320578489));
#1771=CARTESIAN_POINT('',(6.97660992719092,3.23099360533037,13.0616051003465));
#1772=CARTESIAN_POINT('',(6.9374030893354,3.25000198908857,13.0891409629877));
#1773=CARTESIAN_POINT('',(6.85719662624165,3.29467930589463,13.142465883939));
#1774=CARTESIAN_POINT('',(6.81623899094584,3.32069148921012,13.1680367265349));
#1775=CARTESIAN_POINT('',(6.73614117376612,3.37901622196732,13.2139908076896));
#1776=CARTESIAN_POINT('',(6.6969944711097,3.4113035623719,13.2343940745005));
#1777=CARTESIAN_POINT('',(6.62118746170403,3.48277049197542,13.2688653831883));
#1778=CARTESIAN_POINT('',(6.584565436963,3.52203308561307,13.2828489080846));
#1779=CARTESIAN_POINT('',(6.51614768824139,3.60643240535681,13.3026043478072));
#1780=CARTESIAN_POINT('',(6.48434759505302,3.6515637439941,13.3083837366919));
#1781=CARTESIAN_POINT('',(6.43145576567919,3.7389606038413,13.310831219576));
#1782=CARTESIAN_POINT('',(6.40947559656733,3.78066052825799,13.3087220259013));
#1783=CARTESIAN_POINT('',(6.37080198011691,3.8656886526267,13.2982544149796));
#1784=CARTESIAN_POINT('',(6.35410958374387,3.90901717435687,13.2898947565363));
#1785=CARTESIAN_POINT('',(6.32670722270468,3.99417866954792,13.2680967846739));
#1786=CARTESIAN_POINT('',(6.31578128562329,4.03600067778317,13.2548791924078));
#1787=CARTESIAN_POINT('',(6.29865129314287,4.11901098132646,13.2241979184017));
#1788=CARTESIAN_POINT('',(6.29244792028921,4.16019918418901,13.2067336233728));
#1789=CARTESIAN_POINT('',(6.28206793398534,4.26416787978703,13.1576132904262));
#1790=CARTESIAN_POINT('',(6.28098265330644,4.32609340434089,13.1234932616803));
#1791=CARTESIAN_POINT('',(6.28757607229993,4.44603409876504,13.0494427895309));
#1792=CARTESIAN_POINT('',(6.29529095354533,4.50403207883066,13.0094889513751));
#1793=CARTESIAN_POINT('',(6.3159824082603,4.6054964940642,12.9332722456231));
#1794=CARTESIAN_POINT('',(6.32776150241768,4.64969914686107,12.8976400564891));
#1795=CARTESIAN_POINT('',(6.35550491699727,4.73465428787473,12.8248019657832));
#1796=CARTESIAN_POINT('',(6.37142834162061,4.77543560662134,12.7876142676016));
#1797=CARTESIAN_POINT('',(6.38918027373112,4.81471260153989,12.7498073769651));
#1798=B_SPLINE_CURVE_WITH_KNOTS('',3,(#1764,#1765,#1766,#1767,#1768,#1769,#1770,#1771,#1772,
#1773,#1774,#1775,#1776,#1777,#1778,#1779,#1780,#1781,#1782,#1783,#1784,#1785,#1786,#1787,#1788,
#1789,#1790,#1791,#1792,#1793,#1794,#1795,#1796,#1797),.UNSPECIFIED.,.F.,.F.,(4,2,2,2,2,2,2,2,2,
2,2,2,2,2,2,2,4),(0.,0.151718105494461,0.30406798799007,0.458664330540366,0.612968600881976,
0.776960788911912,0.940307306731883,1.10574664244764,1.27103516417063,1.41184239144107,
1.55267758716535,1.68777657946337,1.82289509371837,2.03384499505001,2.24566534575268,
2.41934716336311,2.59137612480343),.UNSPECIFIED.);
#1799=CARTESIAN_POINT('',(6.38908979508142,4.81451260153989,12.75));
#1800=VERTEX_POINT('',#1799);
#1801=EDGE_CURVE('E646',#1761,#1800,#1798,.T.);
#1802=ORIENTED_EDGE('',*,*,#1801,.T.);
#1803=CARTESIAN_POINT('',(0.,0.,12.75));
#1804=DIRECTION('',(0.,0.,-1.));
#1805=DIRECTION('',(-1.,0.,0.));
#1806=AXIS2_PLACEMENT_3D('',#1803,#1804,#1805);
#1807=CIRCLE('',#1806,7.9999999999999);
#1808=CARTESIAN_POINT('',(4.8145126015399,6.38908979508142,12.75));
#1809=VERTEX_POINT('',#1808);
#1810=EDGE_CURVE('E644',#1809,#1800,#1807,.T.);
#1811=ORIENTED_EDGE('',*,*,#1810,.F.);
#1812=CARTESIAN_POINT('',(4.8147126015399,6.38918027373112,12.7498073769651));
#1813=CARTESIAN_POINT('',(4.78007595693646,6.37352002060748,12.7831542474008));
#1814=CARTESIAN_POINT('',(4.74426863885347,6.35928827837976,12.8160122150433));
#1815=CARTESIAN_POINT('',(4.67017594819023,6.33401548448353,12.8804525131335));
#1816=CARTESIAN_POINT('',(4.63188087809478,6.32298796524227,12.9120289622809));
#1817=CARTESIAN_POINT('',(4.55238285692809,6.30445860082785,12.973775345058));
#1818=CARTESIAN_POINT('',(4.51114535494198,6.29701113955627,13.0039176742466));
#1819=CARTESIAN_POINT('',(4.4264455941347,6.28642938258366,13.0615914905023));
#1820=CARTESIAN_POINT('',(4.38298768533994,6.283286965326,13.0891278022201));
#1821=CARTESIAN_POINT('',(4.29118817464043,6.28187376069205,13.1424542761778));
#1822=CARTESIAN_POINT('',(4.24271126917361,6.28392131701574,13.1680261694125));
#1823=CARTESIAN_POINT('',(4.14418105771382,6.29438152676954,13.2139823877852));
#1824=CARTESIAN_POINT('',(4.09413470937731,6.30276908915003,13.234386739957));
#1825=CARTESIAN_POINT('',(3.99274893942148,6.32675643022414,13.2688602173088));
#1826=CARTESIAN_POINT('',(3.94140116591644,6.34244723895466,13.2828448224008));
#1827=CARTESIAN_POINT('',(3.8399480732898,6.38132941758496,13.3026022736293));
#1828=CARTESIAN_POINT('',(3.78984166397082,6.40451393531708,13.3083825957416));
#1829=CARTESIAN_POINT('',(3.70033582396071,6.45375547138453,13.3108315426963));
#1830=CARTESIAN_POINT('',(3.66044977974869,6.47887837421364,13.3087229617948));
#1831=CARTESIAN_POINT('',(3.58444196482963,6.53317784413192,13.2982564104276));
#1832=CARTESIAN_POINT('',(3.54832094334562,6.56235521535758,13.2898971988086));
#1833=CARTESIAN_POINT('',(3.48200812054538,6.62240574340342,13.2681000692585));
#1834=CARTESIAN_POINT('',(3.45163470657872,6.65316137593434,13.2548829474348));
#1835=CARTESIAN_POINT('',(3.39529396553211,6.71648483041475,13.2242025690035));
#1836=CARTESIAN_POINT('',(3.36932727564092,6.74905291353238,13.2067386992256));
#1837=CARTESIAN_POINT('',(3.30835313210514,6.83390135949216,13.1576196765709));
#1838=CARTESIAN_POINT('',(3.27645022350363,6.88698697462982,13.1235005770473));
#1839=CARTESIAN_POINT('',(3.22218923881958,6.99415380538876,13.0494519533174));
#1840=CARTESIAN_POINT('',(3.19987109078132,7.04823822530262,13.0094990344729));
#1841=CARTESIAN_POINT('',(3.16705734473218,7.14645323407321,12.9332841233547));
#1842=CARTESIAN_POINT('',(3.15515658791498,7.19062265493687,12.8976528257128));
#1843=CARTESIAN_POINT('',(3.13670454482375,7.2780662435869,12.8248164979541));
#1844=CARTESIAN_POINT('',(3.13010342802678,7.32134493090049,12.7876296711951));
#1845=CARTESIAN_POINT('',(3.1258379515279,7.36423511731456,12.7498236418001));
#1846=B_SPLINE_CURVE_WITH_KNOTS('',3,(#1812,#1813,#1814,#1815,#1816,#1817,#1818,#1819,#1820,
#1821,#1822,#1823,#1824,#1825,#1826,#1827,#1828,#1829,#1830,#1831,#1832,#1833,#1834,#1835,#1836,
#1837,#1838,#1839,#1840,#1841,#1842,#1843,#1844,#1845),.UNSPECIFIED.,.F.,.F.,(4,2,2,2,2,2,2,2,2,
2,2,2,2,2,2,2,4),(0.,0.151718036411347,0.304067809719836,0.458663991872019,0.612968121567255,
0.776962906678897,0.940312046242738,1.10575410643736,1.27104531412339,1.4118538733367,
1.55269039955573,1.68778886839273,1.82290685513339,2.03385393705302,2.24567145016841,
2.41935018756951,2.59137610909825),.UNSPECIFIED.);
#1847=CARTESIAN_POINT('',(3.12585776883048,7.36403511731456,12.75));
#1848=VERTEX_POINT('',#1847);
#1849=EDGE_CURVE('E637',#1809,#1848,#1846,.T.);
#1850=ORIENTED_EDGE('',*,*,#1849,.T.);
#1851=CARTESIAN_POINT('',(0.,0.,12.75));
#1852=DIRECTION('',(0.,0.,-1.));
#1853=DIRECTION('',(-1.,0.,0.));
#1854=AXIS2_PLACEMENT_3D('',#1851,#1852,#1853);
#1855=CIRCLE('',#1854,8.);
#1856=CARTESIAN_POINT('',(0.974945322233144,7.94037037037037,12.75));
#1857=VERTEX_POINT('',#1856);
#1858=EDGE_CURVE('E619',#1857,#1848,#1855,.T.);
#1859=ORIENTED_EDGE('',*,*,#1858,.F.);
#1860=CARTESIAN_POINT('',(0.975088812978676,7.94057037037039,12.7497840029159));
#1861=CARTESIAN_POINT('',(0.952923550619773,7.90968957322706,12.7831310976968));
#1862=CARTESIAN_POINT('',(0.929030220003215,7.87946053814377,12.815989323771));
#1863=CARTESIAN_POINT('',(0.877502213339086,7.82052659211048,12.880430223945));
#1864=CARTESIAN_POINT('',(0.84985237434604,7.79182855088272,12.9120070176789));
#1865=CARTESIAN_POINT('',(0.790271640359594,7.73603175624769,12.9737542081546));
#1866=CARTESIAN_POINT('',(0.75828363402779,7.70896282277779,13.0038970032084));
#1867=CARTESIAN_POINT('',(0.690224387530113,7.657447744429,13.0615719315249));
#1868=CARTESIAN_POINT('',(0.654160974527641,7.63299674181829,13.0891088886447));
#1869=CARTESIAN_POINT('',(0.575368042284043,7.58587103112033,13.14243759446));
#1870=CARTESIAN_POINT('',(0.532362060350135,7.56340444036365,13.1680109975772));
#1871=CARTESIAN_POINT('',(0.441802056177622,7.52319538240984,13.2139702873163));
#1872=CARTESIAN_POINT('',(0.394266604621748,7.50543466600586,13.234376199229));
#1873=CARTESIAN_POINT('',(0.294469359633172,7.4755126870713,13.2688527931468));
#1874=CARTESIAN_POINT('',(0.242154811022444,7.46342608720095,13.2828389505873));
#1875=CARTESIAN_POINT('',(0.134851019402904,7.4463699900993,13.3025992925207));
#1876=CARTESIAN_POINT('',(0.0798642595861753,7.44139401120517,13.3083809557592));
#1877=CARTESIAN_POINT('',(-0.0222726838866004,7.43928370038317,13.3108320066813));
#1878=CARTESIAN_POINT('',(-0.0693771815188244,7.44109699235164,13.3087243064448));
#1879=CARTESIAN_POINT('',(-0.162353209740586,7.45011649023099,13.298259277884));
#1880=CARTESIAN_POINT('',(-0.208224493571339,7.45732376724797,13.2899007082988));
#1881=CARTESIAN_POINT('',(-0.29567929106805,7.47617158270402,13.2681047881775));
#1882=CARTESIAN_POINT('',(-0.337361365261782,7.48761944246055,13.254888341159));
#1883=CARTESIAN_POINT('',(-0.417815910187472,7.5142876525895,13.2242092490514));
#1884=CARTESIAN_POINT('',(-0.45658796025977,7.52950854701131,13.2067459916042));
#1885=CARTESIAN_POINT('',(-0.551817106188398,7.57250068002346,13.1576288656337));
#1886=CARTESIAN_POINT('',(-0.605988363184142,7.60252148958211,13.1235111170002));
#1887=CARTESIAN_POINT('',(-0.706562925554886,7.66819773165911,13.0494651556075));
#1888=CARTESIAN_POINT('',(-0.752933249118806,7.70387590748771,13.0095135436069));
#1889=CARTESIAN_POINT('',(-0.83046801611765,7.77253186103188,12.9332916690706));
#1890=CARTESIAN_POINT('',(-0.862867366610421,7.80484143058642,12.8976514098));
#1891=CARTESIAN_POINT('',(-0.922583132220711,7.87136090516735,12.824796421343));
#1892=CARTESIAN_POINT('',(-0.949944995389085,7.90554979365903,12.7875999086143));
#1893=CARTESIAN_POINT('',(-0.975088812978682,7.94057037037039,12.7497840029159));
#1894=B_SPLINE_CURVE_WITH_KNOTS('',3,(#1860,#1861,#1862,#1863,#1864,#1865,#1866,#1867,#1868,
#1869,#1870,#1871,#1872,#1873,#1874,#1875,#1876,#1877,#1878,#1879,#1880,#1881,#1882,#1883,#1884,
#1885,#1886,#1887,#1888,#1889,#1890,#1891,#1892,#1893),.UNSPECIFIED.,.F.,.F.,(4,2,2,2,2,2,2,2,2,
2,2,2,2,2,2,2,4),(0.,0.151717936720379,0.304067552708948,0.4586635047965,0.612967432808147,
0.776965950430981,0.940318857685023,1.10576483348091,1.27105990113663,1.41187037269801,
1.55270881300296,1.68780653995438,1.82292375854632,2.03386670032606,2.24568022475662,
2.41940268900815,2.59147151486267),.UNSPECIFIED.);
#1895=CARTESIAN_POINT('',(-0.974945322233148,7.94037037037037,12.75));
#1896=VERTEX_POINT('',#1895);
#1897=EDGE_CURVE('E613',#1857,#1896,#1894,.T.);
#1898=ORIENTED_EDGE('',*,*,#1897,.T.);
#1899=CARTESIAN_POINT('',(0.,0.,12.7500000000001));
#1900=DIRECTION('',(0.,0.,-1.));
#1901=DIRECTION('',(-1.,0.,0.));
#1902=AXIS2_PLACEMENT_3D('',#1899,#1900,#1901);
#1903=CIRCLE('',#1902,7.99999999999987);
#1904=CARTESIAN_POINT('',(-3.12585776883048,7.36403511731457,12.7500000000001));
#1905=VERTEX_POINT('',#1904);
#1906=EDGE_CURVE('E608',#1905,#1896,#1903,.T.);
#1907=ORIENTED_EDGE('',*,*,#1906,.F.);
#1908=CARTESIAN_POINT('',(-3.1258379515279,7.36423511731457,12.7498236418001));
#1909=CARTESIAN_POINT('',(-3.1295946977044,7.32640866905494,12.7831703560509));
#1910=CARTESIAN_POINT('',(-3.13517392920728,7.28828265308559,12.8160281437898));
#1911=CARTESIAN_POINT('',(-3.15033469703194,7.2114799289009,12.8804680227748));
#1912=CARTESIAN_POINT('',(-3.15993280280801,7.17280158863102,12.91204423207));
#1913=CARTESIAN_POINT('',(-3.18363635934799,7.0946894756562,12.9737900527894));
#1914=CARTESIAN_POINT('',(-3.19780618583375,7.05525297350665,13.0039320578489));
#1915=CARTESIAN_POINT('',(-3.23099360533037,6.97660992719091,13.0616051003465));
#1916=CARTESIAN_POINT('',(-3.25000198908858,6.9374030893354,13.0891409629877));
#1917=CARTESIAN_POINT('',(-3.29467930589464,6.85719662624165,13.142465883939));
#1918=CARTESIAN_POINT('',(-3.32069148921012,6.81623899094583,13.1680367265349));
#1919=CARTESIAN_POINT('',(-3.37901622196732,6.73614117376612,13.2139908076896));
#1920=CARTESIAN_POINT('',(-3.4113035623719,6.6969944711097,13.2343940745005));
#1921=CARTESIAN_POINT('',(-3.48277049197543,6.62118746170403,13.2688653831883));
#1922=CARTESIAN_POINT('',(-3.52203308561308,6.584565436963,13.2828489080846));
#1923=CARTESIAN_POINT('',(-3.60643240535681,6.51614768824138,13.3026043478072));
#1924=CARTESIAN_POINT('',(-3.65156374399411,6.48434759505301,13.3083837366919));
#1925=CARTESIAN_POINT('',(-3.73896060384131,6.43145576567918,13.310831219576));
#1926=CARTESIAN_POINT('',(-3.780660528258,6.40947559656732,13.3087220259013));
#1927=CARTESIAN_POINT('',(-3.86568865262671,6.37080198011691,13.2982544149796));
#1928=CARTESIAN_POINT('',(-3.90901717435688,6.35410958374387,13.2898947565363));
#1929=CARTESIAN_POINT('',(-3.99417866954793,6.32670722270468,13.2680967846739));
#1930=CARTESIAN_POINT('',(-4.03600067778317,6.31578128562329,13.2548791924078));
#1931=CARTESIAN_POINT('',(-4.11901098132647,6.29865129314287,13.2241979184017));
#1932=CARTESIAN_POINT('',(-4.16019918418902,6.29244792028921,13.2067336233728));
#1933=CARTESIAN_POINT('',(-4.26416787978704,6.28206793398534,13.1576132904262));
#1934=CARTESIAN_POINT('',(-4.32609340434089,6.28098265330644,13.1234932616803));
#1935=CARTESIAN_POINT('',(-4.44603409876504,6.28757607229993,13.0494427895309));
#1936=CARTESIAN_POINT('',(-4.50403207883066,6.29529095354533,13.0094889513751));
#1937=CARTESIAN_POINT('',(-4.6054964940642,6.3159824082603,12.9332722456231));
#1938=CARTESIAN_POINT('',(-4.64969914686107,6.32776150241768,12.8976400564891));
#1939=CARTESIAN_POINT('',(-4.73465428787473,6.35550491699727,12.8248019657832));
#1940=CARTESIAN_POINT('',(-4.77543560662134,6.37142834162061,12.7876142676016));
#1941=CARTESIAN_POINT('',(-4.8147126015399,6.38918027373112,12.7498073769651));
#1942=B_SPLINE_CURVE_WITH_KNOTS('',3,(#1908,#1909,#1910,#1911,#1912,#1913,#1914,#1915,#1916,
#1917,#1918,#1919,#1920,#1921,#1922,#1923,#1924,#1925,#1926,#1927,#1928,#1929,#1930,#1931,#1932,
#1933,#1934,#1935,#1936,#1937,#1938,#1939,#1940,#1941),.UNSPECIFIED.,.F.,.F.,(4,2,2,2,2,2,2,2,2,
2,2,2,2,2,2,2,4),(0.,0.151718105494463,0.304067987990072,0.458664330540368,0.612968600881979,
0.776960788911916,0.940307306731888,1.10574664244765,1.27103516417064,1.41184239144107,
1.55267758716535,1.68777657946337,1.82289509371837,2.03384499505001,2.24566534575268,
2.41934716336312,2.59137612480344),.UNSPECIFIED.);
#1943=CARTESIAN_POINT('',(-4.8145126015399,6.38908979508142,12.75));
#1944=VERTEX_POINT('',#1943);
#1945=EDGE_CURVE('E601',#1905,#1944,#1942,.T.);
#1946=ORIENTED_EDGE('',*,*,#1945,.T.);
#1947=CARTESIAN_POINT('',(0.,0.,12.75));
#1948=DIRECTION('',(0.,0.,-1.));
#1949=DIRECTION('',(-1.,0.,0.));
#1950=AXIS2_PLACEMENT_3D('',#1947,#1948,#1949);
#1951=CIRCLE('',#1950,8.);
#1952=CARTESIAN_POINT('',(-6.38908979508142,4.8145126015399,12.75));
#1953=VERTEX_POINT('',#1952);
#1954=EDGE_CURVE('E583',#1953,#1944,#1951,.T.);
#1955=ORIENTED_EDGE('',*,*,#1954,.F.);
#1956=CARTESIAN_POINT('',(-6.38918027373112,4.8147126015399,12.7498073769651));
#1957=CARTESIAN_POINT('',(-6.37352002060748,4.78007595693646,12.7831542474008));
#1958=CARTESIAN_POINT('',(-6.35928827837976,4.74426863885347,12.8160122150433));
#1959=CARTESIAN_POINT('',(-6.33401548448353,4.67017594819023,12.8804525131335));
#1960=CARTESIAN_POINT('',(-6.32298796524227,4.63188087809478,12.9120289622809));
#1961=CARTESIAN_POINT('',(-6.30445860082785,4.55238285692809,12.973775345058));
#1962=CARTESIAN_POINT('',(-6.29701113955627,4.51114535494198,13.0039176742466));
#1963=CARTESIAN_POINT('',(-6.28642938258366,4.4264455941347,13.0615914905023));
#1964=CARTESIAN_POINT('',(-6.28328696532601,4.38298768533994,13.0891278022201));
#1965=CARTESIAN_POINT('',(-6.28187376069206,4.29118817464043,13.1424542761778));
#1966=CARTESIAN_POINT('',(-6.28392131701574,4.24271126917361,13.1680261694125));
#1967=CARTESIAN_POINT('',(-6.29438152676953,4.14418105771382,13.2139823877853));
#1968=CARTESIAN_POINT('',(-6.30276908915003,4.0941347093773,13.234386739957));
#1969=CARTESIAN_POINT('',(-6.32675643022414,3.99274893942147,13.2688602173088));
#1970=CARTESIAN_POINT('',(-6.34244723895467,3.94140116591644,13.2828448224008));
#1971=CARTESIAN_POINT('',(-6.38132941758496,3.83994807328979,13.3026022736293));
#1972=CARTESIAN_POINT('',(-6.40451393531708,3.78984166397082,13.3083825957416));
#1973=CARTESIAN_POINT('',(-6.45375547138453,3.70033582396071,13.3108315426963));
#1974=CARTESIAN_POINT('',(-6.47887837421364,3.66044977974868,13.3087229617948));
#1975=CARTESIAN_POINT('',(-6.53317784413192,3.58444196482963,13.2982564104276));
#1976=CARTESIAN_POINT('',(-6.56235521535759,3.54832094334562,13.2898971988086));
#1977=CARTESIAN_POINT('',(-6.62240574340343,3.48200812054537,13.2681000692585));
#1978=CARTESIAN_POINT('',(-6.65316137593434,3.45163470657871,13.2548829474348));
#1979=CARTESIAN_POINT('',(-6.71648483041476,3.39529396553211,13.2242025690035));
#1980=CARTESIAN_POINT('',(-6.74905291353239,3.36932727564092,13.2067386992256));
#1981=CARTESIAN_POINT('',(-6.83390135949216,3.30835313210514,13.1576196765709));
#1982=CARTESIAN_POINT('',(-6.88698697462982,3.27645022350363,13.1235005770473));
#1983=CARTESIAN_POINT('',(-6.99415380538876,3.22218923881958,13.0494519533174));
#1984=CARTESIAN_POINT('',(-7.04823822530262,3.19987109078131,13.0094990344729));
#1985=CARTESIAN_POINT('',(-7.14645323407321,3.16705734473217,12.9332841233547));
#1986=CARTESIAN_POINT('',(-7.19062265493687,3.15515658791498,12.8976528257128));
#1987=CARTESIAN_POINT('',(-7.27806624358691,3.13670454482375,12.824816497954));
#1988=CARTESIAN_POINT('',(-7.3213449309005,3.13010342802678,12.7876296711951));
#1989=CARTESIAN_POINT('',(-7.36423511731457,3.1258379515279,12.7498236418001));
#1990=B_SPLINE_CURVE_WITH_KNOTS('',3,(#1956,#1957,#1958,#1959,#1960,#1961,#1962,#1963,#1964,
#1965,#1966,#1967,#1968,#1969,#1970,#1971,#1972,#1973,#1974,#1975,#1976,#1977,#1978,#1979,#1980,
#1981,#1982,#1983,#1984,#1985,#1986,#1987,#1988,#1989),.UNSPECIFIED.,.F.,.F.,(4,2,2,2,2,2,2,2,2,
2,2,2,2,2,2,2,4),(0.,0.151718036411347,0.304067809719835,0.45866399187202,0.612968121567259,
0.776962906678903,0.940312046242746,1.10575410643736,1.27104531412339,1.4118538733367,
1.55269039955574,1.68778886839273,1.82290685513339,2.03385393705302,2.24567145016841,
2.41935018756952,2.59137610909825),.UNSPECIFIED.);
#1991=EDGE_CURVE('E576',#1953,#1425,#1990,.T.);
#1992=ORIENTED_EDGE('',*,*,#1991,.T.);
#1993=EDGE_LOOP('',(#1427,#1466,#1475,#1514,#1523,#1562,#1571,#1610,#1619,#1658,#1667,#1706,
#1715,#1754,#1763,#1802,#1811,#1850,#1859,#1898,#1907,#1946,#1955,#1992));
#1994=FACE_BOUND('',#1993,.T.);
#1995=ADVANCED_FACE('F466',(#1416,#1994),#1413,.T.);
#1996=CARTESIAN_POINT('',(-7.48245948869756,-4.32,5.));
#1997=DIRECTION('',(0.,0.,1.));
#1998=DIRECTION('',(1.,0.,0.));
#1999=AXIS2_PLACEMENT_3D('',#1996,#1997,#1998);
#2000=CYLINDRICAL_SURFACE('',#1999,1.2);
#2001=DIRECTION('',(0.,0.,1.));
#2002=VECTOR('',#2001,1.);
#2003=CARTESIAN_POINT('',(-6.38908979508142,-4.81451260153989,5.));
#2004=LINE('',#2003,#2002);
#2005=EDGE_CURVE('E42',#1315,#1512,#2004,.T.);
#2006=ORIENTED_EDGE('',*,*,#2005,.T.);
#2007=ORIENTED_EDGE('',*,*,#1513,.F.);
#2008=DIRECTION('',(0.,0.,1.));
#2009=VECTOR('',#2008,1.);
#2010=CARTESIAN_POINT('',(-7.36403511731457,-3.12585776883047,5.));
#2011=LINE('',#2010,#2009);
#2012=EDGE_CURVE('E295',#1324,#1473,#2011,.T.);
#2013=ORIENTED_EDGE('',*,*,#2012,.F.);
#2014=ORIENTED_EDGE('',*,*,#1325,.F.);
#2015=EDGE_LOOP('',(#2006,#2007,#2013,#2014));
#2016=FACE_BOUND('',#2015,.T.);
#2017=ADVANCED_FACE('F470',(#2016),#2000,.F.);
#2018=CARTESIAN_POINT('',(0.,0.,5.));
#2019=DIRECTION('',(0.,0.,1.));
#2020=DIRECTION('',(1.,0.,0.));
#2021=AXIS2_PLACEMENT_3D('',#2018,#2019,#2020);
#2022=CYLINDRICAL_SURFACE('',#2021,8.);
#2023=ORIENTED_EDGE('',*,*,#1316,.T.);
#2024=DIRECTION('',(0.,0.,1.));
#2025=VECTOR('',#2024,1.);
#2026=CARTESIAN_POINT('',(-4.8145126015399,-6.38908979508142,5.));
#2027=LINE('',#2026,#2025);
#2028=EDGE_CURVE('E357',#1306,#1521,#2027,.T.);
#2029=ORIENTED_EDGE('',*,*,#2028,.T.);
#2030=ORIENTED_EDGE('',*,*,#1522,.T.);
#2031=ORIENTED_EDGE('',*,*,#2005,.F.);
#2032=EDGE_LOOP('',(#2023,#2029,#2030,#2031));
#2033=FACE_BOUND('',#2032,.T.);
#2034=ADVANCED_FACE('F475',(#2033),#2022,.T.);
#2035=CARTESIAN_POINT('',(-4.32,-7.48245948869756,5.));
#2036=DIRECTION('',(0.,0.,1.));
#2037=DIRECTION('',(1.,0.,0.));
#2038=AXIS2_PLACEMENT_3D('',#2035,#2036,#2037);
#2039=CYLINDRICAL_SURFACE('',#2038,1.2);
#2040=DIRECTION('',(0.,0.,1.));
#2041=VECTOR('',#2040,1.);
#2042=CARTESIAN_POINT('',(-3.12585776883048,-7.36403511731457,5.));
#2043=LINE('',#2042,#2041);
#2044=EDGE_CURVE('E354',#1297,#1560,#2043,.T.);
#2045=ORIENTED_EDGE('',*,*,#2044,.T.);
#2046=ORIENTED_EDGE('',*,*,#1561,.F.);
#2047=ORIENTED_EDGE('',*,*,#2028,.F.);
#2048=ORIENTED_EDGE('',*,*,#1307,.F.);
#2049=EDGE_LOOP('',(#2045,#2046,#2047,#2048));
#2050=FACE_BOUND('',#2049,.T.);
#2051=ADVANCED_FACE('F729',(#2050),#2039,.F.);
#2052=CARTESIAN_POINT('',(0.,0.,5.));
#2053=DIRECTION('',(0.,0.,1.));
#2054=DIRECTION('',(1.,0.,0.));
#2055=AXIS2_PLACEMENT_3D('',#2052,#2053,#2054);
#2056=CYLINDRICAL_SURFACE('',#2055,8.);
#2057=ORIENTED_EDGE('',*,*,#1298,.T.);
#2058=DIRECTION('',(0.,0.,1.));
#2059=VECTOR('',#2058,1.);
#2060=CARTESIAN_POINT('',(-0.974945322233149,-7.94037037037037,5.));
#2061=LINE('',#2060,#2059);
#2062=EDGE_CURVE('E351',#1288,#1569,#2061,.T.);
#2063=ORIENTED_EDGE('',*,*,#2062,.T.);
#2064=ORIENTED_EDGE('',*,*,#1570,.T.);
#2065=ORIENTED_EDGE('',*,*,#2044,.F.);
#2066=EDGE_LOOP('',(#2057,#2063,#2064,#2065));
#2067=FACE_BOUND('',#2066,.T.);
#2068=ADVANCED_FACE('F726',(#2067),#2056,.T.);
#2069=CARTESIAN_POINT('',(0.,-8.64,5.));
#2070=DIRECTION('',(0.,0.,1.));
#2071=DIRECTION('',(1.,0.,0.));
#2072=AXIS2_PLACEMENT_3D('',#2069,#2070,#2071);
#2073=CYLINDRICAL_SURFACE('',#2072,1.2);
#2074=DIRECTION('',(0.,0.,1.));
#2075=VECTOR('',#2074,1.);
#2076=CARTESIAN_POINT('',(0.974945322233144,-7.94037037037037,5.));
#2077=LINE('',#2076,#2075);
#2078=EDGE_CURVE('E348',#1279,#1608,#2077,.T.);
#2079=ORIENTED_EDGE('',*,*,#2078,.T.);
#2080=ORIENTED_EDGE('',*,*,#1609,.F.);
#2081=ORIENTED_EDGE('',*,*,#2062,.F.);
#2082=ORIENTED_EDGE('',*,*,#1289,.F.);
#2083=EDGE_LOOP('',(#2079,#2080,#2081,#2082));
#2084=FACE_BOUND('',#2083,.T.);
#2085=ADVANCED_FACE('F722',(#2084),#2073,.F.);
#2086=CARTESIAN_POINT('',(0.,-1.54390389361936E-13,5.));
#2087=DIRECTION('',(0.,0.,1.));
#2088=DIRECTION('',(1.,0.,0.));
#2089=AXIS2_PLACEMENT_3D('',#2086,#2087,#2088);
#2090=CYLINDRICAL_SURFACE('',#2089,7.99999999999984);
#2091=ORIENTED_EDGE('',*,*,#1280,.T.);
#2092=DIRECTION('',(0.,0.,1.));
#2093=VECTOR('',#2092,1.);
#2094=CARTESIAN_POINT('',(3.12585776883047,-7.36403511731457,5.));
#2095=LINE('',#2094,#2093);
#2096=EDGE_CURVE('E345',#1270,#1617,#2095,.T.);
#2097=ORIENTED_EDGE('',*,*,#2096,.T.);
#2098=ORIENTED_EDGE('',*,*,#1618,.T.);
#2099=ORIENTED_EDGE('',*,*,#2078,.F.);
#2100=EDGE_LOOP('',(#2091,#2097,#2098,#2099));
#2101=FACE_BOUND('',#2100,.T.);
#2102=ADVANCED_FACE('F702',(#2101),#2090,.T.);
#2103=CARTESIAN_POINT('',(4.32,-7.48245948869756,5.));
#2104=DIRECTION('',(0.,0.,1.));
#2105=DIRECTION('',(1.,0.,0.));
#2106=AXIS2_PLACEMENT_3D('',#2103,#2104,#2105);
#2107=CYLINDRICAL_SURFACE('',#2106,1.2);
#2108=DIRECTION('',(0.,0.,1.));
#2109=VECTOR('',#2108,1.);
#2110=CARTESIAN_POINT('',(4.81451260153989,-6.38908979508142,5.));
#2111=LINE('',#2110,#2109);
#2112=EDGE_CURVE('E342',#1261,#1656,#2111,.T.);
#2113=ORIENTED_EDGE('',*,*,#2112,.T.);
#2114=ORIENTED_EDGE('',*,*,#1657,.F.);
#2115=ORIENTED_EDGE('',*,*,#2096,.F.);
#2116=ORIENTED_EDGE('',*,*,#1271,.F.);
#2117=EDGE_LOOP('',(#2113,#2114,#2115,#2116));
#2118=FACE_BOUND('',#2117,.T.);
#2119=ADVANCED_FACE('F697',(#2118),#2107,.F.);
#2120=CARTESIAN_POINT('',(0.,0.,5.));
#2121=DIRECTION('',(0.,0.,1.));
#2122=DIRECTION('',(1.,0.,0.));
#2123=AXIS2_PLACEMENT_3D('',#2120,#2121,#2122);
#2124=CYLINDRICAL_SURFACE('',#2123,8.);
#2125=ORIENTED_EDGE('',*,*,#1262,.T.);
#2126=DIRECTION('',(0.,0.,1.));
#2127=VECTOR('',#2126,1.);
#2128=CARTESIAN_POINT('',(6.38908979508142,-4.8145126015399,5.));
#2129=LINE('',#2128,#2127);
#2130=EDGE_CURVE('E339',#1252,#1665,#2129,.T.);
#2131=ORIENTED_EDGE('',*,*,#2130,.T.);
#2132=ORIENTED_EDGE('',*,*,#1666,.T.);
#2133=ORIENTED_EDGE('',*,*,#2112,.F.);
#2134=EDGE_LOOP('',(#2125,#2131,#2132,#2133));
#2135=FACE_BOUND('',#2134,.T.);
#2136=ADVANCED_FACE('F693',(#2135),#2124,.T.);
#2137=CARTESIAN_POINT('',(7.48245948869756,-4.32,5.));
#2138=DIRECTION('',(0.,0.,1.));
#2139=DIRECTION('',(1.,0.,0.));
#2140=AXIS2_PLACEMENT_3D('',#2137,#2138,#2139);
#2141=CYLINDRICAL_SURFACE('',#2140,1.2);
#2142=DIRECTION('',(0.,0.,1.));
#2143=VECTOR('',#2142,1.);
#2144=CARTESIAN_POINT('',(7.36403511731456,-3.12585776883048,5.));
#2145=LINE('',#2144,#2143);
#2146=EDGE_CURVE('E336',#1243,#1704,#2145,.T.);
#2147=ORIENTED_EDGE('',*,*,#2146,.T.);
#2148=ORIENTED_EDGE('',*,*,#1705,.F.);
#2149=ORIENTED_EDGE('',*,*,#2130,.F.);
#2150=ORIENTED_EDGE('',*,*,#1253,.F.);
#2151=EDGE_LOOP('',(#2147,#2148,#2149,#2150));
#2152=FACE_BOUND('',#2151,.T.);
#2153=ADVANCED_FACE('F689',(#2152),#2141,.F.);
#2154=CARTESIAN_POINT('',(1.17093834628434E-13,0.,5.));
#2155=DIRECTION('',(0.,0.,1.));
#2156=DIRECTION('',(1.,0.,0.));
#2157=AXIS2_PLACEMENT_3D('',#2154,#2155,#2156);
#2158=CYLINDRICAL_SURFACE('',#2157,7.99999999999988);
#2159=ORIENTED_EDGE('',*,*,#1244,.T.);
#2160=DIRECTION('',(0.,0.,1.));
#2161=VECTOR('',#2160,1.);
#2162=CARTESIAN_POINT('',(7.94037037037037,-0.974945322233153,5.));
#2163=LINE('',#2162,#2161);
#2164=EDGE_CURVE('E333',#1234,#1713,#2163,.T.);
#2165=ORIENTED_EDGE('',*,*,#2164,.T.);
#2166=ORIENTED_EDGE('',*,*,#1714,.T.);
#2167=ORIENTED_EDGE('',*,*,#2146,.F.);
#2168=EDGE_LOOP('',(#2159,#2165,#2166,#2167));
#2169=FACE_BOUND('',#2168,.T.);
#2170=ADVANCED_FACE('F668',(#2169),#2158,.T.);
#2171=CARTESIAN_POINT('',(8.64,0.,5.));
#2172=DIRECTION('',(0.,0.,1.));
#2173=DIRECTION('',(1.,0.,0.));
#2174=AXIS2_PLACEMENT_3D('',#2171,#2172,#2173);
#2175=CYLINDRICAL_SURFACE('',#2174,1.2);
#2176=DIRECTION('',(0.,0.,1.));
#2177=VECTOR('',#2176,1.);
#2178=CARTESIAN_POINT('',(7.94037037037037,0.97494532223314,5.));
#2179=LINE('',#2178,#2177);
#2180=EDGE_CURVE('E330',#1225,#1752,#2179,.T.);
#2181=ORIENTED_EDGE('',*,*,#2180,.T.);
#2182=ORIENTED_EDGE('',*,*,#1753,.F.);
#2183=ORIENTED_EDGE('',*,*,#2164,.F.);
#2184=ORIENTED_EDGE('',*,*,#1235,.F.);
#2185=EDGE_LOOP('',(#2181,#2182,#2183,#2184));
#2186=FACE_BOUND('',#2185,.T.);
#2187=ADVANCED_FACE('F663',(#2186),#2175,.F.);
#2188=CARTESIAN_POINT('',(1.12757025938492E-13,0.,5.));
#2189=DIRECTION('',(0.,0.,1.));
#2190=DIRECTION('',(1.,0.,0.));
#2191=AXIS2_PLACEMENT_3D('',#2188,#2189,#2190);
#2192=CYLINDRICAL_SURFACE('',#2191,7.99999999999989);
#2193=ORIENTED_EDGE('',*,*,#1226,.T.);
#2194=DIRECTION('',(0.,0.,1.));
#2195=VECTOR('',#2194,1.);
#2196=CARTESIAN_POINT('',(7.36403511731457,3.12585776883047,5.));
#2197=LINE('',#2196,#2195);
#2198=EDGE_CURVE('E327',#1216,#1761,#2197,.T.);
#2199=ORIENTED_EDGE('',*,*,#2198,.T.);
#2200=ORIENTED_EDGE('',*,*,#1762,.T.);
#2201=ORIENTED_EDGE('',*,*,#2180,.F.);
#2202=EDGE_LOOP('',(#2193,#2199,#2200,#2201));
#2203=FACE_BOUND('',#2202,.T.);
#2204=ADVANCED_FACE('F659',(#2203),#2192,.T.);
#2205=CARTESIAN_POINT('',(7.48245948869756,4.32,5.));
#2206=DIRECTION('',(0.,0.,1.));
#2207=DIRECTION('',(1.,0.,0.));
#2208=AXIS2_PLACEMENT_3D('',#2205,#2206,#2207);
#2209=CYLINDRICAL_SURFACE('',#2208,1.2);
#2210=DIRECTION('',(0.,0.,1.));
#2211=VECTOR('',#2210,1.);
#2212=CARTESIAN_POINT('',(6.38908979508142,4.81451260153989,5.));
#2213=LINE('',#2212,#2211);
#2214=EDGE_CURVE('E324',#1207,#1800,#2213,.T.);
#2215=ORIENTED_EDGE('',*,*,#2214,.T.);
#2216=ORIENTED_EDGE('',*,*,#1801,.F.);
#2217=ORIENTED_EDGE('',*,*,#2198,.F.);
#2218=ORIENTED_EDGE('',*,*,#1217,.F.);
#2219=EDGE_LOOP('',(#2215,#2216,#2217,#2218));
#2220=FACE_BOUND('',#2219,.T.);
#2221=ADVANCED_FACE('F655',(#2220),#2209,.F.);
#2222=CARTESIAN_POINT('',(0.,0.,5.));
#2223=DIRECTION('',(0.,0.,1.));
#2224=DIRECTION('',(1.,0.,0.));
#2225=AXIS2_PLACEMENT_3D('',#2222,#2223,#2224);
#2226=CYLINDRICAL_SURFACE('',#2225,7.9999999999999);
#2227=ORIENTED_EDGE('',*,*,#1208,.T.);
#2228=DIRECTION('',(0.,0.,1.));
#2229=VECTOR('',#2228,1.);
#2230=CARTESIAN_POINT('',(4.8145126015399,6.38908979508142,5.));
#2231=LINE('',#2230,#2229);
#2232=EDGE_CURVE('E321',#1198,#1809,#2231,.T.);
#2233=ORIENTED_EDGE('',*,*,#2232,.T.);
#2234=ORIENTED_EDGE('',*,*,#1810,.T.);
#2235=ORIENTED_EDGE('',*,*,#2214,.F.);
#2236=EDGE_LOOP('',(#2227,#2233,#2234,#2235));
#2237=FACE_BOUND('',#2236,.T.);
#2238=ADVANCED_FACE('F634',(#2237),#2226,.T.);
#2239=CARTESIAN_POINT('',(4.32,7.48245948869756,5.));
#2240=DIRECTION('',(0.,0.,1.));
#2241=DIRECTION('',(1.,0.,0.));
#2242=AXIS2_PLACEMENT_3D('',#2239,#2240,#2241);
#2243=CYLINDRICAL_SURFACE('',#2242,1.2);
#2244=DIRECTION('',(0.,0.,1.));
#2245=VECTOR('',#2244,1.);
#2246=CARTESIAN_POINT('',(3.12585776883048,7.36403511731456,5.));
#2247=LINE('',#2246,#2245);
#2248=EDGE_CURVE('E318',#1189,#1848,#2247,.T.);
#2249=ORIENTED_EDGE('',*,*,#2248,.T.);
#2250=ORIENTED_EDGE('',*,*,#1849,.F.);
#2251=ORIENTED_EDGE('',*,*,#2232,.F.);
#2252=ORIENTED_EDGE('',*,*,#1199,.F.);
#2253=EDGE_LOOP('',(#2249,#2250,#2251,#2252));
#2254=FACE_BOUND('',#2253,.T.);
#2255=ADVANCED_FACE('F629',(#2254),#2243,.F.);
#2256=CARTESIAN_POINT('',(0.,0.,5.));
#2257=DIRECTION('',(0.,0.,1.));
#2258=DIRECTION('',(1.,0.,0.));
#2259=AXIS2_PLACEMENT_3D('',#2256,#2257,#2258);
#2260=CYLINDRICAL_SURFACE('',#2259,8.);
#2261=ORIENTED_EDGE('',*,*,#1190,.T.);
#2262=DIRECTION('',(0.,0.,1.));
#2263=VECTOR('',#2262,1.);
#2264=CARTESIAN_POINT('',(0.974945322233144,7.94037037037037,5.));
#2265=LINE('',#2264,#2263);
#2266=EDGE_CURVE('E315',#1180,#1857,#2265,.T.);
#2267=ORIENTED_EDGE('',*,*,#2266,.T.);
#2268=ORIENTED_EDGE('',*,*,#1858,.T.);
#2269=ORIENTED_EDGE('',*,*,#2248,.F.);
#2270=EDGE_LOOP('',(#2261,#2267,#2268,#2269));
#2271=FACE_BOUND('',#2270,.T.);
#2272=ADVANCED_FACE('F625',(#2271),#2260,.T.);
#2273=CARTESIAN_POINT('',(0.,8.64,5.));
#2274=DIRECTION('',(0.,0.,1.));
#2275=DIRECTION('',(1.,0.,0.));
#2276=AXIS2_PLACEMENT_3D('',#2273,#2274,#2275);
#2277=CYLINDRICAL_SURFACE('',#2276,1.2);
#2278=DIRECTION('',(0.,0.,1.));
#2279=VECTOR('',#2278,1.);
#2280=CARTESIAN_POINT('',(-0.974945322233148,7.94037037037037,5.));
#2281=LINE('',#2280,#2279);
#2282=EDGE_CURVE('E312',#1171,#1896,#2281,.T.);
#2283=ORIENTED_EDGE('',*,*,#2282,.T.);
#2284=ORIENTED_EDGE('',*,*,#1897,.F.);
#2285=ORIENTED_EDGE('',*,*,#2266,.F.);
#2286=ORIENTED_EDGE('',*,*,#1181,.F.);
#2287=EDGE_LOOP('',(#2283,#2284,#2285,#2286));
#2288=FACE_BOUND('',#2287,.T.);
#2289=ADVANCED_FACE('F621',(#2288),#2277,.F.);
#2290=CARTESIAN_POINT('',(0.,1.26634813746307E-13,5.));
#2291=DIRECTION('',(0.,0.,1.));
#2292=DIRECTION('',(1.,0.,0.));
#2293=AXIS2_PLACEMENT_3D('',#2290,#2291,#2292);
#2294=CYLINDRICAL_SURFACE('',#2293,7.99999999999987);
#2295=ORIENTED_EDGE('',*,*,#1172,.T.);
#2296=DIRECTION('',(0.,0.,1.));
#2297=VECTOR('',#2296,1.);
#2298=CARTESIAN_POINT('',(-3.12585776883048,7.36403511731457,5.));
#2299=LINE('',#2298,#2297);
#2300=EDGE_CURVE('E309',#1162,#1905,#2299,.T.);
#2301=ORIENTED_EDGE('',*,*,#2300,.T.);
#2302=ORIENTED_EDGE('',*,*,#1906,.T.);
#2303=ORIENTED_EDGE('',*,*,#2282,.F.);
#2304=EDGE_LOOP('',(#2295,#2301,#2302,#2303));
#2305=FACE_BOUND('',#2304,.T.);
#2306=ADVANCED_FACE('F598',(#2305),#2294,.T.);
#2307=CARTESIAN_POINT('',(-4.32,7.48245948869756,5.));
#2308=DIRECTION('',(0.,0.,1.));
#2309=DIRECTION('',(1.,0.,0.));
#2310=AXIS2_PLACEMENT_3D('',#2307,#2308,#2309);
#2311=CYLINDRICAL_SURFACE('',#2310,1.2);
#2312=DIRECTION('',(0.,0.,1.));
#2313=VECTOR('',#2312,1.);
#2314=CARTESIAN_POINT('',(-4.8145126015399,6.38908979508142,5.));
#2315=LINE('',#2314,#2313);
#2316=EDGE_CURVE('E306',#1153,#1944,#2315,.T.);
#2317=ORIENTED_EDGE('',*,*,#2316,.T.);
#2318=ORIENTED_EDGE('',*,*,#1945,.F.);
#2319=ORIENTED_EDGE('',*,*,#2300,.F.);
#2320=ORIENTED_EDGE('',*,*,#1163,.F.);
#2321=EDGE_LOOP('',(#2317,#2318,#2319,#2320));
#2322=FACE_BOUND('',#2321,.T.);
#2323=ADVANCED_FACE('F593',(#2322),#2311,.F.);
#2324=CARTESIAN_POINT('',(0.,0.,5.));
#2325=DIRECTION('',(0.,0.,1.));
#2326=DIRECTION('',(1.,0.,0.));
#2327=AXIS2_PLACEMENT_3D('',#2324,#2325,#2326);
#2328=CYLINDRICAL_SURFACE('',#2327,8.);
#2329=ORIENTED_EDGE('',*,*,#1154,.T.);
#2330=DIRECTION('',(0.,0.,1.));
#2331=VECTOR('',#2330,1.);
#2332=CARTESIAN_POINT('',(-6.38908979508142,4.8145126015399,5.));
#2333=LINE('',#2332,#2331);
#2334=EDGE_CURVE('E303',#1144,#1953,#2333,.T.);
#2335=ORIENTED_EDGE('',*,*,#2334,.T.);
#2336=ORIENTED_EDGE('',*,*,#1954,.T.);
#2337=ORIENTED_EDGE('',*,*,#2316,.F.);
#2338=EDGE_LOOP('',(#2329,#2335,#2336,#2337));
#2339=FACE_BOUND('',#2338,.T.);
#2340=ADVANCED_FACE('F589',(#2339),#2328,.T.);
#2341=CARTESIAN_POINT('',(-7.48245948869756,4.32,5.));
#2342=DIRECTION('',(0.,0.,1.));
#2343=DIRECTION('',(1.,0.,0.));
#2344=AXIS2_PLACEMENT_3D('',#2341,#2342,#2343);
#2345=CYLINDRICAL_SURFACE('',#2344,1.2);
#2346=DIRECTION('',(0.,0.,1.));
#2347=VECTOR('',#2346,1.);
#2348=CARTESIAN_POINT('',(-7.36403511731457,3.12585776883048,5.));
#2349=LINE('',#2348,#2347);
#2350=EDGE_CURVE('E300',#1135,#1425,#2349,.T.);
#2351=ORIENTED_EDGE('',*,*,#2350,.T.);
#2352=ORIENTED_EDGE('',*,*,#1991,.F.);
#2353=ORIENTED_EDGE('',*,*,#2334,.F.);
#2354=ORIENTED_EDGE('',*,*,#1145,.F.);
#2355=EDGE_LOOP('',(#2351,#2352,#2353,#2354));
#2356=FACE_BOUND('',#2355,.T.);
#2357=ADVANCED_FACE('F585',(#2356),#2345,.F.);
#2358=CARTESIAN_POINT('',(0.,0.,5.));
#2359=DIRECTION('',(0.,0.,1.));
#2360=DIRECTION('',(1.,0.,0.));
#2361=AXIS2_PLACEMENT_3D('',#2358,#2359,#2360);
#2362=CYLINDRICAL_SURFACE('',#2361,8.);
#2363=ORIENTED_EDGE('',*,*,#1136,.T.);
#2364=DIRECTION('',(0.,0.,1.));
#2365=VECTOR('',#2364,1.);
#2366=CARTESIAN_POINT('',(-7.94037037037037,0.974945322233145,5.));
#2367=LINE('',#2366,#2365);
#2368=EDGE_CURVE('E296',#1126,#1423,#2367,.T.);
#2369=ORIENTED_EDGE('',*,*,#2368,.T.);
#2370=ORIENTED_EDGE('',*,*,#1426,.T.);
#2371=ORIENTED_EDGE('',*,*,#2350,.F.);
#2372=EDGE_LOOP('',(#2363,#2369,#2370,#2371));
#2373=FACE_BOUND('',#2372,.T.);
#2374=ADVANCED_FACE('F564',(#2373),#2362,.T.);
#2375=CARTESIAN_POINT('',(-8.64,0.,5.));
#2376=DIRECTION('',(0.,0.,1.));
#2377=DIRECTION('',(1.,0.,0.));
#2378=AXIS2_PLACEMENT_3D('',#2375,#2376,#2377);
#2379=CYLINDRICAL_SURFACE('',#2378,1.2);
#2380=DIRECTION('',(0.,0.,1.));
#2381=VECTOR('',#2380,1.);
#2382=CARTESIAN_POINT('',(-7.94037037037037,-0.974945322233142,5.));
#2383=LINE('',#2382,#2381);
#2384=EDGE_CURVE('E299',#1124,#1464,#2383,.T.);
#2385=ORIENTED_EDGE('',*,*,#2384,.T.);
#2386=ORIENTED_EDGE('',*,*,#1465,.F.);
#2387=ORIENTED_EDGE('',*,*,#2368,.F.);
#2388=ORIENTED_EDGE('',*,*,#1127,.F.);
#2389=EDGE_LOOP('',(#2385,#2386,#2387,#2388));
#2390=FACE_BOUND('',#2389,.T.);
#2391=ADVANCED_FACE('F479',(#2390),#2379,.F.);
#2392=CARTESIAN_POINT('',(-1.52655665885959E-13,0.,5.));
#2393=DIRECTION('',(0.,0.,1.));
#2394=DIRECTION('',(1.,0.,0.));
#2395=AXIS2_PLACEMENT_3D('',#2392,#2393,#2394);
#2396=CYLINDRICAL_SURFACE('',#2395,7.99999999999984);
#2397=ORIENTED_EDGE('',*,*,#1332,.T.);
#2398=ORIENTED_EDGE('',*,*,#2012,.T.);
#2399=ORIENTED_EDGE('',*,*,#1474,.T.);
#2400=ORIENTED_EDGE('',*,*,#2384,.F.);
#2401=EDGE_LOOP('',(#2397,#2398,#2399,#2400));
#2402=FACE_BOUND('',#2401,.T.);
#2403=ADVANCED_FACE('F477',(#2402),#2396,.T.);
#2404=CARTESIAN_POINT('',(-4.,0.55,16.75));
#2405=DIRECTION('',(1.,0.,0.));
#2406=DIRECTION('',(0.,0.,-1.));
#2407=AXIS2_PLACEMENT_3D('',#2404,#2405,#2406);
#2408=PLANE('',#2407);
#2409=DIRECTION('',(0.,0.,-1.));
#2410=VECTOR('',#2409,1.);
#2411=CARTESIAN_POINT('',(-4.,-0.55,16.75));
#2412=LINE('',#2411,#2410);
#2413=CARTESIAN_POINT('',(-4.,-0.55,11.75));
#2414=VERTEX_POINT('',#2413);
#2415=EDGE_CURVE('E228',#61,#2414,#2412,.T.);
#2416=ORIENTED_EDGE('',*,*,#2415,.T.);
#2417=DIRECTION('',(0.,-1.,0.));
#2418=VECTOR('',#2417,1.);
#2419=CARTESIAN_POINT('',(-4.,0.55,11.75));
#2420=LINE('',#2419,#2418);
#2421=CARTESIAN_POINT('',(-4.,0.55,11.75));
#2422=VERTEX_POINT('',#2421);
#2423=EDGE_CURVE('E233',#2422,#2414,#2420,.T.);
#2424=ORIENTED_EDGE('',*,*,#2423,.F.);
#2425=DIRECTION('',(0.,0.,-1.));
#2426=VECTOR('',#2425,1.);
#2427=CARTESIAN_POINT('',(-4.,0.55,16.75));
#2428=LINE('',#2427,#2426);
#2429=EDGE_CURVE('E272',#230,#2422,#2428,.T.);
#2430=ORIENTED_EDGE('',*,*,#2429,.F.);
#2431=ORIENTED_EDGE('',*,*,#231,.F.);
#2432=EDGE_LOOP('',(#2416,#2424,#2430,#2431));
#2433=FACE_BOUND('',#2432,.T.);
#2434=ADVANCED_FACE('F230',(#2433),#2408,.T.);
#2435=CARTESIAN_POINT('',(-3.8,-0.55,16.75));
#2436=DIRECTION('',(0.,0.,-1.));
#2437=DIRECTION('',(-1.,0.,0.));
#2438=AXIS2_PLACEMENT_3D('',#2435,#2436,#2437);
#2439=CYLINDRICAL_SURFACE('',#2438,0.2);
#2440=DIRECTION('',(0.,0.,-1.));
#2441=VECTOR('',#2440,1.);
#2442=CARTESIAN_POINT('',(-3.8,-0.75,16.75));
#2443=LINE('',#2442,#2441);
#2444=CARTESIAN_POINT('',(-3.8,-0.75,11.75));
#2445=VERTEX_POINT('',#2444);
#2446=EDGE_CURVE('E237',#59,#2445,#2443,.T.);
#2447=ORIENTED_EDGE('',*,*,#2446,.T.);
#2448=CARTESIAN_POINT('',(-3.8,-0.55,11.75));
#2449=DIRECTION('',(0.,0.,1.));
#2450=DIRECTION('',(1.,0.,0.));
#2451=AXIS2_PLACEMENT_3D('',#2448,#2449,#2450);
#2452=CIRCLE('',#2451,0.2);
#2453=EDGE_CURVE('E240',#2414,#2445,#2452,.T.);
#2454=ORIENTED_EDGE('',*,*,#2453,.F.);
#2455=ORIENTED_EDGE('',*,*,#2415,.F.);
#2456=ORIENTED_EDGE('',*,*,#62,.F.);
#2457=EDGE_LOOP('',(#2447,#2454,#2455,#2456));
#2458=FACE_BOUND('',#2457,.T.);
#2459=ADVANCED_FACE('F241',(#2458),#2439,.F.);
#2460=CARTESIAN_POINT('',(-3.8,-0.75,16.75));
#2461=DIRECTION('',(0.,1.,0.));
#2462=DIRECTION('',(-1.,0.,0.));
#2463=AXIS2_PLACEMENT_3D('',#2460,#2461,#2462);
#2464=PLANE('',#2463);
#2465=DIRECTION('',(0.,0.,-1.));
#2466=VECTOR('',#2465,1.);
#2467=CARTESIAN_POINT('',(3.8,-0.75,16.75));
#2468=LINE('',#2467,#2466);
#2469=CARTESIAN_POINT('',(3.8,-0.75,11.75));
#2470=VERTEX_POINT('',#2469);
#2471=EDGE_CURVE('E281',#695,#2470,#2468,.T.);
#2472=ORIENTED_EDGE('',*,*,#2471,.T.);
#2473=DIRECTION('',(1.,0.,0.));
#2474=VECTOR('',#2473,1.);
#2475=CARTESIAN_POINT('',(-3.8,-0.75,11.75));
#2476=LINE('',#2475,#2474);
#2477=EDGE_CURVE('E246',#2445,#2470,#2476,.T.);
#2478=ORIENTED_EDGE('',*,*,#2477,.F.);
#2479=ORIENTED_EDGE('',*,*,#2446,.F.);
#2480=ORIENTED_EDGE('',*,*,#909,.F.);
#2481=EDGE_LOOP('',(#2472,#2478,#2479,#2480));
#2482=FACE_BOUND('',#2481,.T.);
#2483=ADVANCED_FACE('F539',(#2482),#2464,.T.);
#2484=CARTESIAN_POINT('',(3.8,-0.55,16.75));
#2485=DIRECTION('',(0.,0.,-1.));
#2486=DIRECTION('',(-1.,0.,0.));
#2487=AXIS2_PLACEMENT_3D('',#2484,#2485,#2486);
#2488=CYLINDRICAL_SURFACE('',#2487,0.2);
#2489=DIRECTION('',(0.,0.,-1.));
#2490=VECTOR('',#2489,1.);
#2491=CARTESIAN_POINT('',(4.,-0.55,16.75));
#2492=LINE('',#2491,#2490);
#2493=CARTESIAN_POINT('',(4.,-0.55,11.75));
#2494=VERTEX_POINT('',#2493);
#2495=EDGE_CURVE('E279',#668,#2494,#2492,.T.);
#2496=ORIENTED_EDGE('',*,*,#2495,.T.);
#2497=CARTESIAN_POINT('',(3.8,-0.55,11.75));
#2498=DIRECTION('',(0.,0.,1.));
#2499=DIRECTION('',(1.,0.,0.));
#2500=AXIS2_PLACEMENT_3D('',#2497,#2498,#2499);
#2501=CIRCLE('',#2500,0.2);
#2502=EDGE_CURVE('E260',#2470,#2494,#2501,.T.);
#2503=ORIENTED_EDGE('',*,*,#2502,.F.);
#2504=ORIENTED_EDGE('',*,*,#2471,.F.);
#2505=ORIENTED_EDGE('',*,*,#696,.F.);
#2506=EDGE_LOOP('',(#2496,#2503,#2504,#2505));
#2507=FACE_BOUND('',#2506,.T.);
#2508=ADVANCED_FACE('F825',(#2507),#2488,.F.);
#2509=CARTESIAN_POINT('',(4.,-0.55,16.75));
#2510=DIRECTION('',(-1.,0.,0.));
#2511=DIRECTION('',(0.,0.,1.));
#2512=AXIS2_PLACEMENT_3D('',#2509,#2510,#2511);
#2513=PLANE('',#2512);
#2514=DIRECTION('',(0.,0.,-1.));
#2515=VECTOR('',#2514,1.);
#2516=CARTESIAN_POINT('',(4.,0.55,16.75));
#2517=LINE('',#2516,#2515);
#2518=CARTESIAN_POINT('',(4.,0.55,11.75));
#2519=VERTEX_POINT('',#2518);
#2520=EDGE_CURVE('E277',#499,#2519,#2517,.T.);
#2521=ORIENTED_EDGE('',*,*,#2520,.T.);
#2522=DIRECTION('',(0.,1.,0.));
#2523=VECTOR('',#2522,1.);
#2524=CARTESIAN_POINT('',(4.,-0.55,11.75));
#2525=LINE('',#2524,#2523);
#2526=EDGE_CURVE('E263',#2494,#2519,#2525,.T.);
#2527=ORIENTED_EDGE('',*,*,#2526,.F.);
#2528=ORIENTED_EDGE('',*,*,#2495,.F.);
#2529=ORIENTED_EDGE('',*,*,#669,.F.);
#2530=EDGE_LOOP('',(#2521,#2527,#2528,#2529));
#2531=FACE_BOUND('',#2530,.T.);
#2532=ADVANCED_FACE('F832',(#2531),#2513,.T.);
#2533=CARTESIAN_POINT('',(3.8,0.55,16.75));
#2534=DIRECTION('',(0.,0.,-1.));
#2535=DIRECTION('',(-1.,0.,0.));
#2536=AXIS2_PLACEMENT_3D('',#2533,#2534,#2535);
#2537=CYLINDRICAL_SURFACE('',#2536,0.2);
#2538=DIRECTION('',(0.,0.,-1.));
#2539=VECTOR('',#2538,1.);
#2540=CARTESIAN_POINT('',(3.8,0.75,16.75));
#2541=LINE('',#2540,#2539);
#2542=CARTESIAN_POINT('',(3.8,0.75,11.75));
#2543=VERTEX_POINT('',#2542);
#2544=EDGE_CURVE('E275',#472,#2543,#2541,.T.);
#2545=ORIENTED_EDGE('',*,*,#2544,.T.);
#2546=CARTESIAN_POINT('',(3.8,0.55,11.75));
#2547=DIRECTION('',(0.,0.,1.));
#2548=DIRECTION('',(1.,0.,0.));
#2549=AXIS2_PLACEMENT_3D('',#2546,#2547,#2548);
#2550=CIRCLE('',#2549,0.2);
#2551=EDGE_CURVE('E266',#2519,#2543,#2550,.T.);
#2552=ORIENTED_EDGE('',*,*,#2551,.F.);
#2553=ORIENTED_EDGE('',*,*,#2520,.F.);
#2554=ORIENTED_EDGE('',*,*,#500,.F.);
#2555=EDGE_LOOP('',(#2545,#2552,#2553,#2554));
#2556=FACE_BOUND('',#2555,.T.);
#2557=ADVANCED_FACE('F839',(#2556),#2537,.F.);
#2558=CARTESIAN_POINT('',(3.8,0.75,16.75));
#2559=DIRECTION('',(0.,-1.,0.));
#2560=DIRECTION('',(1.,0.,0.));
#2561=AXIS2_PLACEMENT_3D('',#2558,#2559,#2560);
#2562=PLANE('',#2561);
#2563=ORIENTED_EDGE('',*,*,#473,.F.);
#2564=DIRECTION('',(0.,0.,-1.));
#2565=VECTOR('',#2564,1.);
#2566=CARTESIAN_POINT('',(-3.8,0.75,16.75));
#2567=LINE('',#2566,#2565);
#2568=CARTESIAN_POINT('',(-3.8,0.75,11.75));
#2569=VERTEX_POINT('',#2568);
#2570=EDGE_CURVE('E34',#257,#2569,#2567,.T.);
#2571=ORIENTED_EDGE('',*,*,#2570,.T.);
#2572=DIRECTION('',(-1.,0.,0.));
#2573=VECTOR('',#2572,1.);
#2574=CARTESIAN_POINT('',(3.8,0.75,11.75));
#2575=LINE('',#2574,#2573);
#2576=EDGE_CURVE('E269',#2543,#2569,#2575,.T.);
#2577=ORIENTED_EDGE('',*,*,#2576,.F.);
#2578=ORIENTED_EDGE('',*,*,#2544,.F.);
#2579=EDGE_LOOP('',(#2563,#2571,#2577,#2578));
#2580=FACE_BOUND('',#2579,.T.);
#2581=ADVANCED_FACE('F846',(#2580),#2562,.T.);
#2582=CARTESIAN_POINT('',(-3.8,0.55,16.75));
#2583=DIRECTION('',(0.,0.,-1.));
#2584=DIRECTION('',(-1.,0.,0.));
#2585=AXIS2_PLACEMENT_3D('',#2582,#2583,#2584);
#2586=CYLINDRICAL_SURFACE('',#2585,0.2);
#2587=ORIENTED_EDGE('',*,*,#2429,.T.);
#2588=CARTESIAN_POINT('',(-3.8,0.55,11.75));
#2589=DIRECTION('',(0.,0.,1.));
#2590=DIRECTION('',(1.,0.,0.));
#2591=AXIS2_PLACEMENT_3D('',#2588,#2589,#2590);
#2592=CIRCLE('',#2591,0.2);
#2593=EDGE_CURVE('E251',#2569,#2422,#2592,.T.);
#2594=ORIENTED_EDGE('',*,*,#2593,.F.);
#2595=ORIENTED_EDGE('',*,*,#2570,.F.);
#2596=ORIENTED_EDGE('',*,*,#258,.F.);
#2597=EDGE_LOOP('',(#2587,#2594,#2595,#2596));
#2598=FACE_BOUND('',#2597,.T.);
#2599=ADVANCED_FACE('F853',(#2598),#2586,.F.);
#2600=CARTESIAN_POINT('',(-3.8,-0.55,11.75));
#2601=DIRECTION('',(0.,0.,1.));
#2602=DIRECTION('',(1.,0.,0.));
#2603=AXIS2_PLACEMENT_3D('',#2600,#2601,#2602);
#2604=PLANE('',#2603);
#2605=ORIENTED_EDGE('',*,*,#2423,.T.);
#2606=ORIENTED_EDGE('',*,*,#2453,.T.);
#2607=ORIENTED_EDGE('',*,*,#2477,.T.);
#2608=ORIENTED_EDGE('',*,*,#2502,.T.);
#2609=ORIENTED_EDGE('',*,*,#2526,.T.);
#2610=ORIENTED_EDGE('',*,*,#2551,.T.);
#2611=ORIENTED_EDGE('',*,*,#2576,.T.);
#2612=ORIENTED_EDGE('',*,*,#2593,.T.);
#2613=EDGE_LOOP('',(#2605,#2606,#2607,#2608,#2609,#2610,#2611,#2612));
#2614=FACE_BOUND('',#2613,.T.);
#2615=ADVANCED_FACE('F249',(#2614),#2604,.T.);
#2616=CARTESIAN_POINT('',(0.,0.,6.));
#2617=DIRECTION('',(0.,0.,-1.));
#2618=DIRECTION('',(-1.,0.,0.));
#2619=AXIS2_PLACEMENT_3D('',#2616,#2617,#2618);
#2620=CYLINDRICAL_SURFACE('',#2619,1.5);
#2621=CARTESIAN_POINT('',(0.,0.,6.));
#2622=DIRECTION('',(0.,0.,-1.));
#2623=DIRECTION('',(-1.,0.,0.));
#2624=AXIS2_PLACEMENT_3D('',#2621,#2622,#2623);
#2625=CIRCLE('',#2624,1.5);
#2626=CARTESIAN_POINT('',(-1.5,0.,6.));
#2627=VERTEX_POINT('',#2626);
#2628=EDGE_CURVE('E252',#2627,#2627,#2625,.T.);
#2629=ORIENTED_EDGE('',*,*,#2628,.F.);
#2630=EDGE_LOOP('',(#2629));
#2631=FACE_BOUND('',#2630,.T.);
#2632=ORIENTED_EDGE('',*,*,#937,.T.);
#2633=EDGE_LOOP('',(#2632));
#2634=FACE_BOUND('',#2633,.T.);
#2635=ADVANCED_FACE('F865',(#2631,#2634),#2620,.F.);
#2636=CARTESIAN_POINT('',(0.,0.,6.));
#2637=DIRECTION('',(0.,0.,-1.));
#2638=DIRECTION('',(-1.,0.,0.));
#2639=AXIS2_PLACEMENT_3D('',#2636,#2637,#2638);
#2640=PLANE('',#2639);
#2641=ORIENTED_EDGE('',*,*,#2628,.T.);
#2642=EDGE_LOOP('',(#2641));
#2643=FACE_BOUND('',#2642,.T.);
#2644=ADVANCED_FACE('F872',(#2643),#2640,.T.);
#2645=CLOSED_SHELL('',(#913,#941,#961,#981,#1001,#1021,#1041,#1061,#1081,#1101,#1336,#1356,
#1376,#1388,#1408,#1995,#2017,#2034,#2051,#2068,#2085,#2102,#2119,#2136,#2153,#2170,#2187,#2204,
#2221,#2238,#2255,#2272,#2289,#2306,#2323,#2340,#2357,#2374,#2391,#2403,#2434,#2459,#2483,#2508,
#2532,#2557,#2581,#2599,#2615,#2635,#2644));
#2646=MANIFOLD_SOLID_BREP('B1',#2645);
#2647=ADVANCED_BREP_SHAPE_REPRESENTATION('',(#18,#2646),#14);
#2648=SHAPE_DEFINITION_REPRESENTATION(#9,#2647);
ENDSEC;
END-ISO-10303-21;
